VERSION 5.8 ;
BUSBITCHARS "[]" ;
DIVIDERCHAR "/" ;
UNITS
    DATABASE MICRONS 1000 ;
END UNITS

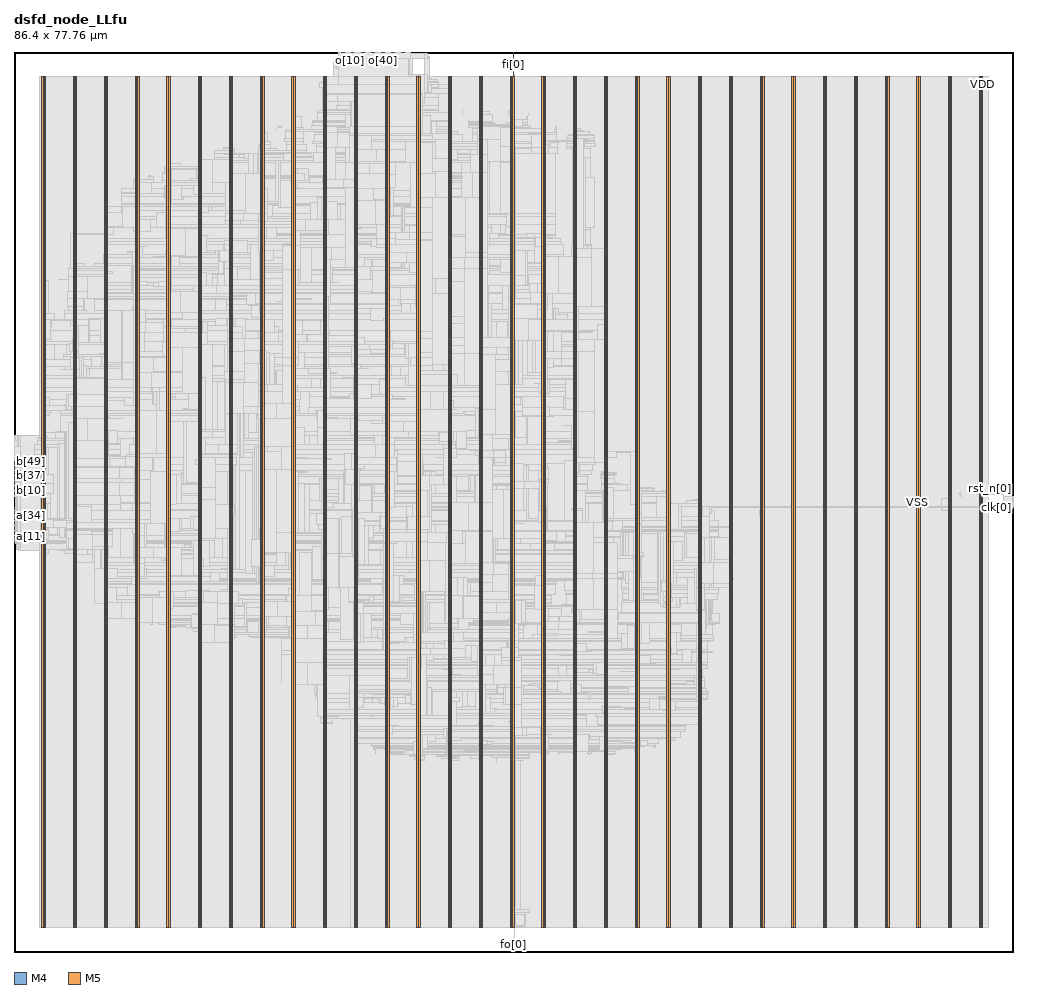
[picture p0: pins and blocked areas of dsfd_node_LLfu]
MACRO dsfd_node_LLfu
  FOREIGN dsfd_node_LLfu 0 0 ;
  CLASS BLOCK ;
  SIZE 86.4 BY 77.76 ;
  PIN a[0]
    DIRECTION INPUT ;
    USE SIGNAL ;
    PORT
      LAYER M4 ;
        RECT  0 35.376 0.084 35.4 ;
    END
  END a[0]
  PIN a[10]
    DIRECTION INPUT ;
    USE SIGNAL ;
    PORT
      LAYER M4 ;
        RECT  0 35.856 0.084 35.88 ;
    END
  END a[10]
  PIN a[11]
    DIRECTION INPUT ;
    USE SIGNAL ;
    PORT
      LAYER M4 ;
        RECT  0 35.904 0.084 35.928 ;
    END
  END a[11]
  PIN a[12]
    DIRECTION INPUT ;
    USE SIGNAL ;
    PORT
      LAYER M4 ;
        RECT  0 35.952 0.084 35.976 ;
    END
  END a[12]
  PIN a[13]
    DIRECTION INPUT ;
    USE SIGNAL ;
    PORT
      LAYER M4 ;
        RECT  0 36 0.084 36.024 ;
    END
  END a[13]
  PIN a[14]
    DIRECTION INPUT ;
    USE SIGNAL ;
    PORT
      LAYER M4 ;
        RECT  0 36.048 0.084 36.072 ;
    END
  END a[14]
  PIN a[15]
    DIRECTION INPUT ;
    USE SIGNAL ;
    PORT
      LAYER M4 ;
        RECT  0 36.096 0.084 36.12 ;
    END
  END a[15]
  PIN a[16]
    DIRECTION INPUT ;
    USE SIGNAL ;
    PORT
      LAYER M4 ;
        RECT  0 36.144 0.084 36.168 ;
    END
  END a[16]
  PIN a[17]
    DIRECTION INPUT ;
    USE SIGNAL ;
    PORT
      LAYER M4 ;
        RECT  0 36.192 0.084 36.216 ;
    END
  END a[17]
  PIN a[18]
    DIRECTION INPUT ;
    USE SIGNAL ;
    PORT
      LAYER M4 ;
        RECT  0 36.24 0.084 36.264 ;
    END
  END a[18]
  PIN a[19]
    DIRECTION INPUT ;
    USE SIGNAL ;
    PORT
      LAYER M4 ;
        RECT  0 36.288 0.084 36.312 ;
    END
  END a[19]
  PIN a[1]
    DIRECTION INPUT ;
    USE SIGNAL ;
    PORT
      LAYER M4 ;
        RECT  0 35.424 0.084 35.448 ;
    END
  END a[1]
  PIN a[20]
    DIRECTION INPUT ;
    USE SIGNAL ;
    PORT
      LAYER M4 ;
        RECT  0 36.336 0.084 36.36 ;
    END
  END a[20]
  PIN a[21]
    DIRECTION INPUT ;
    USE SIGNAL ;
    PORT
      LAYER M4 ;
        RECT  0 36.384 0.084 36.408 ;
    END
  END a[21]
  PIN a[22]
    DIRECTION INPUT ;
    USE SIGNAL ;
    PORT
      LAYER M4 ;
        RECT  0 36.432 0.084 36.456 ;
    END
  END a[22]
  PIN a[23]
    DIRECTION INPUT ;
    USE SIGNAL ;
    PORT
      LAYER M4 ;
        RECT  0 36.48 0.084 36.504 ;
    END
  END a[23]
  PIN a[24]
    DIRECTION INPUT ;
    USE SIGNAL ;
    PORT
      LAYER M4 ;
        RECT  0 36.528 0.084 36.552 ;
    END
  END a[24]
  PIN a[25]
    DIRECTION INPUT ;
    USE SIGNAL ;
    PORT
      LAYER M4 ;
        RECT  0 36.576 0.084 36.6 ;
    END
  END a[25]
  PIN a[26]
    DIRECTION INPUT ;
    USE SIGNAL ;
    PORT
      LAYER M4 ;
        RECT  0 36.624 0.084 36.648 ;
    END
  END a[26]
  PIN a[27]
    DIRECTION INPUT ;
    USE SIGNAL ;
    PORT
      LAYER M4 ;
        RECT  0 36.672 0.084 36.696 ;
    END
  END a[27]
  PIN a[28]
    DIRECTION INPUT ;
    USE SIGNAL ;
    PORT
      LAYER M4 ;
        RECT  0 36.72 0.084 36.744 ;
    END
  END a[28]
  PIN a[29]
    DIRECTION INPUT ;
    USE SIGNAL ;
    PORT
      LAYER M4 ;
        RECT  0 36.768 0.084 36.792 ;
    END
  END a[29]
  PIN a[2]
    DIRECTION INPUT ;
    USE SIGNAL ;
    PORT
      LAYER M4 ;
        RECT  0 35.472 0.084 35.496 ;
    END
  END a[2]
  PIN a[30]
    DIRECTION INPUT ;
    USE SIGNAL ;
    PORT
      LAYER M4 ;
        RECT  0 36.816 0.084 36.84 ;
    END
  END a[30]
  PIN a[31]
    DIRECTION INPUT ;
    USE SIGNAL ;
    PORT
      LAYER M4 ;
        RECT  0 36.864 0.084 36.888 ;
    END
  END a[31]
  PIN a[32]
    DIRECTION INPUT ;
    USE SIGNAL ;
    PORT
      LAYER M4 ;
        RECT  0 36.912 0.084 36.936 ;
    END
  END a[32]
  PIN a[33]
    DIRECTION INPUT ;
    USE SIGNAL ;
    PORT
      LAYER M4 ;
        RECT  0 36.96 0.084 36.984 ;
    END
  END a[33]
  PIN a[34]
    DIRECTION INPUT ;
    USE SIGNAL ;
    PORT
      LAYER M4 ;
        RECT  0 37.008 0.084 37.032 ;
    END
  END a[34]
  PIN a[35]
    DIRECTION INPUT ;
    USE SIGNAL ;
    PORT
      LAYER M4 ;
        RECT  0 37.056 0.084 37.08 ;
    END
  END a[35]
  PIN a[36]
    DIRECTION INPUT ;
    USE SIGNAL ;
    PORT
      LAYER M4 ;
        RECT  0 37.104 0.084 37.128 ;
    END
  END a[36]
  PIN a[37]
    DIRECTION INPUT ;
    USE SIGNAL ;
    PORT
      LAYER M4 ;
        RECT  0 37.152 0.084 37.176 ;
    END
  END a[37]
  PIN a[38]
    DIRECTION INPUT ;
    USE SIGNAL ;
    PORT
      LAYER M4 ;
        RECT  0 37.2 0.084 37.224 ;
    END
  END a[38]
  PIN a[39]
    DIRECTION INPUT ;
    USE SIGNAL ;
    PORT
      LAYER M4 ;
        RECT  0 37.248 0.084 37.272 ;
    END
  END a[39]
  PIN a[3]
    DIRECTION INPUT ;
    USE SIGNAL ;
    PORT
      LAYER M4 ;
        RECT  0 35.52 0.084 35.544 ;
    END
  END a[3]
  PIN a[40]
    DIRECTION INPUT ;
    USE SIGNAL ;
    PORT
      LAYER M4 ;
        RECT  0 37.296 0.084 37.32 ;
    END
  END a[40]
  PIN a[41]
    DIRECTION INPUT ;
    USE SIGNAL ;
    PORT
      LAYER M4 ;
        RECT  0 37.344 0.084 37.368 ;
    END
  END a[41]
  PIN a[42]
    DIRECTION INPUT ;
    USE SIGNAL ;
    PORT
      LAYER M4 ;
        RECT  0 37.392 0.084 37.416 ;
    END
  END a[42]
  PIN a[43]
    DIRECTION INPUT ;
    USE SIGNAL ;
    PORT
      LAYER M4 ;
        RECT  0 37.44 0.084 37.464 ;
    END
  END a[43]
  PIN a[44]
    DIRECTION INPUT ;
    USE SIGNAL ;
    PORT
      LAYER M4 ;
        RECT  0 37.488 0.084 37.512 ;
    END
  END a[44]
  PIN a[45]
    DIRECTION INPUT ;
    USE SIGNAL ;
    PORT
      LAYER M4 ;
        RECT  0 37.536 0.084 37.56 ;
    END
  END a[45]
  PIN a[46]
    DIRECTION INPUT ;
    USE SIGNAL ;
    PORT
      LAYER M4 ;
        RECT  0 37.584 0.084 37.608 ;
    END
  END a[46]
  PIN a[47]
    DIRECTION INPUT ;
    USE SIGNAL ;
    PORT
      LAYER M4 ;
        RECT  0 37.632 0.084 37.656 ;
    END
  END a[47]
  PIN a[48]
    DIRECTION INPUT ;
    USE SIGNAL ;
    PORT
      LAYER M4 ;
        RECT  0 37.68 0.084 37.704 ;
    END
  END a[48]
  PIN a[49]
    DIRECTION INPUT ;
    USE SIGNAL ;
    PORT
      LAYER M4 ;
        RECT  0 37.728 0.084 37.752 ;
    END
  END a[49]
  PIN a[4]
    DIRECTION INPUT ;
    USE SIGNAL ;
    PORT
      LAYER M4 ;
        RECT  0 35.568 0.084 35.592 ;
    END
  END a[4]
  PIN a[50]
    DIRECTION INPUT ;
    USE SIGNAL ;
    PORT
      LAYER M4 ;
        RECT  0 37.776 0.084 37.8 ;
    END
  END a[50]
  PIN a[51]
    DIRECTION INPUT ;
    USE SIGNAL ;
    PORT
      LAYER M4 ;
        RECT  0 37.824 0.084 37.848 ;
    END
  END a[51]
  PIN a[52]
    DIRECTION INPUT ;
    USE SIGNAL ;
    PORT
      LAYER M4 ;
        RECT  0 37.872 0.084 37.896 ;
    END
  END a[52]
  PIN a[53]
    DIRECTION INPUT ;
    USE SIGNAL ;
    PORT
      LAYER M4 ;
        RECT  0 37.92 0.084 37.944 ;
    END
  END a[53]
  PIN a[54]
    DIRECTION INPUT ;
    USE SIGNAL ;
    PORT
      LAYER M4 ;
        RECT  0 37.968 0.084 37.992 ;
    END
  END a[54]
  PIN a[55]
    DIRECTION INPUT ;
    USE SIGNAL ;
    PORT
      LAYER M4 ;
        RECT  0 38.016 0.084 38.04 ;
    END
  END a[55]
  PIN a[56]
    DIRECTION INPUT ;
    USE SIGNAL ;
    PORT
      LAYER M4 ;
        RECT  0 38.064 0.084 38.088 ;
    END
  END a[56]
  PIN a[57]
    DIRECTION INPUT ;
    USE SIGNAL ;
    PORT
      LAYER M4 ;
        RECT  0 38.112 0.084 38.136 ;
    END
  END a[57]
  PIN a[58]
    DIRECTION INPUT ;
    USE SIGNAL ;
    PORT
      LAYER M4 ;
        RECT  0 38.16 0.084 38.184 ;
    END
  END a[58]
  PIN a[59]
    DIRECTION INPUT ;
    USE SIGNAL ;
    PORT
      LAYER M4 ;
        RECT  0 38.208 0.084 38.232 ;
    END
  END a[59]
  PIN a[5]
    DIRECTION INPUT ;
    USE SIGNAL ;
    PORT
      LAYER M4 ;
        RECT  0 35.616 0.084 35.64 ;
    END
  END a[5]
  PIN a[60]
    DIRECTION INPUT ;
    USE SIGNAL ;
    PORT
      LAYER M4 ;
        RECT  0 38.256 0.084 38.28 ;
    END
  END a[60]
  PIN a[61]
    DIRECTION INPUT ;
    USE SIGNAL ;
    PORT
      LAYER M4 ;
        RECT  0 38.304 0.084 38.328 ;
    END
  END a[61]
  PIN a[62]
    DIRECTION INPUT ;
    USE SIGNAL ;
    PORT
      LAYER M4 ;
        RECT  0 38.352 0.084 38.376 ;
    END
  END a[62]
  PIN a[6]
    DIRECTION INPUT ;
    USE SIGNAL ;
    PORT
      LAYER M4 ;
        RECT  0 35.664 0.084 35.688 ;
    END
  END a[6]
  PIN a[7]
    DIRECTION INPUT ;
    USE SIGNAL ;
    PORT
      LAYER M4 ;
        RECT  0 35.712 0.084 35.736 ;
    END
  END a[7]
  PIN a[8]
    DIRECTION INPUT ;
    USE SIGNAL ;
    PORT
      LAYER M4 ;
        RECT  0 35.76 0.084 35.784 ;
    END
  END a[8]
  PIN a[9]
    DIRECTION INPUT ;
    USE SIGNAL ;
    PORT
      LAYER M4 ;
        RECT  0 35.808 0.084 35.832 ;
    END
  END a[9]
  PIN b[0]
    DIRECTION INPUT ;
    USE SIGNAL ;
    PORT
      LAYER M4 ;
        RECT  0 39.36 0.084 39.384 ;
    END
  END b[0]
  PIN b[10]
    DIRECTION INPUT ;
    USE SIGNAL ;
    PORT
      LAYER M4 ;
        RECT  0 39.84 0.084 39.864 ;
    END
  END b[10]
  PIN b[11]
    DIRECTION INPUT ;
    USE SIGNAL ;
    PORT
      LAYER M4 ;
        RECT  0 39.888 0.084 39.912 ;
    END
  END b[11]
  PIN b[12]
    DIRECTION INPUT ;
    USE SIGNAL ;
    PORT
      LAYER M4 ;
        RECT  0 39.936 0.084 39.96 ;
    END
  END b[12]
  PIN b[13]
    DIRECTION INPUT ;
    USE SIGNAL ;
    PORT
      LAYER M4 ;
        RECT  0 39.984 0.084 40.008 ;
    END
  END b[13]
  PIN b[14]
    DIRECTION INPUT ;
    USE SIGNAL ;
    PORT
      LAYER M4 ;
        RECT  0 40.032 0.084 40.056 ;
    END
  END b[14]
  PIN b[15]
    DIRECTION INPUT ;
    USE SIGNAL ;
    PORT
      LAYER M4 ;
        RECT  0 40.08 0.084 40.104 ;
    END
  END b[15]
  PIN b[16]
    DIRECTION INPUT ;
    USE SIGNAL ;
    PORT
      LAYER M4 ;
        RECT  0 40.128 0.084 40.152 ;
    END
  END b[16]
  PIN b[17]
    DIRECTION INPUT ;
    USE SIGNAL ;
    PORT
      LAYER M4 ;
        RECT  0 40.176 0.084 40.2 ;
    END
  END b[17]
  PIN b[18]
    DIRECTION INPUT ;
    USE SIGNAL ;
    PORT
      LAYER M4 ;
        RECT  0 40.224 0.084 40.248 ;
    END
  END b[18]
  PIN b[19]
    DIRECTION INPUT ;
    USE SIGNAL ;
    PORT
      LAYER M4 ;
        RECT  0 40.272 0.084 40.296 ;
    END
  END b[19]
  PIN b[1]
    DIRECTION INPUT ;
    USE SIGNAL ;
    PORT
      LAYER M4 ;
        RECT  0 39.408 0.084 39.432 ;
    END
  END b[1]
  PIN b[20]
    DIRECTION INPUT ;
    USE SIGNAL ;
    PORT
      LAYER M4 ;
        RECT  0 40.32 0.084 40.344 ;
    END
  END b[20]
  PIN b[21]
    DIRECTION INPUT ;
    USE SIGNAL ;
    PORT
      LAYER M4 ;
        RECT  0 40.368 0.084 40.392 ;
    END
  END b[21]
  PIN b[22]
    DIRECTION INPUT ;
    USE SIGNAL ;
    PORT
      LAYER M4 ;
        RECT  0 40.416 0.084 40.44 ;
    END
  END b[22]
  PIN b[23]
    DIRECTION INPUT ;
    USE SIGNAL ;
    PORT
      LAYER M4 ;
        RECT  0 40.464 0.084 40.488 ;
    END
  END b[23]
  PIN b[24]
    DIRECTION INPUT ;
    USE SIGNAL ;
    PORT
      LAYER M4 ;
        RECT  0 40.512 0.084 40.536 ;
    END
  END b[24]
  PIN b[25]
    DIRECTION INPUT ;
    USE SIGNAL ;
    PORT
      LAYER M4 ;
        RECT  0 40.56 0.084 40.584 ;
    END
  END b[25]
  PIN b[26]
    DIRECTION INPUT ;
    USE SIGNAL ;
    PORT
      LAYER M4 ;
        RECT  0 40.608 0.084 40.632 ;
    END
  END b[26]
  PIN b[27]
    DIRECTION INPUT ;
    USE SIGNAL ;
    PORT
      LAYER M4 ;
        RECT  0 40.656 0.084 40.68 ;
    END
  END b[27]
  PIN b[28]
    DIRECTION INPUT ;
    USE SIGNAL ;
    PORT
      LAYER M4 ;
        RECT  0 40.704 0.084 40.728 ;
    END
  END b[28]
  PIN b[29]
    DIRECTION INPUT ;
    USE SIGNAL ;
    PORT
      LAYER M4 ;
        RECT  0 40.752 0.084 40.776 ;
    END
  END b[29]
  PIN b[2]
    DIRECTION INPUT ;
    USE SIGNAL ;
    PORT
      LAYER M4 ;
        RECT  0 39.456 0.084 39.48 ;
    END
  END b[2]
  PIN b[30]
    DIRECTION INPUT ;
    USE SIGNAL ;
    PORT
      LAYER M4 ;
        RECT  0 40.8 0.084 40.824 ;
    END
  END b[30]
  PIN b[31]
    DIRECTION INPUT ;
    USE SIGNAL ;
    PORT
      LAYER M4 ;
        RECT  0 40.848 0.084 40.872 ;
    END
  END b[31]
  PIN b[32]
    DIRECTION INPUT ;
    USE SIGNAL ;
    PORT
      LAYER M4 ;
        RECT  0 40.896 0.084 40.92 ;
    END
  END b[32]
  PIN b[33]
    DIRECTION INPUT ;
    USE SIGNAL ;
    PORT
      LAYER M4 ;
        RECT  0 40.944 0.084 40.968 ;
    END
  END b[33]
  PIN b[34]
    DIRECTION INPUT ;
    USE SIGNAL ;
    PORT
      LAYER M4 ;
        RECT  0 40.992 0.084 41.016 ;
    END
  END b[34]
  PIN b[35]
    DIRECTION INPUT ;
    USE SIGNAL ;
    PORT
      LAYER M4 ;
        RECT  0 41.04 0.084 41.064 ;
    END
  END b[35]
  PIN b[36]
    DIRECTION INPUT ;
    USE SIGNAL ;
    PORT
      LAYER M4 ;
        RECT  0 41.088 0.084 41.112 ;
    END
  END b[36]
  PIN b[37]
    DIRECTION INPUT ;
    USE SIGNAL ;
    PORT
      LAYER M4 ;
        RECT  0 41.136 0.084 41.16 ;
    END
  END b[37]
  PIN b[38]
    DIRECTION INPUT ;
    USE SIGNAL ;
    PORT
      LAYER M4 ;
        RECT  0 41.184 0.084 41.208 ;
    END
  END b[38]
  PIN b[39]
    DIRECTION INPUT ;
    USE SIGNAL ;
    PORT
      LAYER M4 ;
        RECT  0 41.232 0.084 41.256 ;
    END
  END b[39]
  PIN b[3]
    DIRECTION INPUT ;
    USE SIGNAL ;
    PORT
      LAYER M4 ;
        RECT  0 39.504 0.084 39.528 ;
    END
  END b[3]
  PIN b[40]
    DIRECTION INPUT ;
    USE SIGNAL ;
    PORT
      LAYER M4 ;
        RECT  0 41.28 0.084 41.304 ;
    END
  END b[40]
  PIN b[41]
    DIRECTION INPUT ;
    USE SIGNAL ;
    PORT
      LAYER M4 ;
        RECT  0 41.328 0.084 41.352 ;
    END
  END b[41]
  PIN b[42]
    DIRECTION INPUT ;
    USE SIGNAL ;
    PORT
      LAYER M4 ;
        RECT  0 41.376 0.084 41.4 ;
    END
  END b[42]
  PIN b[43]
    DIRECTION INPUT ;
    USE SIGNAL ;
    PORT
      LAYER M4 ;
        RECT  0 41.424 0.084 41.448 ;
    END
  END b[43]
  PIN b[44]
    DIRECTION INPUT ;
    USE SIGNAL ;
    PORT
      LAYER M4 ;
        RECT  0 41.472 0.084 41.496 ;
    END
  END b[44]
  PIN b[45]
    DIRECTION INPUT ;
    USE SIGNAL ;
    PORT
      LAYER M4 ;
        RECT  0 41.52 0.084 41.544 ;
    END
  END b[45]
  PIN b[46]
    DIRECTION INPUT ;
    USE SIGNAL ;
    PORT
      LAYER M4 ;
        RECT  0 41.568 0.084 41.592 ;
    END
  END b[46]
  PIN b[47]
    DIRECTION INPUT ;
    USE SIGNAL ;
    PORT
      LAYER M4 ;
        RECT  0 41.616 0.084 41.64 ;
    END
  END b[47]
  PIN b[48]
    DIRECTION INPUT ;
    USE SIGNAL ;
    PORT
      LAYER M4 ;
        RECT  0 41.664 0.084 41.688 ;
    END
  END b[48]
  PIN b[49]
    DIRECTION INPUT ;
    USE SIGNAL ;
    PORT
      LAYER M4 ;
        RECT  0 41.712 0.084 41.736 ;
    END
  END b[49]
  PIN b[4]
    DIRECTION INPUT ;
    USE SIGNAL ;
    PORT
      LAYER M4 ;
        RECT  0 39.552 0.084 39.576 ;
    END
  END b[4]
  PIN b[50]
    DIRECTION INPUT ;
    USE SIGNAL ;
    PORT
      LAYER M4 ;
        RECT  0 41.76 0.084 41.784 ;
    END
  END b[50]
  PIN b[51]
    DIRECTION INPUT ;
    USE SIGNAL ;
    PORT
      LAYER M4 ;
        RECT  0 41.808 0.084 41.832 ;
    END
  END b[51]
  PIN b[52]
    DIRECTION INPUT ;
    USE SIGNAL ;
    PORT
      LAYER M4 ;
        RECT  0 41.856 0.084 41.88 ;
    END
  END b[52]
  PIN b[53]
    DIRECTION INPUT ;
    USE SIGNAL ;
    PORT
      LAYER M4 ;
        RECT  0 41.904 0.084 41.928 ;
    END
  END b[53]
  PIN b[54]
    DIRECTION INPUT ;
    USE SIGNAL ;
    PORT
      LAYER M4 ;
        RECT  0 41.952 0.084 41.976 ;
    END
  END b[54]
  PIN b[55]
    DIRECTION INPUT ;
    USE SIGNAL ;
    PORT
      LAYER M4 ;
        RECT  0 42 0.084 42.024 ;
    END
  END b[55]
  PIN b[56]
    DIRECTION INPUT ;
    USE SIGNAL ;
    PORT
      LAYER M4 ;
        RECT  0 42.048 0.084 42.072 ;
    END
  END b[56]
  PIN b[57]
    DIRECTION INPUT ;
    USE SIGNAL ;
    PORT
      LAYER M4 ;
        RECT  0 42.096 0.084 42.12 ;
    END
  END b[57]
  PIN b[58]
    DIRECTION INPUT ;
    USE SIGNAL ;
    PORT
      LAYER M4 ;
        RECT  0 42.144 0.084 42.168 ;
    END
  END b[58]
  PIN b[59]
    DIRECTION INPUT ;
    USE SIGNAL ;
    PORT
      LAYER M4 ;
        RECT  0 42.192 0.084 42.216 ;
    END
  END b[59]
  PIN b[5]
    DIRECTION INPUT ;
    USE SIGNAL ;
    PORT
      LAYER M4 ;
        RECT  0 39.6 0.084 39.624 ;
    END
  END b[5]
  PIN b[60]
    DIRECTION INPUT ;
    USE SIGNAL ;
    PORT
      LAYER M4 ;
        RECT  0 42.24 0.084 42.264 ;
    END
  END b[60]
  PIN b[61]
    DIRECTION INPUT ;
    USE SIGNAL ;
    PORT
      LAYER M4 ;
        RECT  0 42.288 0.084 42.312 ;
    END
  END b[61]
  PIN b[62]
    DIRECTION INPUT ;
    USE SIGNAL ;
    PORT
      LAYER M4 ;
        RECT  0 42.336 0.084 42.36 ;
    END
  END b[62]
  PIN b[6]
    DIRECTION INPUT ;
    USE SIGNAL ;
    PORT
      LAYER M4 ;
        RECT  0 39.648 0.084 39.672 ;
    END
  END b[6]
  PIN b[7]
    DIRECTION INPUT ;
    USE SIGNAL ;
    PORT
      LAYER M4 ;
        RECT  0 39.696 0.084 39.72 ;
    END
  END b[7]
  PIN b[8]
    DIRECTION INPUT ;
    USE SIGNAL ;
    PORT
      LAYER M4 ;
        RECT  0 39.744 0.084 39.768 ;
    END
  END b[8]
  PIN b[9]
    DIRECTION INPUT ;
    USE SIGNAL ;
    PORT
      LAYER M4 ;
        RECT  0 39.792 0.084 39.816 ;
    END
  END b[9]
  PIN clk[0]
    DIRECTION INPUT ;
    USE SIGNAL ;
    PORT
      LAYER M4 ;
        RECT  86.316 38.352 86.4 38.376 ;
    END
    PORT
      LAYER M4 ;
        RECT  86.321 38.352 86.364 38.376 ;
    END
  END clk[0]
  PIN fi[0]
    DIRECTION INPUT ;
    USE SIGNAL ;
    PORT
      LAYER M5 ;
        RECT  43.152 77.676 43.176 77.76 ;
    END
    PORT
      LAYER M5 ;
        RECT  43.152 75.623 43.176 77.712 ;
    END
  END fi[0]
  PIN fo[0]
    DIRECTION OUTPUT ;
    USE SIGNAL ;
    PORT
      LAYER M5 ;
        RECT  43.152 0 43.176 0.084 ;
    END
    PORT
      LAYER M5 ;
        RECT  43.152 0.016 43.176 0.563 ;
    END
  END fo[0]
  PIN o[0]
    DIRECTION OUTPUT ;
    USE SIGNAL ;
    PORT
      LAYER M5 ;
        RECT  28.032 77.676 28.056 77.76 ;
    END
  END o[0]
  PIN o[10]
    DIRECTION OUTPUT ;
    USE SIGNAL ;
    PORT
      LAYER M5 ;
        RECT  28.992 77.676 29.016 77.76 ;
    END
  END o[10]
  PIN o[11]
    DIRECTION OUTPUT ;
    USE SIGNAL ;
    PORT
      LAYER M5 ;
        RECT  29.088 77.676 29.112 77.76 ;
    END
  END o[11]
  PIN o[12]
    DIRECTION OUTPUT ;
    USE SIGNAL ;
    PORT
      LAYER M5 ;
        RECT  29.184 77.676 29.208 77.76 ;
    END
  END o[12]
  PIN o[13]
    DIRECTION OUTPUT ;
    USE SIGNAL ;
    PORT
      LAYER M5 ;
        RECT  29.28 77.676 29.304 77.76 ;
    END
  END o[13]
  PIN o[14]
    DIRECTION OUTPUT ;
    USE SIGNAL ;
    PORT
      LAYER M5 ;
        RECT  29.376 77.676 29.4 77.76 ;
    END
  END o[14]
  PIN o[15]
    DIRECTION OUTPUT ;
    USE SIGNAL ;
    PORT
      LAYER M5 ;
        RECT  29.472 77.676 29.496 77.76 ;
    END
  END o[15]
  PIN o[16]
    DIRECTION OUTPUT ;
    USE SIGNAL ;
    PORT
      LAYER M5 ;
        RECT  29.568 77.676 29.592 77.76 ;
    END
  END o[16]
  PIN o[17]
    DIRECTION OUTPUT ;
    USE SIGNAL ;
    PORT
      LAYER M5 ;
        RECT  29.664 77.676 29.688 77.76 ;
    END
  END o[17]
  PIN o[18]
    DIRECTION OUTPUT ;
    USE SIGNAL ;
    PORT
      LAYER M5 ;
        RECT  29.76 77.676 29.784 77.76 ;
    END
  END o[18]
  PIN o[19]
    DIRECTION OUTPUT ;
    USE SIGNAL ;
    PORT
      LAYER M5 ;
        RECT  29.856 77.676 29.88 77.76 ;
    END
  END o[19]
  PIN o[1]
    DIRECTION OUTPUT ;
    USE SIGNAL ;
    PORT
      LAYER M5 ;
        RECT  28.128 77.676 28.152 77.76 ;
    END
  END o[1]
  PIN o[20]
    DIRECTION OUTPUT ;
    USE SIGNAL ;
    PORT
      LAYER M5 ;
        RECT  29.952 77.676 29.976 77.76 ;
    END
  END o[20]
  PIN o[21]
    DIRECTION OUTPUT ;
    USE SIGNAL ;
    PORT
      LAYER M5 ;
        RECT  30.048 77.676 30.072 77.76 ;
    END
  END o[21]
  PIN o[22]
    DIRECTION OUTPUT ;
    USE SIGNAL ;
    PORT
      LAYER M5 ;
        RECT  30.144 77.676 30.168 77.76 ;
    END
  END o[22]
  PIN o[23]
    DIRECTION OUTPUT ;
    USE SIGNAL ;
    PORT
      LAYER M5 ;
        RECT  30.24 77.676 30.264 77.76 ;
    END
  END o[23]
  PIN o[24]
    DIRECTION OUTPUT ;
    USE SIGNAL ;
    PORT
      LAYER M5 ;
        RECT  30.336 77.676 30.36 77.76 ;
    END
  END o[24]
  PIN o[25]
    DIRECTION OUTPUT ;
    USE SIGNAL ;
    PORT
      LAYER M5 ;
        RECT  30.432 77.676 30.456 77.76 ;
    END
  END o[25]
  PIN o[26]
    DIRECTION OUTPUT ;
    USE SIGNAL ;
    PORT
      LAYER M5 ;
        RECT  30.528 77.676 30.552 77.76 ;
    END
  END o[26]
  PIN o[27]
    DIRECTION OUTPUT ;
    USE SIGNAL ;
    PORT
      LAYER M5 ;
        RECT  30.624 77.676 30.648 77.76 ;
    END
  END o[27]
  PIN o[28]
    DIRECTION OUTPUT ;
    USE SIGNAL ;
    PORT
      LAYER M5 ;
        RECT  30.72 77.676 30.744 77.76 ;
    END
  END o[28]
  PIN o[29]
    DIRECTION OUTPUT ;
    USE SIGNAL ;
    PORT
      LAYER M5 ;
        RECT  30.816 77.676 30.84 77.76 ;
    END
  END o[29]
  PIN o[2]
    DIRECTION OUTPUT ;
    USE SIGNAL ;
    PORT
      LAYER M5 ;
        RECT  28.224 77.676 28.248 77.76 ;
    END
  END o[2]
  PIN o[30]
    DIRECTION OUTPUT ;
    USE SIGNAL ;
    PORT
      LAYER M5 ;
        RECT  30.912 77.676 30.936 77.76 ;
    END
  END o[30]
  PIN o[31]
    DIRECTION OUTPUT ;
    USE SIGNAL ;
    PORT
      LAYER M5 ;
        RECT  31.008 77.676 31.032 77.76 ;
    END
  END o[31]
  PIN o[32]
    DIRECTION OUTPUT ;
    USE SIGNAL ;
    PORT
      LAYER M5 ;
        RECT  31.104 77.676 31.128 77.76 ;
    END
  END o[32]
  PIN o[33]
    DIRECTION OUTPUT ;
    USE SIGNAL ;
    PORT
      LAYER M5 ;
        RECT  31.2 77.676 31.224 77.76 ;
    END
  END o[33]
  PIN o[34]
    DIRECTION OUTPUT ;
    USE SIGNAL ;
    PORT
      LAYER M5 ;
        RECT  31.296 77.676 31.32 77.76 ;
    END
  END o[34]
  PIN o[35]
    DIRECTION OUTPUT ;
    USE SIGNAL ;
    PORT
      LAYER M5 ;
        RECT  31.392 77.676 31.416 77.76 ;
    END
  END o[35]
  PIN o[36]
    DIRECTION OUTPUT ;
    USE SIGNAL ;
    PORT
      LAYER M5 ;
        RECT  31.488 77.676 31.512 77.76 ;
    END
  END o[36]
  PIN o[37]
    DIRECTION OUTPUT ;
    USE SIGNAL ;
    PORT
      LAYER M5 ;
        RECT  31.584 77.676 31.608 77.76 ;
    END
  END o[37]
  PIN o[38]
    DIRECTION OUTPUT ;
    USE SIGNAL ;
    PORT
      LAYER M5 ;
        RECT  31.68 77.676 31.704 77.76 ;
    END
  END o[38]
  PIN o[39]
    DIRECTION OUTPUT ;
    USE SIGNAL ;
    PORT
      LAYER M5 ;
        RECT  31.776 77.676 31.8 77.76 ;
    END
  END o[39]
  PIN o[3]
    DIRECTION OUTPUT ;
    USE SIGNAL ;
    PORT
      LAYER M5 ;
        RECT  28.32 77.676 28.344 77.76 ;
    END
  END o[3]
  PIN o[40]
    DIRECTION OUTPUT ;
    USE SIGNAL ;
    PORT
      LAYER M5 ;
        RECT  31.872 77.676 31.896 77.76 ;
    END
  END o[40]
  PIN o[41]
    DIRECTION OUTPUT ;
    USE SIGNAL ;
    PORT
      LAYER M5 ;
        RECT  31.968 77.676 31.992 77.76 ;
    END
  END o[41]
  PIN o[42]
    DIRECTION OUTPUT ;
    USE SIGNAL ;
    PORT
      LAYER M5 ;
        RECT  32.064 77.676 32.088 77.76 ;
    END
  END o[42]
  PIN o[43]
    DIRECTION OUTPUT ;
    USE SIGNAL ;
    PORT
      LAYER M5 ;
        RECT  32.16 77.676 32.184 77.76 ;
    END
  END o[43]
  PIN o[44]
    DIRECTION OUTPUT ;
    USE SIGNAL ;
    PORT
      LAYER M5 ;
        RECT  32.256 77.676 32.28 77.76 ;
    END
  END o[44]
  PIN o[45]
    DIRECTION OUTPUT ;
    USE SIGNAL ;
    PORT
      LAYER M5 ;
        RECT  32.352 77.676 32.376 77.76 ;
    END
  END o[45]
  PIN o[46]
    DIRECTION OUTPUT ;
    USE SIGNAL ;
    PORT
      LAYER M5 ;
        RECT  32.448 77.676 32.472 77.76 ;
    END
  END o[46]
  PIN o[47]
    DIRECTION OUTPUT ;
    USE SIGNAL ;
    PORT
      LAYER M5 ;
        RECT  32.544 77.676 32.568 77.76 ;
    END
  END o[47]
  PIN o[48]
    DIRECTION OUTPUT ;
    USE SIGNAL ;
    PORT
      LAYER M5 ;
        RECT  32.64 77.676 32.664 77.76 ;
    END
  END o[48]
  PIN o[49]
    DIRECTION OUTPUT ;
    USE SIGNAL ;
    PORT
      LAYER M5 ;
        RECT  32.736 77.676 32.76 77.76 ;
    END
  END o[49]
  PIN o[4]
    DIRECTION OUTPUT ;
    USE SIGNAL ;
    PORT
      LAYER M5 ;
        RECT  28.416 77.676 28.44 77.76 ;
    END
  END o[4]
  PIN o[50]
    DIRECTION OUTPUT ;
    USE SIGNAL ;
    PORT
      LAYER M5 ;
        RECT  32.832 77.676 32.856 77.76 ;
    END
  END o[50]
  PIN o[51]
    DIRECTION OUTPUT ;
    USE SIGNAL ;
    PORT
      LAYER M5 ;
        RECT  32.928 77.676 32.952 77.76 ;
    END
  END o[51]
  PIN o[52]
    DIRECTION OUTPUT ;
    USE SIGNAL ;
    PORT
      LAYER M5 ;
        RECT  33.024 77.676 33.048 77.76 ;
    END
  END o[52]
  PIN o[53]
    DIRECTION OUTPUT ;
    USE SIGNAL ;
    PORT
      LAYER M5 ;
        RECT  33.12 77.676 33.144 77.76 ;
    END
  END o[53]
  PIN o[54]
    DIRECTION OUTPUT ;
    USE SIGNAL ;
    PORT
      LAYER M5 ;
        RECT  33.216 77.676 33.24 77.76 ;
    END
  END o[54]
  PIN o[55]
    DIRECTION OUTPUT ;
    USE SIGNAL ;
    PORT
      LAYER M5 ;
        RECT  33.312 77.676 33.336 77.76 ;
    END
  END o[55]
  PIN o[56]
    DIRECTION OUTPUT ;
    USE SIGNAL ;
    PORT
      LAYER M5 ;
        RECT  33.408 77.676 33.432 77.76 ;
    END
  END o[56]
  PIN o[57]
    DIRECTION OUTPUT ;
    USE SIGNAL ;
    PORT
      LAYER M5 ;
        RECT  33.504 77.676 33.528 77.76 ;
    END
  END o[57]
  PIN o[58]
    DIRECTION OUTPUT ;
    USE SIGNAL ;
    PORT
      LAYER M5 ;
        RECT  33.6 77.676 33.624 77.76 ;
    END
  END o[58]
  PIN o[59]
    DIRECTION OUTPUT ;
    USE SIGNAL ;
    PORT
      LAYER M5 ;
        RECT  33.696 77.676 33.72 77.76 ;
    END
  END o[59]
  PIN o[5]
    DIRECTION OUTPUT ;
    USE SIGNAL ;
    PORT
      LAYER M5 ;
        RECT  28.512 77.676 28.536 77.76 ;
    END
  END o[5]
  PIN o[60]
    DIRECTION OUTPUT ;
    USE SIGNAL ;
    PORT
      LAYER M5 ;
        RECT  33.792 77.676 33.816 77.76 ;
    END
  END o[60]
  PIN o[61]
    DIRECTION OUTPUT ;
    USE SIGNAL ;
    PORT
      LAYER M5 ;
        RECT  33.888 77.676 33.912 77.76 ;
    END
  END o[61]
  PIN o[62]
    DIRECTION OUTPUT ;
    USE SIGNAL ;
    PORT
      LAYER M5 ;
        RECT  33.984 77.676 34.008 77.76 ;
    END
  END o[62]
  PIN o[63]
    DIRECTION OUTPUT ;
    USE SIGNAL ;
    PORT
      LAYER M5 ;
        RECT  34.08 77.676 34.104 77.76 ;
    END
  END o[63]
  PIN o[64]
    DIRECTION OUTPUT ;
    USE SIGNAL ;
    PORT
      LAYER M5 ;
        RECT  34.176 77.676 34.2 77.76 ;
    END
  END o[64]
  PIN o[65]
    DIRECTION OUTPUT ;
    USE SIGNAL ;
    PORT
      LAYER M5 ;
        RECT  34.272 77.676 34.296 77.76 ;
    END
  END o[65]
  PIN o[6]
    DIRECTION OUTPUT ;
    USE SIGNAL ;
    PORT
      LAYER M5 ;
        RECT  28.608 77.676 28.632 77.76 ;
    END
  END o[6]
  PIN o[7]
    DIRECTION OUTPUT ;
    USE SIGNAL ;
    PORT
      LAYER M5 ;
        RECT  28.704 77.676 28.728 77.76 ;
    END
  END o[7]
  PIN o[8]
    DIRECTION OUTPUT ;
    USE SIGNAL ;
    PORT
      LAYER M5 ;
        RECT  28.8 77.676 28.824 77.76 ;
    END
  END o[8]
  PIN o[9]
    DIRECTION OUTPUT ;
    USE SIGNAL ;
    PORT
      LAYER M5 ;
        RECT  28.896 77.676 28.92 77.76 ;
    END
  END o[9]
  PIN rst_n[0]
    DIRECTION INPUT ;
    USE SIGNAL ;
    PORT
      LAYER M4 ;
        RECT  86.316 39.36 86.4 39.384 ;
    END
    PORT
      LAYER M4 ;
        RECT  86.321 39.36 86.364 39.384 ;
    END
  END rst_n[0]
  PIN VDD
    DIRECTION INOUT ;
    USE POWER ;
    PORT
      LAYER M5 ;
        RECT  83.592 2.151 83.712 75.609 ;
        RECT  80.892 2.151 81.012 75.609 ;
        RECT  78.192 2.151 78.312 75.609 ;
        RECT  75.492 2.151 75.612 75.609 ;
        RECT  72.792 2.151 72.912 75.609 ;
        RECT  70.092 2.151 70.212 75.609 ;
        RECT  67.392 2.151 67.512 75.609 ;
        RECT  64.692 2.151 64.812 75.609 ;
        RECT  61.992 2.151 62.112 75.609 ;
        RECT  59.292 2.151 59.412 75.609 ;
        RECT  56.592 2.151 56.712 75.609 ;
        RECT  53.892 2.151 54.012 75.609 ;
        RECT  51.192 2.151 51.312 75.609 ;
        RECT  48.492 2.151 48.612 75.609 ;
        RECT  45.792 2.151 45.912 75.609 ;
        RECT  43.092 2.151 43.212 75.609 ;
        RECT  40.392 2.151 40.512 75.609 ;
        RECT  37.692 2.151 37.812 75.609 ;
        RECT  34.992 2.151 35.112 75.609 ;
        RECT  32.292 2.151 32.412 75.609 ;
        RECT  29.592 2.151 29.712 75.609 ;
        RECT  26.892 2.151 27.012 75.609 ;
        RECT  24.192 2.151 24.312 75.609 ;
        RECT  21.492 2.151 21.612 75.609 ;
        RECT  18.792 2.151 18.912 75.609 ;
        RECT  16.092 2.151 16.212 75.609 ;
        RECT  13.392 2.151 13.512 75.609 ;
        RECT  10.692 2.151 10.812 75.609 ;
        RECT  7.992 2.151 8.112 75.609 ;
        RECT  5.292 2.151 5.412 75.609 ;
        RECT  2.592 2.151 2.712 75.609 ;
    END
  END VDD
  PIN VSS
    DIRECTION INOUT ;
    USE GROUND ;
    PORT
      LAYER M5 ;
        RECT  83.4 2.137 83.52 75.623 ;
        RECT  80.7 2.137 80.82 75.623 ;
        RECT  78 2.137 78.12 75.623 ;
        RECT  75.3 2.137 75.42 75.623 ;
        RECT  72.6 2.137 72.72 75.623 ;
        RECT  69.9 2.137 70.02 75.623 ;
        RECT  67.2 2.137 67.32 75.623 ;
        RECT  64.5 2.137 64.62 75.623 ;
        RECT  61.8 2.137 61.92 75.623 ;
        RECT  59.1 2.137 59.22 75.623 ;
        RECT  56.4 2.137 56.52 75.623 ;
        RECT  53.7 2.137 53.82 75.623 ;
        RECT  51 2.137 51.12 75.623 ;
        RECT  48.3 2.137 48.42 75.623 ;
        RECT  45.6 2.137 45.72 75.623 ;
        RECT  42.9 2.137 43.02 75.623 ;
        RECT  40.2 2.137 40.32 75.623 ;
        RECT  37.5 2.137 37.62 75.623 ;
        RECT  34.8 2.137 34.92 75.623 ;
        RECT  32.1 2.137 32.22 75.623 ;
        RECT  29.4 2.137 29.52 75.623 ;
        RECT  26.7 2.137 26.82 75.623 ;
        RECT  24 2.137 24.12 75.623 ;
        RECT  21.3 2.137 21.42 75.623 ;
        RECT  18.6 2.137 18.72 75.623 ;
        RECT  15.9 2.137 16.02 75.623 ;
        RECT  13.2 2.137 13.32 75.623 ;
        RECT  10.5 2.137 10.62 75.623 ;
        RECT  7.8 2.137 7.92 75.623 ;
        RECT  5.1 2.137 5.22 75.623 ;
        RECT  2.4 2.137 2.52 75.623 ;
    END
  END VSS
  # OT_OBS_CLOSED layer=M5 d_um=1.536 added=251
  OBS
    LAYER RVTN ;
     RECT  2.16 2.16 84.24 2.295 ;
     RECT  2.16 2.565 84.24 2.835 ;
     RECT  2.16 3.105 84.24 3.375 ;
     RECT  2.16 3.645 84.24 3.915 ;
     RECT  2.16 4.185 84.24 4.455 ;
     RECT  2.16 4.725 84.24 4.995 ;
     RECT  2.16 5.265 84.24 5.535 ;
     RECT  2.16 5.805 84.24 6.075 ;
     RECT  2.16 6.345 84.24 6.615 ;
     RECT  2.16 6.885 84.24 7.155 ;
     RECT  2.16 7.425 84.24 7.695 ;
     RECT  2.16 7.965 84.24 8.235 ;
     RECT  2.16 8.505 84.24 8.775 ;
     RECT  2.16 9.045 84.24 9.315 ;
     RECT  2.16 9.585 84.24 9.855 ;
     RECT  2.16 10.125 84.24 10.395 ;
     RECT  2.16 10.665 84.24 10.935 ;
     RECT  2.16 11.205 84.24 11.475 ;
     RECT  2.16 11.745 84.24 12.015 ;
     RECT  2.16 12.285 84.24 12.555 ;
     RECT  2.16 12.825 84.24 13.095 ;
     RECT  2.16 13.365 84.24 13.635 ;
     RECT  2.16 13.905 84.24 14.175 ;
     RECT  2.16 14.445 84.24 14.715 ;
     RECT  2.16 14.985 84.24 15.255 ;
     RECT  2.16 15.525 84.24 15.795 ;
     RECT  2.16 16.065 84.24 16.335 ;
     RECT  2.16 16.605 84.24 16.875 ;
     RECT  2.16 17.145 84.24 17.415 ;
     RECT  2.16 17.685 84.24 17.955 ;
     RECT  2.16 18.225 84.24 18.495 ;
     RECT  2.16 18.765 84.24 19.035 ;
     RECT  2.16 19.305 84.24 19.575 ;
     RECT  2.16 19.845 84.24 20.115 ;
     RECT  2.16 20.385 84.24 20.655 ;
     RECT  2.16 20.925 84.24 21.195 ;
     RECT  2.16 21.465 84.24 21.735 ;
     RECT  2.16 22.005 84.24 22.275 ;
     RECT  2.16 22.545 84.24 22.815 ;
     RECT  2.16 23.085 84.24 23.355 ;
     RECT  2.16 23.625 84.24 23.895 ;
     RECT  2.16 24.165 84.24 24.435 ;
     RECT  2.16 24.705 84.24 24.975 ;
     RECT  2.16 25.245 84.24 25.515 ;
     RECT  2.16 25.785 84.24 26.055 ;
     RECT  2.16 26.325 84.24 26.595 ;
     RECT  2.16 26.865 84.24 27.135 ;
     RECT  2.16 27.405 84.24 27.675 ;
     RECT  2.16 27.945 84.24 28.215 ;
     RECT  2.16 28.485 84.24 28.755 ;
     RECT  2.16 29.025 84.24 29.295 ;
     RECT  2.16 29.565 84.24 29.835 ;
     RECT  2.16 30.105 84.24 30.375 ;
     RECT  2.16 30.645 84.24 30.915 ;
     RECT  2.16 31.185 84.24 31.455 ;
     RECT  2.16 31.725 84.24 31.995 ;
     RECT  2.16 32.265 84.24 32.535 ;
     RECT  2.16 32.805 84.24 33.075 ;
     RECT  2.16 33.345 84.24 33.615 ;
     RECT  2.16 33.885 84.24 34.155 ;
     RECT  2.16 34.425 84.24 34.695 ;
     RECT  2.16 34.965 84.24 35.235 ;
     RECT  2.16 35.505 84.24 35.775 ;
     RECT  2.16 36.045 84.24 36.315 ;
     RECT  2.16 36.585 84.24 36.855 ;
     RECT  2.16 37.125 84.24 37.395 ;
     RECT  2.16 37.665 84.24 37.935 ;
     RECT  2.16 38.205 84.24 38.475 ;
     RECT  2.16 38.745 84.24 39.015 ;
     RECT  2.16 39.285 84.24 39.555 ;
     RECT  2.16 39.825 84.24 40.095 ;
     RECT  2.16 40.365 84.24 40.635 ;
     RECT  2.16 40.905 84.24 41.175 ;
     RECT  2.16 41.445 84.24 41.715 ;
     RECT  2.16 41.985 84.24 42.255 ;
     RECT  2.16 42.525 84.24 42.795 ;
     RECT  2.16 43.065 84.24 43.335 ;
     RECT  2.16 43.605 84.24 43.875 ;
     RECT  2.16 44.145 84.24 44.415 ;
     RECT  2.16 44.685 84.24 44.955 ;
     RECT  2.16 45.225 84.24 45.495 ;
     RECT  2.16 45.765 84.24 46.035 ;
     RECT  2.16 46.305 84.24 46.575 ;
     RECT  2.16 46.845 84.24 47.115 ;
     RECT  2.16 47.385 84.24 47.655 ;
     RECT  2.16 47.925 84.24 48.195 ;
     RECT  2.16 48.465 84.24 48.735 ;
     RECT  2.16 49.005 84.24 49.275 ;
     RECT  2.16 49.545 84.24 49.815 ;
     RECT  2.16 50.085 84.24 50.355 ;
     RECT  2.16 50.625 84.24 50.895 ;
     RECT  2.16 51.165 84.24 51.435 ;
     RECT  2.16 51.705 84.24 51.975 ;
     RECT  2.16 52.245 84.24 52.515 ;
     RECT  2.16 52.785 84.24 53.055 ;
     RECT  2.16 53.325 84.24 53.595 ;
     RECT  2.16 53.865 84.24 54.135 ;
     RECT  2.16 54.405 84.24 54.675 ;
     RECT  2.16 54.945 84.24 55.215 ;
     RECT  2.16 55.485 84.24 55.755 ;
     RECT  2.16 56.025 84.24 56.295 ;
     RECT  2.16 56.565 84.24 56.835 ;
     RECT  2.16 57.105 84.24 57.375 ;
     RECT  2.16 57.645 84.24 57.915 ;
     RECT  2.16 58.185 84.24 58.455 ;
     RECT  2.16 58.725 84.24 58.995 ;
     RECT  2.16 59.265 84.24 59.535 ;
     RECT  2.16 59.805 84.24 60.075 ;
     RECT  2.16 60.345 84.24 60.615 ;
     RECT  2.16 60.885 84.24 61.155 ;
     RECT  2.16 61.425 84.24 61.695 ;
     RECT  2.16 61.965 84.24 62.235 ;
     RECT  2.16 62.505 84.24 62.775 ;
     RECT  2.16 63.045 84.24 63.315 ;
     RECT  2.16 63.585 84.24 63.855 ;
     RECT  2.16 64.125 84.24 64.395 ;
     RECT  2.16 64.665 84.24 64.935 ;
     RECT  2.16 65.205 84.24 65.475 ;
     RECT  2.16 65.745 84.24 66.015 ;
     RECT  2.16 66.285 84.24 66.555 ;
     RECT  2.16 66.825 84.24 67.095 ;
     RECT  2.16 67.365 84.24 67.635 ;
     RECT  2.16 67.905 84.24 68.175 ;
     RECT  2.16 68.445 84.24 68.715 ;
     RECT  2.16 68.985 84.24 69.255 ;
     RECT  2.16 69.525 84.24 69.795 ;
     RECT  2.16 70.065 84.24 70.335 ;
     RECT  2.16 70.605 84.24 70.875 ;
     RECT  2.16 71.145 84.24 71.415 ;
     RECT  2.16 71.685 84.24 71.955 ;
     RECT  2.16 72.225 84.24 72.495 ;
     RECT  2.16 72.765 84.24 73.035 ;
     RECT  2.16 73.305 84.24 73.575 ;
     RECT  2.16 73.845 84.24 74.115 ;
     RECT  2.16 74.385 84.24 74.655 ;
     RECT  2.16 74.925 84.24 75.195 ;
     RECT  2.16 75.465 84.24 75.6 ;
    LAYER RVTP ;
     RECT  2.16 2.295 84.24 2.565 ;
     RECT  2.16 2.835 84.24 3.105 ;
     RECT  2.16 3.375 84.24 3.645 ;
     RECT  2.16 3.915 84.24 4.185 ;
     RECT  2.16 4.455 84.24 4.725 ;
     RECT  2.16 4.995 84.24 5.265 ;
     RECT  2.16 5.535 84.24 5.805 ;
     RECT  2.16 6.075 84.24 6.345 ;
     RECT  2.16 6.615 84.24 6.885 ;
     RECT  2.16 7.155 84.24 7.425 ;
     RECT  2.16 7.695 84.24 7.965 ;
     RECT  2.16 8.235 84.24 8.505 ;
     RECT  2.16 8.775 84.24 9.045 ;
     RECT  2.16 9.315 84.24 9.585 ;
     RECT  2.16 9.855 84.24 10.125 ;
     RECT  2.16 10.395 84.24 10.665 ;
     RECT  2.16 10.935 84.24 11.205 ;
     RECT  2.16 11.475 84.24 11.745 ;
     RECT  2.16 12.015 84.24 12.285 ;
     RECT  2.16 12.555 84.24 12.825 ;
     RECT  2.16 13.095 84.24 13.365 ;
     RECT  2.16 13.635 84.24 13.905 ;
     RECT  2.16 14.175 84.24 14.445 ;
     RECT  2.16 14.715 84.24 14.985 ;
     RECT  2.16 15.255 84.24 15.525 ;
     RECT  2.16 15.795 84.24 16.065 ;
     RECT  2.16 16.335 84.24 16.605 ;
     RECT  2.16 16.875 84.24 17.145 ;
     RECT  2.16 17.415 84.24 17.685 ;
     RECT  2.16 17.955 84.24 18.225 ;
     RECT  2.16 18.495 84.24 18.765 ;
     RECT  2.16 19.035 84.24 19.305 ;
     RECT  2.16 19.575 84.24 19.845 ;
     RECT  2.16 20.115 84.24 20.385 ;
     RECT  2.16 20.655 84.24 20.925 ;
     RECT  2.16 21.195 84.24 21.465 ;
     RECT  2.16 21.735 84.24 22.005 ;
     RECT  2.16 22.275 84.24 22.545 ;
     RECT  2.16 22.815 84.24 23.085 ;
     RECT  2.16 23.355 84.24 23.625 ;
     RECT  2.16 23.895 84.24 24.165 ;
     RECT  2.16 24.435 84.24 24.705 ;
     RECT  2.16 24.975 84.24 25.245 ;
     RECT  2.16 25.515 84.24 25.785 ;
     RECT  2.16 26.055 84.24 26.325 ;
     RECT  2.16 26.595 84.24 26.865 ;
     RECT  2.16 27.135 84.24 27.405 ;
     RECT  2.16 27.675 84.24 27.945 ;
     RECT  2.16 28.215 84.24 28.485 ;
     RECT  2.16 28.755 84.24 29.025 ;
     RECT  2.16 29.295 84.24 29.565 ;
     RECT  2.16 29.835 84.24 30.105 ;
     RECT  2.16 30.375 84.24 30.645 ;
     RECT  2.16 30.915 84.24 31.185 ;
     RECT  2.16 31.455 84.24 31.725 ;
     RECT  2.16 31.995 84.24 32.265 ;
     RECT  2.16 32.535 84.24 32.805 ;
     RECT  2.16 33.075 84.24 33.345 ;
     RECT  2.16 33.615 84.24 33.885 ;
     RECT  2.16 34.155 84.24 34.425 ;
     RECT  2.16 34.695 84.24 34.965 ;
     RECT  2.16 35.235 84.24 35.505 ;
     RECT  2.16 35.775 84.24 36.045 ;
     RECT  2.16 36.315 84.24 36.585 ;
     RECT  2.16 36.855 84.24 37.125 ;
     RECT  2.16 37.395 84.24 37.665 ;
     RECT  2.16 37.935 84.24 38.205 ;
     RECT  2.16 38.475 84.24 38.745 ;
     RECT  2.16 39.015 84.24 39.285 ;
     RECT  2.16 39.555 84.24 39.825 ;
     RECT  2.16 40.095 84.24 40.365 ;
     RECT  2.16 40.635 84.24 40.905 ;
     RECT  2.16 41.175 84.24 41.445 ;
     RECT  2.16 41.715 84.24 41.985 ;
     RECT  2.16 42.255 84.24 42.525 ;
     RECT  2.16 42.795 84.24 43.065 ;
     RECT  2.16 43.335 84.24 43.605 ;
     RECT  2.16 43.875 84.24 44.145 ;
     RECT  2.16 44.415 84.24 44.685 ;
     RECT  2.16 44.955 84.24 45.225 ;
     RECT  2.16 45.495 84.24 45.765 ;
     RECT  2.16 46.035 84.24 46.305 ;
     RECT  2.16 46.575 84.24 46.845 ;
     RECT  2.16 47.115 84.24 47.385 ;
     RECT  2.16 47.655 84.24 47.925 ;
     RECT  2.16 48.195 84.24 48.465 ;
     RECT  2.16 48.735 84.24 49.005 ;
     RECT  2.16 49.275 84.24 49.545 ;
     RECT  2.16 49.815 84.24 50.085 ;
     RECT  2.16 50.355 84.24 50.625 ;
     RECT  2.16 50.895 84.24 51.165 ;
     RECT  2.16 51.435 84.24 51.705 ;
     RECT  2.16 51.975 84.24 52.245 ;
     RECT  2.16 52.515 84.24 52.785 ;
     RECT  2.16 53.055 84.24 53.325 ;
     RECT  2.16 53.595 84.24 53.865 ;
     RECT  2.16 54.135 84.24 54.405 ;
     RECT  2.16 54.675 84.24 54.945 ;
     RECT  2.16 55.215 84.24 55.485 ;
     RECT  2.16 55.755 84.24 56.025 ;
     RECT  2.16 56.295 84.24 56.565 ;
     RECT  2.16 56.835 84.24 57.105 ;
     RECT  2.16 57.375 84.24 57.645 ;
     RECT  2.16 57.915 84.24 58.185 ;
     RECT  2.16 58.455 84.24 58.725 ;
     RECT  2.16 58.995 84.24 59.265 ;
     RECT  2.16 59.535 84.24 59.805 ;
     RECT  2.16 60.075 84.24 60.345 ;
     RECT  2.16 60.615 84.24 60.885 ;
     RECT  2.16 61.155 84.24 61.425 ;
     RECT  2.16 61.695 84.24 61.965 ;
     RECT  2.16 62.235 84.24 62.505 ;
     RECT  2.16 62.775 84.24 63.045 ;
     RECT  2.16 63.315 84.24 63.585 ;
     RECT  2.16 63.855 84.24 64.125 ;
     RECT  2.16 64.395 84.24 64.665 ;
     RECT  2.16 64.935 84.24 65.205 ;
     RECT  2.16 65.475 84.24 65.745 ;
     RECT  2.16 66.015 84.24 66.285 ;
     RECT  2.16 66.555 84.24 66.825 ;
     RECT  2.16 67.095 84.24 67.365 ;
     RECT  2.16 67.635 84.24 67.905 ;
     RECT  2.16 68.175 84.24 68.445 ;
     RECT  2.16 68.715 84.24 68.985 ;
     RECT  2.16 69.255 84.24 69.525 ;
     RECT  2.16 69.795 84.24 70.065 ;
     RECT  2.16 70.335 84.24 70.605 ;
     RECT  2.16 70.875 84.24 71.145 ;
     RECT  2.16 71.415 84.24 71.685 ;
     RECT  2.16 71.955 84.24 72.225 ;
     RECT  2.16 72.495 84.24 72.765 ;
     RECT  2.16 73.035 84.24 73.305 ;
     RECT  2.16 73.575 84.24 73.845 ;
     RECT  2.16 74.115 84.24 74.385 ;
     RECT  2.16 74.655 84.24 74.925 ;
     RECT  2.16 75.195 84.24 75.465 ;
    LAYER M1 ;
     RECT  2.16 2.151 84.24 75.609 ;
    LAYER M2 ;
     RECT  0.031 41.571 0.067 41.589 ;
     RECT  0.031 44.352 0.067 44.37 ;
     RECT  0.067 41.571 0.103 41.94 ;
     RECT  0.067 44.352 0.103 44.64 ;
     RECT  0.103 35.856 0.139 35.874 ;
     RECT  0.103 37.332 0.139 37.926 ;
     RECT  0.103 40.338 0.139 41.94 ;
     RECT  0.139 35.28 0.175 36.459 ;
     RECT  0.139 37.332 0.175 38.034 ;
     RECT  0.139 43.11 0.175 43.128 ;
     RECT  0.175 35.172 0.211 38.034 ;
     RECT  0.139 38.826 0.211 41.94 ;
     RECT  0.175 43.11 0.211 43.164 ;
     RECT  0.211 34.902 0.247 41.94 ;
     RECT  0.247 34.74 0.283 42.012 ;
     RECT  0.211 42.876 0.319 43.164 ;
     RECT  0.103 44.082 0.319 44.64 ;
     RECT  0.283 34.74 0.355 42.129 ;
     RECT  0.319 42.876 0.355 44.64 ;
     RECT  0.355 34.668 0.563 44.64 ;
     RECT  0.563 42.111 0.599 44.64 ;
     RECT  0.563 34.668 2.16 41.238 ;
     RECT  0.599 42.264 2.16 44.64 ;
     RECT  2.16 2.151 26.851 75.609 ;
     RECT  26.851 2.151 29.111 75.654 ;
     RECT  29.111 2.151 84.24 75.609 ;
     RECT  84.24 39.492 85.487 39.51 ;
    LAYER M3 ;
     RECT  43.236 0.523 43.254 2.143 ;
     RECT  42.915 2.143 43.254 2.191 ;
     RECT  42.915 2.191 44.118 2.291 ;
     RECT  44.1 2.291 44.118 2.371 ;
     RECT  2.415 2.143 2.505 2.413 ;
     RECT  5.115 2.143 5.205 2.413 ;
     RECT  7.815 2.143 7.905 2.413 ;
     RECT  10.515 2.143 10.605 2.413 ;
     RECT  13.215 2.143 13.305 2.413 ;
     RECT  15.915 2.143 16.005 2.413 ;
     RECT  18.615 2.143 18.705 2.413 ;
     RECT  21.315 2.143 21.405 2.413 ;
     RECT  24.015 2.143 24.105 2.413 ;
     RECT  26.715 2.143 26.805 2.413 ;
     RECT  29.415 2.143 29.505 2.413 ;
     RECT  32.115 2.143 32.205 2.413 ;
     RECT  34.815 2.143 34.905 2.413 ;
     RECT  37.515 2.143 37.605 2.413 ;
     RECT  40.215 2.143 40.305 2.413 ;
     RECT  45.615 2.143 45.705 2.413 ;
     RECT  48.315 2.143 48.405 2.413 ;
     RECT  51.015 2.143 51.105 2.413 ;
     RECT  53.715 2.143 53.805 2.413 ;
     RECT  56.415 2.143 56.505 2.413 ;
     RECT  59.115 2.143 59.205 2.413 ;
     RECT  61.815 2.143 61.905 2.413 ;
     RECT  64.515 2.143 64.605 2.413 ;
     RECT  67.215 2.143 67.305 2.413 ;
     RECT  69.915 2.143 70.005 2.413 ;
     RECT  72.615 2.143 72.705 2.413 ;
     RECT  75.315 2.143 75.405 2.413 ;
     RECT  78.015 2.143 78.105 2.413 ;
     RECT  80.715 2.143 80.805 2.413 ;
     RECT  83.415 2.143 83.505 2.413 ;
     RECT  42.915 2.291 43.362 3.271 ;
     RECT  44.1 2.371 44.19 3.271 ;
     RECT  42.915 3.271 44.19 3.451 ;
     RECT  42.915 3.451 44.514 3.713 ;
     RECT  42.915 3.713 43.794 16.537 ;
     RECT  34.815 2.413 35.097 16.573 ;
     RECT  37.515 2.413 37.797 16.573 ;
     RECT  34.815 16.573 35.442 16.609 ;
     RECT  40.215 2.413 40.497 16.609 ;
     RECT  37.515 16.573 38.466 16.681 ;
     RECT  40.14 16.609 40.497 16.681 ;
     RECT  42.915 16.537 44.01 16.681 ;
     RECT  41.652 16.411 41.67 16.771 ;
     RECT  42.915 16.681 44.514 16.771 ;
     RECT  41.652 16.771 44.514 16.843 ;
     RECT  34.56 16.609 35.442 16.879 ;
     RECT  36.972 16.681 38.466 16.915 ;
     RECT  34.2 16.879 35.442 16.951 ;
     RECT  36.54 16.915 38.466 16.951 ;
     RECT  39.42 16.681 40.497 16.951 ;
     RECT  41.22 16.843 44.514 16.951 ;
     RECT  45.615 2.413 45.897 16.951 ;
     RECT  34.2 16.951 35.514 17.035 ;
     RECT  33.588 17.035 35.514 17.041 ;
     RECT  36.468 16.951 44.514 17.041 ;
     RECT  32.115 2.413 32.397 17.077 ;
     RECT  33.588 17.041 44.514 17.077 ;
     RECT  45.612 16.951 45.897 17.077 ;
     RECT  51.015 2.413 51.297 17.077 ;
     RECT  49.608 17.077 49.698 17.149 ;
     RECT  48.315 2.413 48.597 17.185 ;
     RECT  49.536 17.149 49.698 17.185 ;
     RECT  51.015 17.077 51.894 17.185 ;
     RECT  32.115 17.077 44.514 17.221 ;
     RECT  45.504 17.077 46.206 17.221 ;
     RECT  47.052 17.077 47.07 17.221 ;
     RECT  48.276 17.185 48.597 17.221 ;
     RECT  53.715 2.413 53.997 17.221 ;
     RECT  32.115 17.221 46.206 17.311 ;
     RECT  47.052 17.221 48.597 17.311 ;
     RECT  49.536 17.185 49.914 17.311 ;
     RECT  51.015 17.185 52.002 17.311 ;
     RECT  32.115 17.311 48.597 17.323 ;
     RECT  49.428 17.311 52.002 17.323 ;
     RECT  32.115 17.323 52.002 17.455 ;
     RECT  31.248 17.185 31.266 17.491 ;
     RECT  32.115 17.455 52.218 17.491 ;
     RECT  31.032 17.491 31.266 17.581 ;
     RECT  32.04 17.491 52.47 17.581 ;
     RECT  53.604 17.221 53.997 17.581 ;
     RECT  31.032 17.581 53.997 17.689 ;
     RECT  31.032 17.689 54.126 17.761 ;
     RECT  55.368 17.689 55.386 17.761 ;
     RECT  30.852 17.761 54.45 17.845 ;
     RECT  55.296 17.761 55.386 17.845 ;
     RECT  29.415 2.413 29.697 17.995 ;
     RECT  30.852 17.845 55.386 17.995 ;
     RECT  29.415 17.995 55.386 18.031 ;
     RECT  56.415 2.413 56.697 18.301 ;
     RECT  29.415 18.031 55.674 18.427 ;
     RECT  56.415 18.301 57.114 18.427 ;
     RECT  29.415 18.427 57.114 18.499 ;
     RECT  29.415 18.499 57.15 18.571 ;
     RECT  29.415 18.571 57.618 19.075 ;
     RECT  29.415 19.075 57.906 19.201 ;
     RECT  29.415 19.201 58.014 19.499 ;
     RECT  50.4 19.499 58.014 19.543 ;
     RECT  50.4 19.543 58.122 19.651 ;
     RECT  59.115 2.413 59.397 19.651 ;
     RECT  26.715 2.413 26.997 19.741 ;
     RECT  26.568 19.741 26.997 19.777 ;
     RECT  26.568 19.777 27.486 19.813 ;
     RECT  26.496 19.813 27.486 20.155 ;
     RECT  28.44 20.119 28.458 20.155 ;
     RECT  29.415 19.499 49.482 20.155 ;
     RECT  50.4 19.651 59.397 20.317 ;
     RECT  26.496 20.155 49.482 20.461 ;
     RECT  26.46 20.461 49.482 20.623 ;
     RECT  50.256 20.317 59.397 20.623 ;
     RECT  26.46 20.623 59.397 20.957 ;
     RECT  26.46 20.957 54.882 21.569 ;
     RECT  55.8 20.957 59.397 21.811 ;
     RECT  26.46 21.569 30.258 21.937 ;
     RECT  30.996 21.569 54.882 21.937 ;
     RECT  55.8 21.811 59.922 21.937 ;
     RECT  30.996 21.937 59.922 22.279 ;
     RECT  30.996 22.279 59.994 22.307 ;
     RECT  26.064 21.937 30.258 22.315 ;
     RECT  25.992 22.315 30.258 22.351 ;
     RECT  30.996 22.307 47.286 22.351 ;
     RECT  48.096 22.307 59.994 22.469 ;
     RECT  25.992 22.351 47.286 22.541 ;
     RECT  25.992 22.541 46.998 22.711 ;
     RECT  48.096 22.469 59.85 22.739 ;
     RECT  48.096 22.739 59.742 22.811 ;
     RECT  25.956 22.711 46.998 23.395 ;
     RECT  24.015 2.413 24.297 23.431 ;
     RECT  25.956 23.395 47.106 23.431 ;
     RECT  48.096 22.811 59.634 23.431 ;
     RECT  25.956 23.431 59.634 23.693 ;
     RECT  25.956 23.693 59.49 23.701 ;
     RECT  25.776 23.701 59.49 23.927 ;
     RECT  25.776 23.927 47.034 24.475 ;
     RECT  47.772 23.927 59.49 24.475 ;
     RECT  25.668 24.475 47.034 24.745 ;
     RECT  47.772 24.475 59.958 24.745 ;
     RECT  25.668 24.745 59.958 24.859 ;
     RECT  25.344 24.859 59.958 25.043 ;
     RECT  24.015 23.431 24.534 25.285 ;
     RECT  25.344 25.043 57.726 25.285 ;
     RECT  23.076 23.323 23.094 25.717 ;
     RECT  24.015 25.285 57.726 25.717 ;
     RECT  58.572 25.043 59.958 25.861 ;
     RECT  58.572 25.861 60.39 25.979 ;
     RECT  23.076 25.717 57.726 26.015 ;
     RECT  25.056 26.015 57.726 26.131 ;
     RECT  58.572 25.979 59.958 26.131 ;
     RECT  17.316 26.731 17.334 26.789 ;
     RECT  25.056 26.131 59.958 26.797 ;
     RECT  25.056 26.797 60.138 26.825 ;
     RECT  18.615 2.413 18.897 26.941 ;
     RECT  38.808 26.825 60.138 26.941 ;
     RECT  38.808 26.941 60.426 27.059 ;
     RECT  18.288 26.941 18.897 27.118 ;
     RECT  21.315 2.413 21.597 27.139 ;
     RECT  18.396 27.118 18.897 27.211 ;
     RECT  21.096 27.139 21.597 27.211 ;
     RECT  23.076 26.015 24.297 27.211 ;
     RECT  20.448 27.211 24.297 27.301 ;
     RECT  44.82 27.059 60.426 27.401 ;
     RECT  18.396 27.211 19.242 27.445 ;
     RECT  20.232 27.301 24.297 27.445 ;
     RECT  25.056 26.825 37.998 27.571 ;
     RECT  18.396 27.445 24.297 27.607 ;
     RECT  25.056 27.571 38.034 27.607 ;
     RECT  18.396 27.607 38.034 27.643 ;
     RECT  38.808 27.059 44.046 27.643 ;
     RECT  15.915 2.413 16.197 27.715 ;
     RECT  16.992 27.751 17.01 27.869 ;
     RECT  18.396 27.643 44.046 27.905 ;
     RECT  15.516 27.715 16.197 27.985 ;
     RECT  13.215 2.413 13.497 28.021 ;
     RECT  15.372 27.985 16.197 28.021 ;
     RECT  17.1 27.985 17.226 28.021 ;
     RECT  18.396 27.905 38.394 28.021 ;
     RECT  15.3 28.021 16.197 28.027 ;
     RECT  13.215 28.021 14.022 28.147 ;
     RECT  14.832 28.027 16.197 28.147 ;
     RECT  13.215 28.147 16.197 28.219 ;
     RECT  39.24 27.905 44.046 28.219 ;
     RECT  13.215 28.219 16.254 28.255 ;
     RECT  39.24 28.219 44.19 28.255 ;
     RECT  45.216 27.401 60.354 28.255 ;
     RECT  11.808 28.255 11.826 28.291 ;
     RECT  13.104 28.255 16.254 28.291 ;
     RECT  39.24 28.255 60.354 28.291 ;
     RECT  39.24 28.291 60.57 28.381 ;
     RECT  39.24 28.381 60.93 28.445 ;
     RECT  12.96 28.291 16.254 28.453 ;
     RECT  39.708 28.445 60.93 28.481 ;
     RECT  39.708 28.481 47.538 28.553 ;
     RECT  10.515 2.413 10.797 28.561 ;
     RECT  11.808 28.291 11.97 28.561 ;
     RECT  12.96 28.453 16.326 28.651 ;
     RECT  17.1 28.021 38.394 28.651 ;
     RECT  39.708 28.553 47.502 28.679 ;
     RECT  12.96 28.651 38.394 28.723 ;
     RECT  12.924 28.723 38.394 28.789 ;
     RECT  12.924 28.789 38.862 28.829 ;
     RECT  10.515 28.561 11.97 28.831 ;
     RECT  8.928 28.831 9.45 28.949 ;
     RECT  8.928 28.949 9.162 28.985 ;
     RECT  10.224 28.831 12.078 28.985 ;
     RECT  10.515 28.985 12.078 29.083 ;
     RECT  12.924 28.829 38.394 29.083 ;
     RECT  48.315 28.481 60.93 29.255 ;
     RECT  48.315 29.255 60.39 29.363 ;
     RECT  48.315 29.363 51.75 29.371 ;
     RECT  48.132 29.371 51.75 29.489 ;
     RECT  48.132 29.489 51.714 29.633 ;
     RECT  39.708 28.679 47.322 29.641 ;
     RECT  10.515 29.083 38.394 29.875 ;
     RECT  39.24 29.641 47.322 29.875 ;
     RECT  48.132 29.633 51.678 29.875 ;
     RECT  10.515 29.875 51.678 29.939 ;
     RECT  47.304 29.939 51.678 30.029 ;
     RECT  8.928 28.985 8.946 30.139 ;
     RECT  10.515 29.939 46.422 30.145 ;
     RECT  52.524 29.363 60.39 30.173 ;
     RECT  8.928 30.139 9.378 30.181 ;
     RECT  8.928 30.181 9.486 30.187 ;
     RECT  10.404 30.145 46.422 30.187 ;
     RECT  52.56 30.173 60.39 30.379 ;
     RECT  8.928 30.187 46.422 30.451 ;
     RECT  52.56 30.379 60.426 30.451 ;
     RECT  8.856 30.451 46.422 30.839 ;
     RECT  10.515 30.839 46.422 30.847 ;
     RECT  47.736 30.029 51.678 30.847 ;
     RECT  47.664 30.847 51.786 30.983 ;
     RECT  52.56 30.451 60.75 30.991 ;
     RECT  47.664 30.983 51.678 31.261 ;
     RECT  52.56 30.991 60.858 31.351 ;
     RECT  7.815 2.413 8.097 31.495 ;
     RECT  8.856 30.839 9.774 31.495 ;
     RECT  52.452 31.351 60.858 31.495 ;
     RECT  52.452 31.495 60.966 31.531 ;
     RECT  61.815 2.413 62.097 31.531 ;
     RECT  7.815 31.495 9.774 31.771 ;
     RECT  10.515 30.847 46.746 31.771 ;
     RECT  7.815 31.771 46.746 31.801 ;
     RECT  7.815 31.801 46.854 32.027 ;
     RECT  17.748 32.027 46.854 32.071 ;
     RECT  47.592 31.261 51.678 32.071 ;
     RECT  17.748 32.071 51.678 32.197 ;
     RECT  52.452 31.531 62.097 32.197 ;
     RECT  17.748 32.197 62.19 32.261 ;
     RECT  61.815 32.261 62.19 32.285 ;
     RECT  7.815 32.027 17.01 32.467 ;
     RECT  7.452 32.467 17.01 32.809 ;
     RECT  17.748 32.261 60.966 32.809 ;
     RECT  7.452 32.809 60.966 33.067 ;
     RECT  6.984 33.067 60.966 33.421 ;
     RECT  61.815 32.285 62.097 33.421 ;
     RECT  6.984 33.421 62.097 33.643 ;
     RECT  6.804 33.643 62.097 33.655 ;
     RECT  5.115 2.413 5.397 33.691 ;
     RECT  6.66 33.655 62.097 33.691 ;
     RECT  5.115 33.691 62.097 34.349 ;
     RECT  5.115 34.349 60.93 34.429 ;
     RECT  2.415 2.413 2.697 34.465 ;
     RECT  4.392 34.429 60.93 34.699 ;
     RECT  0.36 34.663 0.378 34.735 ;
     RECT  2.415 34.465 2.97 34.771 ;
     RECT  3.96 34.699 60.93 34.771 ;
     RECT  0.252 34.735 0.378 34.897 ;
     RECT  0.216 34.897 0.378 35.005 ;
     RECT  0.216 35.005 0.558 35.167 ;
     RECT  61.815 34.349 62.097 35.227 ;
     RECT  0.18 35.167 0.558 35.275 ;
     RECT  2.415 34.771 60.93 35.275 ;
     RECT  61.74 35.227 62.097 35.275 ;
     RECT  2.415 35.275 62.097 35.419 ;
     RECT  2.304 35.419 62.097 35.429 ;
     RECT  47.628 35.429 62.097 35.453 ;
     RECT  2.304 35.429 46.89 35.549 ;
     RECT  0.144 35.275 0.558 35.851 ;
     RECT  47.628 35.453 60.93 35.879 ;
     RECT  2.304 35.549 38.07 36.013 ;
     RECT  2.268 36.013 38.07 36.173 ;
     RECT  38.808 35.549 46.89 36.319 ;
     RECT  47.628 35.879 60.894 36.319 ;
     RECT  2.304 36.173 38.07 36.391 ;
     RECT  38.808 36.319 60.894 36.391 ;
     RECT  2.304 36.391 60.894 36.419 ;
     RECT  52.488 36.419 60.894 36.509 ;
     RECT  52.56 36.509 60.894 36.661 ;
     RECT  61.815 35.453 62.097 36.661 ;
     RECT  52.56 36.661 62.097 36.779 ;
     RECT  0.108 35.851 0.558 37.099 ;
     RECT  2.304 36.419 51.678 37.165 ;
     RECT  2.304 37.165 51.786 37.291 ;
     RECT  52.56 36.779 60.894 37.291 ;
     RECT  2.304 37.291 60.894 37.319 ;
     RECT  0.108 37.099 0.666 37.435 ;
     RECT  64.515 2.413 64.797 37.741 ;
     RECT  0.108 37.435 1.134 37.805 ;
     RECT  0.108 37.805 0.594 37.949 ;
     RECT  2.304 37.319 60.498 38.129 ;
     RECT  64.404 37.741 64.797 38.129 ;
     RECT  80.715 2.413 80.997 38.137 ;
     RECT  2.304 38.129 60.246 38.165 ;
     RECT  2.304 38.165 59.598 38.201 ;
     RECT  86.292 38.347 86.31 38.477 ;
     RECT  32.04 38.201 59.397 38.717 ;
     RECT  57.924 38.717 59.397 38.741 ;
     RECT  32.04 38.717 56.826 38.813 ;
     RECT  2.304 38.201 31.158 38.971 ;
     RECT  58.104 38.741 59.397 38.975 ;
     RECT  58.644 38.975 59.397 39.083 ;
     RECT  80.172 38.137 80.997 39.209 ;
     RECT  2.304 38.971 31.302 39.355 ;
     RECT  32.04 38.813 56.754 39.355 ;
     RECT  2.304 39.355 56.754 39.361 ;
     RECT  81.864 39.289 81.882 39.479 ;
     RECT  85.464 39.355 85.482 39.515 ;
     RECT  0.144 37.949 0.594 39.559 ;
     RECT  2.232 39.361 56.754 39.587 ;
     RECT  2.232 39.587 49.95 39.623 ;
     RECT  81.72 39.559 81.738 39.659 ;
     RECT  50.724 39.587 56.754 39.749 ;
     RECT  32.004 39.623 49.95 39.785 ;
     RECT  50.724 39.749 56.697 39.785 ;
     RECT  53.715 39.785 56.697 39.821 ;
     RECT  0.144 39.559 1.206 39.857 ;
     RECT  56.052 39.821 56.697 39.857 ;
     RECT  32.004 39.785 49.878 39.893 ;
     RECT  53.715 39.821 55.314 40.055 ;
     RECT  53.715 40.055 55.17 40.127 ;
     RECT  53.715 40.127 54.882 40.163 ;
     RECT  0.144 39.857 0.666 40.315 ;
     RECT  2.232 39.623 31.158 40.411 ;
     RECT  32.004 39.893 49.554 40.411 ;
     RECT  50.724 39.785 52.974 40.433 ;
     RECT  50.724 40.433 52.434 40.469 ;
     RECT  2.232 40.411 49.554 40.507 ;
     RECT  0.108 40.315 0.666 40.514 ;
     RECT  50.724 40.469 51.858 40.909 ;
     RECT  1.728 40.507 49.554 41.107 ;
     RECT  50.652 40.909 51.858 41.207 ;
     RECT  1.728 41.107 49.59 41.251 ;
     RECT  50.688 41.207 51.858 41.251 ;
     RECT  50.688 41.251 52.074 41.369 ;
     RECT  50.724 41.369 52.074 41.405 ;
     RECT  52.056 41.405 52.074 41.441 ;
     RECT  50.724 41.405 51.297 41.549 ;
     RECT  0.108 40.514 0.594 41.566 ;
     RECT  1.728 41.251 49.914 41.611 ;
     RECT  0.036 41.566 0.594 42.134 ;
     RECT  1.728 41.611 49.95 42.151 ;
     RECT  53.715 40.163 53.997 42.667 ;
     RECT  51.015 41.549 51.297 42.691 ;
     RECT  53.28 42.667 53.997 42.719 ;
     RECT  1.728 42.151 50.274 43.025 ;
     RECT  51.015 42.691 52.002 43.259 ;
     RECT  1.764 43.025 50.274 43.411 ;
     RECT  51.015 43.259 51.297 43.411 ;
     RECT  0.036 42.134 0.558 43.637 ;
     RECT  1.764 43.411 51.297 43.835 ;
     RECT  0.036 43.637 0.27 44.177 ;
     RECT  2.016 43.835 51.297 44.213 ;
     RECT  2.088 44.213 51.297 44.339 ;
     RECT  0.036 44.177 0.09 44.375 ;
     RECT  2.088 44.339 2.79 44.447 ;
     RECT  2.415 44.447 2.79 44.609 ;
     RECT  0.072 44.375 0.09 44.645 ;
     RECT  3.6 44.339 51.297 44.951 ;
     RECT  3.996 44.951 51.297 46.337 ;
     RECT  2.415 44.609 2.697 46.345 ;
     RECT  3.996 46.337 41.634 46.499 ;
     RECT  2.415 46.345 3.078 46.651 ;
     RECT  2.415 46.651 3.222 46.777 ;
     RECT  3.996 46.499 24.678 46.777 ;
     RECT  25.452 46.499 41.634 47.075 ;
     RECT  25.56 47.075 41.634 47.083 ;
     RECT  42.372 46.337 51.297 47.083 ;
     RECT  2.415 46.777 24.678 47.731 ;
     RECT  25.56 47.083 51.297 48.001 ;
     RECT  2.415 47.731 24.714 48.427 ;
     RECT  25.524 48.001 51.297 48.427 ;
     RECT  2.415 48.427 51.297 48.767 ;
     RECT  2.415 48.767 25.686 49.549 ;
     RECT  26.496 48.767 51.297 49.549 ;
     RECT  2.415 49.549 51.297 49.811 ;
     RECT  2.415 49.811 32.634 50.585 ;
     RECT  7.488 50.585 32.634 50.629 ;
     RECT  33.408 49.811 51.297 50.629 ;
     RECT  7.488 50.629 51.297 50.729 ;
     RECT  2.415 50.585 6.714 51.197 ;
     RECT  4.284 51.197 6.714 51.475 ;
     RECT  7.596 50.729 51.297 51.475 ;
     RECT  4.284 51.475 51.297 51.629 ;
     RECT  2.415 51.197 3.51 52.519 ;
     RECT  4.536 51.629 51.297 52.519 ;
     RECT  2.415 52.519 51.297 52.709 ;
     RECT  2.415 52.709 22.842 53.671 ;
     RECT  23.58 52.709 51.297 53.671 ;
     RECT  2.415 53.671 51.297 54.605 ;
     RECT  2.415 54.605 3.51 55.139 ;
     RECT  4.356 54.605 51.297 55.139 ;
     RECT  2.415 55.139 3.402 55.175 ;
     RECT  4.356 55.139 33.498 55.175 ;
     RECT  4.356 55.175 6.246 55.409 ;
     RECT  4.356 55.409 6.066 55.445 ;
     RECT  6.984 55.175 33.498 55.445 ;
     RECT  4.68 55.445 6.066 55.853 ;
     RECT  18.396 55.445 33.498 55.985 ;
     RECT  20.844 55.985 33.498 56.029 ;
     RECT  34.236 55.139 51.297 56.029 ;
     RECT  6.984 55.445 17.442 56.371 ;
     RECT  18.396 55.985 20.07 56.371 ;
     RECT  6.984 56.371 20.07 56.443 ;
     RECT  6.948 56.443 20.07 56.461 ;
     RECT  4.752 55.853 6.066 56.641 ;
     RECT  6.804 56.461 20.07 56.641 ;
     RECT  4.752 56.641 20.07 56.911 ;
     RECT  20.844 56.029 51.297 56.911 ;
     RECT  4.752 56.911 51.297 57.019 ;
     RECT  4.68 57.019 51.297 57.197 ;
     RECT  6.804 57.197 51.297 57.569 ;
     RECT  4.68 57.197 6.066 57.581 ;
     RECT  2.415 55.175 2.97 58.019 ;
     RECT  4.032 57.991 4.05 58.075 ;
     RECT  3.888 58.075 4.05 58.109 ;
     RECT  3.888 58.109 3.906 58.115 ;
     RECT  4.896 57.581 6.066 58.261 ;
     RECT  6.804 57.569 17.55 58.261 ;
     RECT  4.896 58.261 17.55 58.531 ;
     RECT  18.504 57.569 51.297 58.531 ;
     RECT  4.896 58.531 51.297 58.919 ;
     RECT  4.896 58.919 50.202 59.069 ;
     RECT  5.115 59.069 50.202 59.189 ;
     RECT  5.115 59.189 6.138 59.225 ;
     RECT  6.912 59.189 49.77 59.261 ;
     RECT  5.115 59.225 6.066 59.459 ;
     RECT  5.115 59.459 5.922 59.495 ;
     RECT  6.984 59.261 49.77 59.495 ;
     RECT  7.74 59.495 49.77 60.035 ;
     RECT  7.74 60.035 47.466 60.305 ;
     RECT  48.204 60.035 49.77 60.763 ;
     RECT  48.204 60.763 49.878 60.809 ;
     RECT  48.204 60.809 48.597 61.079 ;
     RECT  49.356 60.809 49.878 61.102 ;
     RECT  7.815 60.305 47.466 61.151 ;
     RECT  7.815 61.151 47.322 61.349 ;
     RECT  7.815 61.349 47.178 61.619 ;
     RECT  7.815 61.619 46.818 61.655 ;
     RECT  22.644 61.655 46.818 61.889 ;
     RECT  22.644 61.889 46.782 61.949 ;
     RECT  22.644 61.949 41.31 62.069 ;
     RECT  48.276 61.079 48.597 62.395 ;
     RECT  49.356 61.102 49.77 62.395 ;
     RECT  48.276 62.395 49.77 62.465 ;
     RECT  7.815 61.655 21.834 62.581 ;
     RECT  22.644 62.069 41.238 62.581 ;
     RECT  49.356 62.465 49.77 62.581 ;
     RECT  7.815 62.581 41.238 62.815 ;
     RECT  42.048 61.949 46.782 62.815 ;
     RECT  7.815 62.815 46.782 63.509 ;
     RECT  22.32 63.509 46.782 63.779 ;
     RECT  22.32 63.779 41.094 63.821 ;
     RECT  7.815 63.509 21.597 64.049 ;
     RECT  9.108 64.049 21.597 64.397 ;
     RECT  22.32 63.821 41.058 64.463 ;
     RECT  9.288 64.397 21.597 64.561 ;
     RECT  22.32 64.463 38.862 64.561 ;
     RECT  9.288 64.561 38.862 64.589 ;
     RECT  9.324 64.589 38.862 64.661 ;
     RECT  9.324 64.661 38.682 65.273 ;
     RECT  9.324 65.273 38.646 65.939 ;
     RECT  9.324 65.939 9.342 65.975 ;
     RECT  10.296 65.939 38.646 66.515 ;
     RECT  12.78 66.515 38.646 66.623 ;
     RECT  12.78 66.623 14.454 66.659 ;
     RECT  10.296 66.515 12.042 66.785 ;
     RECT  10.44 66.785 10.797 66.821 ;
     RECT  15.264 66.623 38.646 66.821 ;
     RECT  49.356 62.581 50.13 66.893 ;
     RECT  15.804 66.821 38.646 66.901 ;
     RECT  11.592 66.785 12.042 67.019 ;
     RECT  15.804 66.901 38.79 67.019 ;
     RECT  11.592 67.019 11.754 67.055 ;
     RECT  15.804 67.019 38.682 67.055 ;
     RECT  12.816 66.659 13.497 67.325 ;
     RECT  15.804 67.055 16.434 67.397 ;
     RECT  12.96 67.325 13.497 67.559 ;
     RECT  15.804 67.397 16.197 67.579 ;
     RECT  13.032 67.559 13.497 67.711 ;
     RECT  15.264 67.579 16.197 67.711 ;
     RECT  13.032 67.711 16.197 67.829 ;
     RECT  13.032 67.829 14.958 67.865 ;
     RECT  13.215 67.865 14.346 68.099 ;
     RECT  13.215 68.099 14.13 68.135 ;
     RECT  17.424 67.055 38.682 68.251 ;
     RECT  39.6 64.463 41.058 68.251 ;
     RECT  17.424 68.251 41.058 68.395 ;
     RECT  17.352 68.395 41.058 68.639 ;
     RECT  48.276 62.465 48.597 68.647 ;
     RECT  49.356 66.893 49.77 68.647 ;
     RECT  20.412 68.639 41.058 68.945 ;
     RECT  17.352 68.639 19.494 68.957 ;
     RECT  20.592 68.945 41.058 68.957 ;
     RECT  42.048 63.779 46.782 69.025 ;
     RECT  21.168 68.957 41.058 69.053 ;
     RECT  17.352 68.957 19.026 69.215 ;
     RECT  21.168 69.053 25.254 69.215 ;
     RECT  48.276 68.647 49.77 69.421 ;
     RECT  18.072 69.215 19.026 69.449 ;
     RECT  21.168 69.215 22.662 69.449 ;
     RECT  18.072 69.449 18.897 69.485 ;
     RECT  42.048 69.025 46.962 69.485 ;
     RECT  26.136 69.053 41.058 69.601 ;
     RECT  47.772 69.421 49.77 69.601 ;
     RECT  21.168 69.449 22.158 69.791 ;
     RECT  23.58 69.215 25.254 69.791 ;
     RECT  47.772 69.601 50.202 69.863 ;
     RECT  26.136 69.601 41.13 69.871 ;
     RECT  42.048 69.485 44.694 69.871 ;
     RECT  45.615 69.485 46.962 69.961 ;
     RECT  25.776 69.871 44.694 69.989 ;
     RECT  45.615 69.961 47.034 69.997 ;
     RECT  47.772 69.863 50.166 69.997 ;
     RECT  21.315 69.791 22.158 70.025 ;
     RECT  25.776 69.989 38.79 70.025 ;
     RECT  23.58 69.791 25.002 70.069 ;
     RECT  45.615 69.997 50.166 70.109 ;
     RECT  23.364 70.069 25.002 70.295 ;
     RECT  47.772 70.109 50.166 70.295 ;
     RECT  47.844 70.295 50.166 70.529 ;
     RECT  47.916 70.529 50.166 70.601 ;
     RECT  48.315 70.601 50.166 70.637 ;
     RECT  39.6 69.989 44.694 70.645 ;
     RECT  45.615 70.109 46.89 70.645 ;
     RECT  25.992 70.025 38.79 70.673 ;
     RECT  21.315 70.025 21.87 70.799 ;
     RECT  39.6 70.645 46.89 70.799 ;
     RECT  21.315 70.799 21.654 70.835 ;
     RECT  48.315 70.637 49.734 70.871 ;
     RECT  23.436 70.295 25.002 70.891 ;
     RECT  25.992 70.673 38.358 70.891 ;
     RECT  23.436 70.891 38.358 70.907 ;
     RECT  48.315 70.871 49.23 70.979 ;
     RECT  23.436 70.907 37.797 71.069 ;
     RECT  22.572 70.951 22.59 71.105 ;
     RECT  24.015 71.069 37.797 71.105 ;
     RECT  46.692 70.799 46.89 71.105 ;
     RECT  39.6 70.799 45.897 71.177 ;
     RECT  48.315 70.979 48.978 71.177 ;
     RECT  24.015 71.105 25.002 71.213 ;
     RECT  46.8 71.105 46.89 71.213 ;
     RECT  39.6 71.177 44.586 71.221 ;
     RECT  22.86 71.221 23.094 71.339 ;
     RECT  22.86 71.339 22.878 71.375 ;
     RECT  25.74 71.105 37.797 71.375 ;
     RECT  39.24 71.221 44.586 71.375 ;
     RECT  46.8 71.213 46.818 71.411 ;
     RECT  39.24 71.375 44.334 71.483 ;
     RECT  39.24 71.483 41.634 71.609 ;
     RECT  42.516 71.483 44.334 71.645 ;
     RECT  39.24 71.609 41.454 71.681 ;
     RECT  25.776 71.375 37.797 71.707 ;
     RECT  39.24 71.681 41.31 71.753 ;
     RECT  25.776 71.707 37.818 71.789 ;
     RECT  25.776 71.789 37.797 71.879 ;
     RECT  39.24 71.753 39.258 71.879 ;
     RECT  42.915 71.645 44.334 71.915 ;
     RECT  42.915 71.915 43.506 71.951 ;
     RECT  24.015 71.213 24.822 72.185 ;
     RECT  44.316 71.915 44.334 72.185 ;
     RECT  40.215 71.753 41.31 72.329 ;
     RECT  42.915 71.951 43.197 72.391 ;
     RECT  44.424 72.301 44.442 72.455 ;
     RECT  26.244 71.879 37.797 72.563 ;
     RECT  40.215 72.329 41.058 72.599 ;
     RECT  26.244 72.563 36.666 72.689 ;
     RECT  42.732 72.391 43.197 72.725 ;
     RECT  26.676 72.689 36.666 72.833 ;
     RECT  38.772 72.391 38.79 72.833 ;
     RECT  27.864 72.833 36.666 73.103 ;
     RECT  26.676 72.833 26.997 73.849 ;
     RECT  28.044 73.103 36.666 73.849 ;
     RECT  26.676 73.849 36.666 74.191 ;
     RECT  37.515 72.563 37.797 74.191 ;
     RECT  42.915 72.725 43.197 74.317 ;
     RECT  42.915 74.317 43.218 74.579 ;
     RECT  26.676 74.191 37.797 74.615 ;
     RECT  26.676 74.615 36.702 74.659 ;
     RECT  26.388 74.659 36.702 75.119 ;
     RECT  26.388 75.119 36.558 75.155 ;
     RECT  26.568 75.155 36.558 75.191 ;
     RECT  2.415 58.019 2.697 75.347 ;
     RECT  5.115 59.495 5.397 75.347 ;
     RECT  7.815 64.049 8.097 75.347 ;
     RECT  10.515 66.821 10.797 75.347 ;
     RECT  13.215 68.135 13.497 75.347 ;
     RECT  15.915 67.829 16.197 75.347 ;
     RECT  18.615 69.485 18.897 75.347 ;
     RECT  21.315 70.835 21.597 75.347 ;
     RECT  24.015 72.185 24.297 75.347 ;
     RECT  37.515 74.615 37.797 75.347 ;
     RECT  40.215 72.599 40.497 75.347 ;
     RECT  42.915 74.579 43.197 75.347 ;
     RECT  45.615 71.177 45.897 75.347 ;
     RECT  48.315 71.177 48.597 75.347 ;
     RECT  51.015 58.919 51.297 75.347 ;
     RECT  53.715 42.719 53.997 75.347 ;
     RECT  56.415 39.857 56.697 75.347 ;
     RECT  59.115 39.083 59.397 75.347 ;
     RECT  61.815 36.779 62.097 75.347 ;
     RECT  64.515 38.129 64.797 75.347 ;
     RECT  67.215 2.413 67.497 75.347 ;
     RECT  69.915 2.413 70.197 75.347 ;
     RECT  72.615 2.413 72.897 75.347 ;
     RECT  75.315 2.413 75.597 75.347 ;
     RECT  78.015 2.413 78.297 75.347 ;
     RECT  80.715 39.209 80.997 75.347 ;
     RECT  83.415 2.413 83.697 75.347 ;
     RECT  26.715 75.191 36.558 75.389 ;
     RECT  26.715 75.389 30.114 75.425 ;
     RECT  30.852 75.389 36.09 75.461 ;
     RECT  31.104 75.461 36.09 75.497 ;
     RECT  2.415 75.347 2.505 75.617 ;
     RECT  5.115 75.347 5.205 75.617 ;
     RECT  7.815 75.347 7.905 75.617 ;
     RECT  10.515 75.347 10.605 75.617 ;
     RECT  13.215 75.347 13.305 75.617 ;
     RECT  15.915 75.347 16.005 75.617 ;
     RECT  18.615 75.347 18.705 75.617 ;
     RECT  21.315 75.347 21.405 75.617 ;
     RECT  24.015 75.347 24.105 75.617 ;
     RECT  26.715 75.425 26.874 75.617 ;
     RECT  31.104 75.497 35.874 75.617 ;
     RECT  37.515 75.347 37.605 75.617 ;
     RECT  40.215 75.347 40.305 75.617 ;
     RECT  42.915 75.347 43.146 75.617 ;
     RECT  45.615 75.347 45.705 75.617 ;
     RECT  48.315 75.347 48.405 75.617 ;
     RECT  51.015 75.347 51.105 75.617 ;
     RECT  53.715 75.347 53.805 75.617 ;
     RECT  56.415 75.347 56.505 75.617 ;
     RECT  59.115 75.347 59.205 75.617 ;
     RECT  61.815 75.347 61.905 75.617 ;
     RECT  64.515 75.347 64.605 75.617 ;
     RECT  67.215 75.347 67.305 75.617 ;
     RECT  69.915 75.347 70.005 75.617 ;
     RECT  72.615 75.347 72.705 75.617 ;
     RECT  75.315 75.347 75.405 75.617 ;
     RECT  78.015 75.347 78.105 75.617 ;
     RECT  80.715 75.347 80.805 75.617 ;
     RECT  83.415 75.347 83.505 75.617 ;
     RECT  26.856 75.617 26.874 75.659 ;
     RECT  31.104 75.617 34.47 75.821 ;
     RECT  43.128 75.617 43.146 75.821 ;
     RECT  27.612 75.425 30.114 76.397 ;
     RECT  31.104 75.821 32.85 76.445 ;
     RECT  27.612 76.397 27.846 76.925 ;
     RECT  31.104 76.445 31.122 76.925 ;
     RECT  31.968 76.445 32.85 76.925 ;
     RECT  27.828 76.925 27.846 76.973 ;
     RECT  31.968 76.925 31.986 76.973 ;
     RECT  28.62 76.397 29.322 77.275 ;
     RECT  34.2 75.821 34.47 77.309 ;
     RECT  34.272 77.309 34.47 77.357 ;
     RECT  35.46 75.617 35.874 77.405 ;
     RECT  28.62 77.275 29.898 77.453 ;
     RECT  34.272 77.357 34.434 77.453 ;
     RECT  34.272 77.453 34.29 77.549 ;
     RECT  28.62 77.453 29.322 77.597 ;
     RECT  35.46 77.405 35.73 77.597 ;
     RECT  28.692 77.597 29.322 77.645 ;
     RECT  30.456 77.515 30.474 77.645 ;
     RECT  32.832 76.925 32.85 77.645 ;
     RECT  35.46 77.597 35.478 77.645 ;
    LAYER M4 ;
     RECT  0.06 35.376 0.133 38.376 ;
     RECT  0.06 39.36 0.133 42.36 ;
     RECT  0.133 35.376 0.173 42.36 ;
     RECT  0.173 35.424 0.229 42.36 ;
     RECT  0.229 35.424 0.281 42.408 ;
     RECT  0.281 35.472 0.569 42.408 ;
     RECT  0.569 35.472 2.293 42.36 ;
     RECT  2.293 35.424 2.408 42.36 ;
     RECT  2.408 2.148 2.512 75.612 ;
     RECT  2.512 2.418 2.704 75.342 ;
     RECT  2.704 35.424 2.837 43.608 ;
     RECT  2.837 35.76 2.981 43.608 ;
     RECT  2.704 47.184 3.089 47.88 ;
     RECT  2.704 52.896 3.203 52.92 ;
     RECT  2.704 54.048 3.203 54.6 ;
     RECT  2.981 36.048 3.769 43.608 ;
     RECT  3.769 36.048 3.949 43.896 ;
     RECT  3.949 35.808 4.345 43.896 ;
     RECT  2.704 44.88 4.345 44.904 ;
     RECT  3.089 47.184 4.381 47.208 ;
     RECT  4.057 50.304 4.381 50.328 ;
     RECT  4.345 35.808 4.417 44.904 ;
     RECT  4.381 47.184 4.453 47.304 ;
     RECT  4.417 35.808 4.501 44.952 ;
     RECT  4.501 35.712 4.525 44.952 ;
     RECT  4.453 46.896 4.561 47.304 ;
     RECT  4.525 34.896 4.669 45 ;
     RECT  4.645 57.024 4.669 57.048 ;
     RECT  3.877 58.08 4.669 58.104 ;
     RECT  4.669 57.024 4.693 58.104 ;
     RECT  4.741 52.512 4.813 52.536 ;
     RECT  3.203 54.576 4.885 54.6 ;
     RECT  4.561 46.896 4.993 48.168 ;
     RECT  4.381 50.304 5.065 50.568 ;
     RECT  4.813 51.888 5.065 52.536 ;
     RECT  4.669 34.896 5.108 45.72 ;
     RECT  4.993 46.896 5.108 48.264 ;
     RECT  5.065 50.304 5.108 50.664 ;
     RECT  5.065 51.888 5.108 53.016 ;
     RECT  4.885 54.144 5.108 54.6 ;
     RECT  4.625 55.824 5.108 55.848 ;
     RECT  4.693 57.024 5.108 59.064 ;
     RECT  4.885 62.016 5.108 62.04 ;
     RECT  5.108 2.148 5.212 75.612 ;
     RECT  5.212 2.418 5.404 75.342 ;
     RECT  5.404 48.144 5.581 54.168 ;
     RECT  5.581 48.144 5.789 51.624 ;
     RECT  5.404 55.44 6.028 55.464 ;
     RECT  5.789 48.144 6.041 51.432 ;
     RECT  6.041 48.144 6.293 50.664 ;
     RECT  5.404 34.368 6.323 46.92 ;
     RECT  5.404 56.448 6.323 58.392 ;
     RECT  5.581 52.704 6.469 54.168 ;
     RECT  6.323 46.08 6.505 46.92 ;
     RECT  6.293 48.144 6.505 50.376 ;
     RECT  6.469 52.704 6.509 54.744 ;
     RECT  6.323 56.448 6.761 57.192 ;
     RECT  6.323 34.368 6.793 45 ;
     RECT  6.793 33.648 6.929 45 ;
     RECT  6.929 33.072 7.477 45 ;
     RECT  6.323 58.368 7.477 58.392 ;
     RECT  6.509 52.704 7.513 53.304 ;
     RECT  6.509 54.72 7.513 54.744 ;
     RECT  7.477 33.024 7.573 45 ;
     RECT  6.949 30.144 7.808 30.168 ;
     RECT  7.573 32.304 7.808 45 ;
     RECT  6.505 46.08 7.808 50.376 ;
     RECT  7.369 51.648 7.808 51.672 ;
     RECT  7.513 52.704 7.808 54.744 ;
     RECT  6.761 56.448 7.808 56.472 ;
     RECT  7.477 57.84 7.808 58.392 ;
     RECT  5.404 62.016 7.808 62.04 ;
     RECT  7.808 2.148 7.912 75.612 ;
     RECT  7.912 2.418 8.104 75.342 ;
     RECT  8.104 34.128 8.165 45.096 ;
     RECT  8.104 46.08 8.165 46.248 ;
     RECT  8.104 63.84 8.531 63.864 ;
     RECT  8.104 62.016 8.597 62.76 ;
     RECT  8.104 32.304 8.957 33.096 ;
     RECT  8.165 43.92 8.957 45.096 ;
     RECT  8.165 34.128 9.205 42.936 ;
     RECT  8.957 43.92 9.205 44.376 ;
     RECT  8.104 51.6 9.26 51.768 ;
     RECT  9.097 64.368 9.269 64.392 ;
     RECT  8.104 49.488 9.301 50.376 ;
     RECT  9.26 51.6 9.301 52.44 ;
     RECT  8.104 54.72 9.301 54.744 ;
     RECT  9.253 28.848 9.34 28.872 ;
     RECT  9.301 49.488 9.347 52.44 ;
     RECT  8.165 46.08 9.353 46.104 ;
     RECT  9.269 64.368 9.353 64.44 ;
     RECT  9.301 54.096 9.388 55.416 ;
     RECT  8.104 30.144 9.389 30.168 ;
     RECT  8.104 47.664 9.529 47.928 ;
     RECT  8.957 32.304 10.141 32.472 ;
     RECT  8.104 57.84 10.177 59.304 ;
     RECT  10.177 56.976 10.213 59.304 ;
     RECT  9.817 60.48 10.213 60.504 ;
     RECT  9.388 54.96 10.249 55.416 ;
     RECT  9.529 47.184 10.309 47.928 ;
     RECT  8.597 62.64 10.321 62.76 ;
     RECT  9.205 34.128 10.357 44.376 ;
     RECT  10.249 54.96 10.357 55.752 ;
     RECT  10.309 47.184 10.501 48.408 ;
     RECT  9.745 30.192 10.508 30.216 ;
     RECT  10.141 31.776 10.508 32.472 ;
     RECT  10.357 33.6 10.508 44.424 ;
     RECT  10.501 46.224 10.508 48.408 ;
     RECT  9.347 49.488 10.508 51.768 ;
     RECT  10.357 53.808 10.508 55.752 ;
     RECT  10.213 56.976 10.508 60.504 ;
     RECT  10.321 62.256 10.508 62.76 ;
     RECT  9.353 64.368 10.508 64.392 ;
     RECT  9.313 65.568 10.508 65.592 ;
     RECT  10.508 2.148 10.612 75.612 ;
     RECT  10.612 2.418 10.804 75.342 ;
     RECT  10.804 31.776 10.865 33.096 ;
     RECT  10.804 60 11.081 60.984 ;
     RECT  10.804 34.272 11.225 44.472 ;
     RECT  10.804 52.944 11.315 55.464 ;
     RECT  11.315 53.04 11.363 55.464 ;
     RECT  11.363 53.04 11.411 54.744 ;
     RECT  10.865 32.304 11.441 33.096 ;
     RECT  11.225 34.272 11.441 44.376 ;
     RECT  11.441 33.072 11.477 33.096 ;
     RECT  10.804 57.6 11.513 57.912 ;
     RECT  11.081 60.96 11.549 60.984 ;
     RECT  11.411 53.04 11.621 53.544 ;
     RECT  10.804 56.448 11.729 56.472 ;
     RECT  10.804 62.256 11.765 63.288 ;
     RECT  10.804 48.24 11.852 48.408 ;
     RECT  10.804 49.776 11.852 51.912 ;
     RECT  10.804 65.52 11.873 66.456 ;
     RECT  11.797 28.464 11.905 28.488 ;
     RECT  11.852 48.24 11.939 51.912 ;
     RECT  11.905 28.464 11.941 28.824 ;
     RECT  10.804 30.576 11.941 30.6 ;
     RECT  11.939 48.24 11.941 48.456 ;
     RECT  11.941 48 11.977 48.456 ;
     RECT  11.941 28.464 11.987 30.6 ;
     RECT  11.441 34.272 11.989 34.92 ;
     RECT  11.977 47.424 12.049 48.456 ;
     RECT  11.513 57.6 12.085 57.864 ;
     RECT  10.804 46.224 12.325 46.248 ;
     RECT  12.049 47.28 12.325 48.456 ;
     RECT  11.765 62.64 12.337 63.288 ;
     RECT  12.085 57.504 12.481 57.864 ;
     RECT  11.987 28.464 12.517 29.736 ;
     RECT  11.989 34.128 12.733 34.92 ;
     RECT  11.939 49.584 12.805 51.912 ;
     RECT  11.621 53.52 12.805 53.544 ;
     RECT  11.411 54.672 12.901 54.744 ;
     RECT  11.873 65.52 12.913 65.544 ;
     RECT  12.733 33.792 12.985 34.92 ;
     RECT  11.441 35.952 12.985 44.376 ;
     RECT  12.913 65.184 13.021 65.544 ;
     RECT  12.049 60.048 13.057 60.072 ;
     RECT  12.325 46.224 13.093 48.456 ;
     RECT  11.869 61.632 13.093 61.656 ;
     RECT  12.337 62.64 13.093 63.912 ;
     RECT  13.021 65.184 13.093 66.264 ;
     RECT  12.985 33.792 13.129 44.376 ;
     RECT  12.517 28.272 13.208 29.736 ;
     RECT  12.524 31.104 13.208 31.128 ;
     RECT  13.129 33.552 13.208 44.376 ;
     RECT  13.093 45.792 13.208 48.456 ;
     RECT  12.805 49.584 13.208 53.544 ;
     RECT  12.901 54.624 13.208 54.744 ;
     RECT  12.481 57.504 13.208 57.912 ;
     RECT  10.804 58.944 13.208 58.968 ;
     RECT  13.057 60.048 13.208 60.6 ;
     RECT  13.093 61.632 13.208 66.264 ;
     RECT  12.949 67.296 13.208 67.32 ;
     RECT  13.208 2.148 13.312 75.612 ;
     RECT  13.312 2.418 13.504 75.342 ;
     RECT  13.504 64.752 13.565 67.608 ;
     RECT  13.504 56.448 13.619 57.912 ;
     RECT  13.565 64.752 13.619 66.264 ;
     RECT  13.565 67.296 13.619 67.608 ;
     RECT  13.504 47.952 13.673 51.768 ;
     RECT  13.504 29.712 13.745 31.128 ;
     RECT  13.504 53.52 13.925 55.464 ;
     RECT  13.673 47.952 13.961 48.504 ;
     RECT  13.504 38.688 13.997 41.256 ;
     RECT  13.673 49.488 14.105 51.768 ;
     RECT  14.105 49.488 14.14 49.512 ;
     RECT  13.504 59.232 14.285 60.6 ;
     RECT  13.504 36.336 14.321 37.464 ;
     RECT  13.504 32.544 14.429 34.968 ;
     RECT  14.321 36.48 14.429 37.464 ;
     RECT  13.997 38.784 14.429 41.256 ;
     RECT  13.619 65.04 14.429 66.264 ;
     RECT  13.619 56.448 14.435 57.048 ;
     RECT  14.105 50.64 14.492 51.768 ;
     RECT  14.429 40.512 14.497 41.256 ;
     RECT  14.492 50.64 14.579 52.2 ;
     RECT  14.497 40.512 14.605 41.4 ;
     RECT  13.504 42.72 14.605 45.864 ;
     RECT  14.533 46.848 14.605 46.872 ;
     RECT  14.605 40.512 14.609 45.864 ;
     RECT  14.429 65.04 14.609 65.208 ;
     RECT  14.285 60.144 14.645 60.6 ;
     RECT  14.429 34.944 14.749 34.968 ;
     RECT  14.609 65.184 14.753 65.208 ;
     RECT  13.745 30.672 14.785 31.128 ;
     RECT  13.504 28.272 14.821 28.296 ;
     RECT  13.961 48.24 14.857 48.504 ;
     RECT  14.609 40.512 14.933 45.816 ;
     RECT  14.605 46.848 15.073 46.968 ;
     RECT  14.857 48.24 15.073 49.032 ;
     RECT  14.749 34.944 15.145 35.208 ;
     RECT  14.429 36.624 15.253 37.464 ;
     RECT  13.619 67.584 15.253 67.608 ;
     RECT  14.821 28.032 15.289 28.296 ;
     RECT  15.289 28.032 15.349 28.44 ;
     RECT  15.145 34.944 15.361 35.304 ;
     RECT  15.349 28.032 15.397 29.112 ;
     RECT  15.253 36.624 15.469 37.608 ;
     RECT  14.429 32.544 15.541 33.96 ;
     RECT  15.361 34.944 15.541 35.544 ;
     RECT  14.435 56.688 15.541 56.712 ;
     RECT  14.429 66.24 15.541 66.264 ;
     RECT  14.645 60.144 15.685 60.168 ;
     RECT  14.821 61.392 15.685 61.416 ;
     RECT  15.397 28.032 15.908 29.256 ;
     RECT  14.785 30.672 15.908 31.224 ;
     RECT  15.541 32.544 15.908 35.544 ;
     RECT  15.469 36.528 15.908 37.608 ;
     RECT  14.429 38.784 15.908 39.48 ;
     RECT  14.933 40.56 15.908 45.816 ;
     RECT  15.073 46.848 15.908 49.032 ;
     RECT  14.579 50.64 15.908 51.768 ;
     RECT  13.925 53.568 15.908 55.464 ;
     RECT  15.541 56.688 15.908 57.576 ;
     RECT  15.685 60.144 15.908 61.416 ;
     RECT  13.504 62.448 15.908 62.472 ;
     RECT  15.541 65.424 15.908 66.264 ;
     RECT  15.253 67.584 15.908 67.704 ;
     RECT  15.908 2.148 16.012 75.612 ;
     RECT  16.012 2.418 16.204 75.342 ;
     RECT  16.204 53.52 16.301 54.648 ;
     RECT  16.204 28.464 16.337 31.224 ;
     RECT  16.337 29.04 16.355 31.224 ;
     RECT  16.355 29.04 16.553 29.256 ;
     RECT  16.204 60.432 16.589 61.896 ;
     RECT  16.204 56.928 16.661 58.728 ;
     RECT  16.301 53.52 16.739 54.456 ;
     RECT  16.589 61.872 16.769 61.896 ;
     RECT  16.204 63.936 16.805 64.392 ;
     RECT  16.204 37.584 16.828 40.968 ;
     RECT  16.355 30.672 16.913 31.224 ;
     RECT  16.204 33.312 16.913 35.544 ;
     RECT  16.805 64.032 17.021 64.392 ;
     RECT  16.204 66.72 17.123 68.424 ;
     RECT  17.021 64.368 17.129 64.392 ;
     RECT  16.204 42.672 17.165 52.488 ;
     RECT  16.661 56.928 17.165 58.632 ;
     RECT  16.828 39.792 17.237 40.968 ;
     RECT  16.553 29.04 17.317 29.064 ;
     RECT  17.317 28.224 17.345 29.064 ;
     RECT  16.204 65.52 17.345 65.544 ;
     RECT  16.913 34.08 17.365 35.544 ;
     RECT  16.204 36.528 17.365 36.552 ;
     RECT  16.828 37.584 17.381 38.184 ;
     RECT  17.123 68.4 17.381 68.424 ;
     RECT  17.305 26.736 17.389 26.76 ;
     RECT  16.739 54.144 17.413 54.456 ;
     RECT  16.589 60.432 17.413 60.648 ;
     RECT  17.237 39.792 17.452 39.912 ;
     RECT  17.165 56.928 17.507 57.576 ;
     RECT  17.237 40.944 17.521 40.968 ;
     RECT  17.507 56.928 17.548 57.144 ;
     RECT  16.913 30.672 17.557 31.128 ;
     RECT  17.521 40.944 17.593 41.544 ;
     RECT  17.165 42.672 17.593 49.32 ;
     RECT  17.165 58.608 17.701 58.632 ;
     RECT  17.701 58.608 17.708 59.256 ;
     RECT  17.413 60.288 17.708 60.648 ;
     RECT  17.557 30.528 17.953 31.128 ;
     RECT  17.365 34.08 17.989 36.552 ;
     RECT  17.452 39.792 18.097 39.816 ;
     RECT  17.708 58.608 18.14 60.648 ;
     RECT  17.593 40.944 18.161 49.32 ;
     RECT  17.165 50.64 18.161 52.488 ;
     RECT  18.097 39.216 18.169 39.816 ;
     RECT  18.14 58.608 18.169 61.08 ;
     RECT  17.629 66.432 18.241 66.456 ;
     RECT  18.229 63.216 18.277 63.24 ;
     RECT  17.413 54.144 18.385 54.696 ;
     RECT  17.953 30.528 18.421 31.32 ;
     RECT  17.917 33.072 18.421 33.096 ;
     RECT  18.169 38.496 18.421 39.816 ;
     RECT  18.161 40.944 18.421 52.488 ;
     RECT  18.385 54.144 18.421 54.744 ;
     RECT  18.421 30.528 18.469 33.096 ;
     RECT  17.989 34.08 18.469 37.464 ;
     RECT  18.277 27.072 18.608 27.096 ;
     RECT  17.345 28.224 18.608 28.824 ;
     RECT  18.469 30.528 18.608 37.464 ;
     RECT  18.421 38.496 18.608 52.488 ;
     RECT  18.421 53.52 18.608 54.744 ;
     RECT  17.548 57.12 18.608 57.144 ;
     RECT  18.169 58.608 18.608 61.464 ;
     RECT  18.277 62.832 18.608 63.24 ;
     RECT  18.061 64.56 18.608 64.584 ;
     RECT  18.241 66.432 18.608 66.888 ;
     RECT  18.061 68.928 18.608 68.952 ;
     RECT  18.608 2.148 18.712 75.612 ;
     RECT  18.712 2.418 18.904 75.342 ;
     RECT  18.904 33.072 18.965 54.744 ;
     RECT  18.904 27.072 19.043 27.096 ;
     RECT  18.965 33.072 19.145 54.696 ;
     RECT  18.904 58.128 19.325 59.208 ;
     RECT  18.904 30.144 19.42 31.128 ;
     RECT  19.145 33.072 19.505 47.88 ;
     RECT  19.505 42.768 19.541 47.88 ;
     RECT  18.904 62.832 19.541 64.248 ;
     RECT  19.42 30.144 19.721 30.552 ;
     RECT  19.541 42.768 19.793 47.736 ;
     RECT  18.904 28.128 19.933 28.824 ;
     RECT  19.721 30.144 19.933 30.168 ;
     RECT  18.904 68.928 19.933 68.952 ;
     RECT  19.793 44.352 19.937 47.736 ;
     RECT  19.145 48.912 19.973 54.696 ;
     RECT  18.904 66.768 20.005 66.888 ;
     RECT  19.973 51.36 20.009 54.696 ;
     RECT  18.904 56.736 20.009 56.76 ;
     RECT  19.505 33.072 20.041 41.64 ;
     RECT  19.933 28.128 20.077 30.168 ;
     RECT  20.077 27.648 20.081 30.168 ;
     RECT  20.005 66.768 20.113 67.272 ;
     RECT  20.009 54.672 20.117 54.696 ;
     RECT  20.081 27.648 20.149 28.536 ;
     RECT  18.904 60.48 20.153 61.464 ;
     RECT  20.113 66.672 20.221 67.272 ;
     RECT  19.933 68.544 20.221 68.952 ;
     RECT  19.937 44.352 20.297 47.064 ;
     RECT  19.973 48.912 20.329 50.328 ;
     RECT  19.325 58.128 20.473 59.064 ;
     RECT  20.153 60.48 20.473 61.128 ;
     RECT  20.221 55.824 20.509 55.848 ;
     RECT  20.041 32.736 20.617 41.64 ;
     RECT  19.793 42.768 20.617 43.128 ;
     RECT  20.473 65.52 20.725 65.544 ;
     RECT  20.221 66.672 20.725 68.952 ;
     RECT  20.617 32.736 20.797 43.128 ;
     RECT  20.797 32.736 20.941 43.656 ;
     RECT  20.297 44.88 20.977 47.064 ;
     RECT  20.329 48.72 20.977 50.328 ;
     RECT  19.541 63.216 21.049 64.248 ;
     RECT  20.725 65.52 21.049 68.952 ;
     RECT  20.149 27.6 21.085 28.536 ;
     RECT  20.977 44.88 21.109 50.328 ;
     RECT  20.009 51.36 21.109 53.592 ;
     RECT  21.049 63.216 21.109 68.952 ;
     RECT  20.941 31.968 21.157 43.656 ;
     RECT  21.085 27.6 21.308 28.728 ;
     RECT  20.081 29.808 21.308 30.168 ;
     RECT  21.157 31.776 21.308 43.656 ;
     RECT  21.109 44.88 21.308 53.592 ;
     RECT  20.509 54.864 21.308 55.848 ;
     RECT  21.157 56.928 21.308 56.952 ;
     RECT  20.473 58.128 21.308 61.128 ;
     RECT  21.109 63.216 21.308 69.576 ;
     RECT  21.308 2.148 21.412 75.612 ;
     RECT  21.412 2.418 21.604 75.342 ;
     RECT  21.604 27.6 21.665 29.88 ;
     RECT  21.604 31.776 21.665 34.488 ;
     RECT  21.604 39.6 21.665 43.848 ;
     RECT  21.665 39.6 21.701 42.024 ;
     RECT  21.604 44.88 21.773 51.96 ;
     RECT  21.665 27.6 21.845 29.832 ;
     RECT  21.665 43.296 21.875 43.848 ;
     RECT  21.845 28.128 21.953 29.832 ;
     RECT  21.953 28.176 22.025 29.832 ;
     RECT  21.773 44.88 22.061 51.768 ;
     RECT  21.604 59.712 22.421 60.648 ;
     RECT  22.061 44.88 22.493 51.72 ;
     RECT  21.604 53.568 22.493 54.648 ;
     RECT  21.665 32.448 22.529 33.384 ;
     RECT  21.604 36 22.529 38.184 ;
     RECT  21.875 43.44 22.597 43.848 ;
     RECT  22.493 44.88 22.597 50.28 ;
     RECT  21.665 34.416 22.604 34.488 ;
     RECT  21.604 64.848 22.633 66.792 ;
     RECT  21.604 68.352 22.633 68.376 ;
     RECT  22.597 43.44 22.637 50.28 ;
     RECT  22.529 33.36 22.705 33.384 ;
     RECT  22.604 34.416 22.705 34.536 ;
     RECT  21.701 39.792 22.705 42.024 ;
     RECT  22.493 53.568 22.853 54.072 ;
     RECT  22.705 39.792 22.885 42.216 ;
     RECT  22.637 43.44 22.885 47.928 ;
     RECT  22.633 64.848 22.885 68.376 ;
     RECT  22.529 36.048 22.925 38.184 ;
     RECT  22.885 39.792 22.925 47.928 ;
     RECT  22.885 64.368 23.033 68.376 ;
     RECT  22.925 36.096 23.077 38.184 ;
     RECT  22.925 39.792 23.077 41.64 ;
     RECT  22.493 51.36 23.173 51.72 ;
     RECT  22.421 60 23.173 60.648 ;
     RECT  23.173 60 23.317 61.128 ;
     RECT  23.033 68.352 23.317 68.376 ;
     RECT  22.741 30.24 23.353 30.264 ;
     RECT  23.353 30.048 23.497 30.264 ;
     RECT  22.705 33.36 23.497 34.536 ;
     RECT  23.317 60 23.497 61.224 ;
     RECT  23.497 33.36 23.677 34.68 ;
     RECT  21.604 58.176 23.677 58.68 ;
     RECT  23.137 27.072 23.708 27.096 ;
     RECT  22.025 28.176 23.708 29.064 ;
     RECT  23.497 30.048 23.749 30.792 ;
     RECT  22.853 53.568 23.821 53.592 ;
     RECT  23.677 33.024 23.893 34.68 ;
     RECT  23.077 36.096 23.893 41.64 ;
     RECT  23.708 27.072 24.008 29.064 ;
     RECT  23.749 30.048 24.008 31.416 ;
     RECT  23.893 33.024 24.008 41.64 ;
     RECT  22.925 42.72 24.008 47.928 ;
     RECT  22.637 48.96 24.008 50.28 ;
     RECT  23.173 51.36 24.008 51.768 ;
     RECT  23.821 53.568 24.008 54.12 ;
     RECT  22.705 56.208 24.008 56.232 ;
     RECT  23.677 58.176 24.008 58.728 ;
     RECT  23.497 59.76 24.008 61.224 ;
     RECT  21.604 63.12 24.008 63.384 ;
     RECT  23.033 64.368 24.008 66.696 ;
     RECT  23.317 68.352 24.008 68.952 ;
     RECT  23.425 70.896 24.008 70.92 ;
     RECT  24.008 2.148 24.112 75.612 ;
     RECT  24.112 2.418 24.304 75.342 ;
     RECT  24.304 28.176 24.329 41.496 ;
     RECT  24.304 66.096 24.467 67.656 ;
     RECT  24.304 48.432 24.473 48.984 ;
     RECT  24.304 27.072 24.515 27.096 ;
     RECT  24.304 47.136 24.545 47.16 ;
     RECT  24.304 57.552 24.581 61.032 ;
     RECT  24.329 36.24 24.617 41.496 ;
     RECT  24.329 29.472 24.653 34.728 ;
     RECT  24.581 57.84 24.769 61.032 ;
     RECT  24.304 53.28 24.941 54.6 ;
     RECT  24.617 36.24 25.085 40.44 ;
     RECT  24.304 43.824 25.121 45.288 ;
     RECT  24.304 50.4 25.121 51.768 ;
     RECT  24.941 53.28 25.285 53.304 ;
     RECT  24.304 25.056 25.292 26.04 ;
     RECT  24.617 41.472 25.301 41.496 ;
     RECT  24.304 42.624 25.301 42.744 ;
     RECT  24.329 28.176 25.369 28.2 ;
     RECT  25.285 52.752 25.372 53.304 ;
     RECT  25.121 50.4 25.405 50.424 ;
     RECT  24.467 66.672 25.409 67.656 ;
     RECT  24.304 70.896 25.445 70.92 ;
     RECT  25.369 28.08 25.481 28.2 ;
     RECT  25.085 36.24 25.517 40.392 ;
     RECT  25.409 66.672 25.549 66.888 ;
     RECT  25.121 43.824 25.553 44.664 ;
     RECT  24.304 68.736 25.621 68.952 ;
     RECT  24.304 62.112 25.657 63.768 ;
     RECT  25.585 64.752 25.657 64.776 ;
     RECT  24.653 29.472 25.697 34.488 ;
     RECT  25.292 24.864 25.733 26.04 ;
     RECT  24.304 56.4 25.733 56.424 ;
     RECT  24.769 57.84 25.733 60.84 ;
     RECT  25.697 32.208 25.801 34.488 ;
     RECT  25.621 68.736 25.837 69.048 ;
     RECT  25.697 29.472 25.945 30.888 ;
     RECT  25.333 23.088 25.981 23.112 ;
     RECT  25.981 22.32 26.125 23.16 ;
     RECT  26.089 46.752 26.125 46.776 ;
     RECT  26.125 22.32 26.156 23.832 ;
     RECT  26.156 22.176 26.161 23.832 ;
     RECT  25.553 43.872 26.197 44.664 ;
     RECT  26.125 45.984 26.197 46.776 ;
     RECT  25.657 62.112 26.197 64.776 ;
     RECT  25.517 39.024 26.377 40.392 ;
     RECT  25.372 53.28 26.485 53.304 ;
     RECT  24.941 54.576 26.485 54.6 ;
     RECT  25.517 36.24 26.557 37.848 ;
     RECT  26.377 39.024 26.557 40.872 ;
     RECT  25.801 32.208 26.581 35.016 ;
     RECT  26.557 36.24 26.581 40.872 ;
     RECT  25.549 66.528 26.665 66.888 ;
     RECT  25.301 42.624 26.701 42.648 ;
     RECT  26.197 20.352 26.708 20.376 ;
     RECT  26.161 22.176 26.708 24.552 ;
     RECT  25.733 25.872 26.708 25.896 ;
     RECT  25.801 27.168 26.708 27.672 ;
     RECT  25.945 29.04 26.708 30.888 ;
     RECT  26.581 32.208 26.708 40.872 ;
     RECT  26.701 42.576 26.708 42.648 ;
     RECT  26.197 43.872 26.708 46.776 ;
     RECT  24.473 48.432 26.708 48.456 ;
     RECT  25.405 50.016 26.708 50.424 ;
     RECT  25.121 51.408 26.708 51.768 ;
     RECT  26.485 53.28 26.708 54.6 ;
     RECT  26.197 55.968 26.708 55.992 ;
     RECT  25.733 57.84 26.708 57.864 ;
     RECT  25.733 58.992 26.708 60.84 ;
     RECT  26.197 62.112 26.708 65.208 ;
     RECT  26.665 66.528 26.708 67.08 ;
     RECT  25.837 68.208 26.708 69.048 ;
     RECT  26.125 70.8 26.708 70.824 ;
     RECT  26.708 2.148 26.812 75.612 ;
     RECT  26.812 2.418 27.004 75.342 ;
     RECT  27.004 27.648 27.173 28.584 ;
     RECT  27.004 53.28 27.173 54.168 ;
     RECT  27.004 29.616 27.209 32.472 ;
     RECT  27.173 53.28 27.281 53.496 ;
     RECT  27.004 50.016 27.347 50.424 ;
     RECT  27.004 57.84 27.347 60.84 ;
     RECT  27.004 55.968 27.353 56.712 ;
     RECT  27.353 56.688 27.389 56.712 ;
     RECT  27.004 42.576 27.461 42.6 ;
     RECT  27.347 57.84 27.484 59.832 ;
     RECT  27.484 57.84 27.533 59.592 ;
     RECT  27.004 38.448 27.605 38.808 ;
     RECT  27.347 60.816 27.749 60.84 ;
     RECT  27.004 66.096 27.785 69.528 ;
     RECT  27.601 76.896 27.817 76.92 ;
     RECT  27.347 50.016 27.821 50.04 ;
     RECT  27.817 76.896 27.889 76.968 ;
     RECT  27.785 69.504 27.964 69.528 ;
     RECT  27.004 62.016 27.965 64.872 ;
     RECT  27.004 70.8 27.984 71.304 ;
     RECT  27.004 74.592 27.997 74.952 ;
     RECT  27.889 76.368 27.997 76.968 ;
     RECT  27.004 46.128 28.001 46.152 ;
     RECT  27.533 57.84 28.037 57.864 ;
     RECT  27.004 33.888 28.069 37.416 ;
     RECT  27.605 38.736 28.069 38.808 ;
     RECT  27.004 39.984 28.069 40.872 ;
     RECT  27.004 20.352 28.073 20.376 ;
     RECT  27.004 73.488 28.141 73.512 ;
     RECT  27.997 74.592 28.141 76.968 ;
     RECT  28.069 33.504 28.156 37.416 ;
     RECT  27.965 62.016 28.181 64.584 ;
     RECT  27.173 27.84 28.213 28.584 ;
     RECT  27.209 29.76 28.213 32.472 ;
     RECT  28.141 73.488 28.259 76.968 ;
     RECT  28.156 33.6 28.321 37.416 ;
     RECT  28.259 76.896 28.355 76.968 ;
     RECT  28.393 49.632 28.429 49.656 ;
     RECT  28.259 73.488 28.469 75.816 ;
     RECT  28.069 38.736 28.501 40.872 ;
     RECT  28.355 76.944 28.501 76.968 ;
     RECT  28.501 38.736 28.573 41.64 ;
     RECT  28.501 43.056 28.573 43.08 ;
     RECT  27.984 71.28 28.609 71.304 ;
     RECT  27.004 72.336 28.609 72.36 ;
     RECT  27.785 66.096 28.753 68.232 ;
     RECT  28.429 20.928 28.969 20.952 ;
     RECT  27.004 22.32 28.969 23.88 ;
     RECT  27.004 47.856 28.969 47.88 ;
     RECT  27.004 44.64 29.041 44.664 ;
     RECT  28.213 46.08 29.041 46.104 ;
     RECT  28.609 71.28 29.041 72.36 ;
     RECT  28.469 73.488 29.041 75.612 ;
     RECT  28.321 33.6 29.185 37.656 ;
     RECT  28.573 38.736 29.185 43.08 ;
     RECT  27.004 51.84 29.185 52.296 ;
     RECT  29.041 71.28 29.185 75.612 ;
     RECT  28.213 27.024 29.293 32.472 ;
     RECT  28.969 47.856 29.293 48.264 ;
     RECT  28.429 49.536 29.293 49.656 ;
     RECT  28.181 62.544 29.293 64.584 ;
     RECT  28.753 65.952 29.293 68.232 ;
     RECT  28.501 76.944 29.333 77.64 ;
     RECT  28.969 20.928 29.408 23.88 ;
     RECT  29.293 27.024 29.408 32.616 ;
     RECT  29.185 33.6 29.408 43.08 ;
     RECT  29.041 44.64 29.408 46.104 ;
     RECT  29.293 47.856 29.408 49.656 ;
     RECT  29.185 50.88 29.408 52.296 ;
     RECT  27.281 53.28 29.408 53.304 ;
     RECT  28.969 57.6 29.408 57.624 ;
     RECT  27.533 58.944 29.408 59.592 ;
     RECT  29.293 62.544 29.408 68.232 ;
     RECT  29.185 70.656 29.408 75.612 ;
     RECT  29.408 2.148 29.512 75.612 ;
     RECT  29.333 76.944 29.653 77.592 ;
     RECT  29.512 2.418 29.704 75.342 ;
     RECT  29.704 31.776 29.765 37.464 ;
     RECT  29.704 45.936 29.765 46.104 ;
     RECT  29.704 38.976 29.873 42.744 ;
     RECT  29.704 26.736 29.945 30.36 ;
     RECT  29.704 50.4 29.945 50.76 ;
     RECT  29.873 41.664 29.981 42.744 ;
     RECT  29.704 62.544 29.981 62.568 ;
     RECT  29.704 21.12 30.161 21.96 ;
     RECT  29.653 76.368 30.179 77.592 ;
     RECT  29.945 26.736 30.197 29.256 ;
     RECT  29.765 33.456 30.269 37.464 ;
     RECT  29.704 58.128 30.269 60.024 ;
     RECT  29.981 41.808 30.275 42.744 ;
     RECT  29.704 52.272 30.305 53.112 ;
     RECT  30.179 76.896 30.418 77.592 ;
     RECT  29.704 63.792 30.557 69.384 ;
     RECT  29.765 31.776 30.593 31.8 ;
     RECT  30.269 33.456 30.665 36.84 ;
     RECT  29.945 50.4 30.665 50.424 ;
     RECT  29.704 72.72 30.689 74.712 ;
     RECT  29.704 70.56 30.697 71.256 ;
     RECT  30.305 52.272 30.709 52.488 ;
     RECT  29.945 30.24 30.733 30.36 ;
     RECT  30.709 52.032 30.755 52.488 ;
     RECT  29.704 55.2 30.769 55.56 ;
     RECT  30.557 63.792 30.773 68.376 ;
     RECT  30.689 72.72 30.773 75.288 ;
     RECT  30.697 70.56 30.803 71.352 ;
     RECT  30.755 52.032 30.805 52.44 ;
     RECT  29.704 61.2 30.805 61.224 ;
     RECT  30.269 58.128 30.851 59.832 ;
     RECT  29.765 45.936 30.877 45.96 ;
     RECT  30.805 60.96 30.877 61.224 ;
     RECT  29.704 47.856 30.881 49.032 ;
     RECT  30.805 56.88 30.889 57.048 ;
     RECT  30.557 69.36 30.899 69.384 ;
     RECT  29.873 38.976 30.901 40.344 ;
     RECT  30.803 70.56 30.908 71.256 ;
     RECT  30.197 27.216 30.917 29.256 ;
     RECT  30.901 38.016 30.953 40.344 ;
     RECT  30.953 38.016 30.988 39.384 ;
     RECT  30.769 20.352 30.989 20.376 ;
     RECT  30.851 58.848 30.995 59.832 ;
     RECT  30.773 72.816 30.995 74.712 ;
     RECT  30.805 18.432 31.025 18.456 ;
     RECT  30.733 30.24 31.025 30.792 ;
     RECT  30.665 35.76 31.025 36.84 ;
     RECT  30.773 63.792 31.061 65.976 ;
     RECT  31.061 64.416 31.133 65.976 ;
     RECT  31.093 75.744 31.157 75.816 ;
     RECT  30.418 76.896 31.157 77.64 ;
     RECT  29.704 44.496 31.189 44.664 ;
     RECT  30.877 60.96 31.285 61.608 ;
     RECT  30.917 27.216 31.417 27.864 ;
     RECT  31.285 60.864 31.453 61.608 ;
     RECT  31.189 62.832 31.453 63.048 ;
     RECT  30.161 21.936 31.489 21.96 ;
     RECT  30.881 48.144 31.597 49.032 ;
     RECT  31.025 36.288 31.621 36.84 ;
     RECT  31.489 21.696 31.633 21.96 ;
     RECT  30.665 33.456 31.669 34.68 ;
     RECT  30.877 45.696 31.813 45.96 ;
     RECT  30.908 69.456 31.813 71.256 ;
     RECT  30.995 72.816 31.813 73.56 ;
     RECT  31.157 75.744 31.841 77.64 ;
     RECT  31.813 26.016 31.849 26.136 ;
     RECT  31.417 27.12 31.849 27.864 ;
     RECT  30.841 31.824 31.849 32.28 ;
     RECT  30.275 42.144 31.861 42.744 ;
     RECT  31.189 43.776 31.861 44.664 ;
     RECT  31.849 26.016 31.885 27.864 ;
     RECT  30.917 29.232 31.885 29.256 ;
     RECT  31.669 33.456 31.885 34.728 ;
     RECT  30.773 67.296 31.885 68.376 ;
     RECT  31.885 33.264 31.909 34.728 ;
     RECT  31.813 69.456 31.993 73.56 ;
     RECT  30.995 74.592 31.993 74.712 ;
     RECT  31.633 21.456 32.029 21.96 ;
     RECT  32.029 21.312 32.065 21.96 ;
     RECT  31.885 67.152 32.101 68.376 ;
     RECT  31.993 69.456 32.101 74.712 ;
     RECT  32.065 21.12 32.108 21.96 ;
     RECT  29.704 22.992 32.108 23.88 ;
     RECT  31.885 26.016 32.108 29.256 ;
     RECT  31.849 31.056 32.108 32.28 ;
     RECT  31.909 33.264 32.108 35.256 ;
     RECT  31.621 36.288 32.108 37.656 ;
     RECT  30.988 38.976 32.108 39.384 ;
     RECT  31.201 40.416 32.108 40.44 ;
     RECT  31.861 42.144 32.108 44.664 ;
     RECT  31.813 45.696 32.108 46.2 ;
     RECT  31.597 48.144 32.108 49.464 ;
     RECT  31.921 50.64 32.108 50.664 ;
     RECT  30.805 51.744 32.108 52.44 ;
     RECT  30.769 54.576 32.108 55.56 ;
     RECT  30.889 57.024 32.108 57.048 ;
     RECT  30.995 59.184 32.108 59.832 ;
     RECT  31.453 60.864 32.108 63.048 ;
     RECT  31.133 64.416 32.108 65.544 ;
     RECT  32.101 67.152 32.108 74.712 ;
     RECT  31.841 75.696 32.108 77.64 ;
     RECT  32.108 2.148 32.212 77.64 ;
     RECT  32.212 2.418 32.404 77.64 ;
     RECT  32.404 18.816 32.429 19.56 ;
     RECT  32.404 63.6 32.465 77.64 ;
     RECT  32.465 63.6 32.483 76.344 ;
     RECT  32.404 21.12 32.501 21.96 ;
     RECT  32.404 52.176 32.501 53.64 ;
     RECT  32.483 63.6 32.501 75.864 ;
     RECT  32.429 18.912 32.681 19.56 ;
     RECT  32.404 47.76 32.681 48.168 ;
     RECT  32.501 52.176 32.681 52.824 ;
     RECT  32.501 63.6 32.753 75.816 ;
     RECT  32.501 21.168 32.786 21.96 ;
     RECT  32.404 30.288 32.789 36.504 ;
     RECT  32.404 44.448 32.941 44.664 ;
     RECT  32.786 21.216 33.113 21.96 ;
     RECT  32.404 40.416 33.113 43.368 ;
     RECT  33.113 40.416 33.149 42.36 ;
     RECT  32.681 19.536 33.221 19.56 ;
     RECT  32.404 55.824 33.221 57.576 ;
     RECT  32.404 26.64 33.257 26.76 ;
     RECT  32.789 30.288 33.329 32.52 ;
     RECT  32.404 29.232 33.397 29.256 ;
     RECT  33.221 55.824 33.401 57.432 ;
     RECT  33.401 56.4 33.443 57.432 ;
     RECT  32.404 59.184 33.505 62.616 ;
     RECT  32.753 63.6 33.505 64.392 ;
     RECT  33.329 30.288 33.509 30.648 ;
     RECT  32.404 17.136 33.577 17.208 ;
     RECT  33.505 59.184 33.577 64.392 ;
     RECT  32.941 44.64 33.637 44.664 ;
     RECT  32.404 45.792 33.637 45.816 ;
     RECT  33.329 31.776 33.653 32.52 ;
     RECT  33.637 44.64 33.683 45.816 ;
     RECT  32.681 52.176 33.721 52.584 ;
     RECT  33.577 59.04 33.725 64.392 ;
     RECT  33.257 26.736 33.757 26.76 ;
     RECT  32.465 77.424 33.781 77.64 ;
     RECT  33.577 17.04 33.793 17.208 ;
     RECT  32.404 49.776 33.793 49.8 ;
     RECT  33.113 21.504 33.829 21.96 ;
     RECT  33.721 51.648 33.829 52.584 ;
     RECT  32.681 47.76 33.833 47.784 ;
     RECT  32.789 34.08 33.932 36.504 ;
     RECT  32.404 37.584 33.932 38.472 ;
     RECT  33.757 26.736 33.937 27.144 ;
     RECT  33.781 77.376 33.973 77.64 ;
     RECT  32.404 23.616 34.009 24.504 ;
     RECT  33.793 48.96 34.045 49.8 ;
     RECT  33.829 51.312 34.045 52.584 ;
     RECT  33.683 44.64 34.069 45.576 ;
     RECT  33.973 77.328 34.145 77.64 ;
     RECT  34.009 23.616 34.153 25.416 ;
     RECT  33.725 59.04 34.153 62.76 ;
     RECT  33.901 32.784 34.189 32.808 ;
     RECT  33.829 21.504 34.225 22.2 ;
     RECT  34.145 77.28 34.228 77.64 ;
     RECT  34.225 21.408 34.297 22.2 ;
     RECT  33.725 64.32 34.297 64.392 ;
     RECT  32.753 65.76 34.297 75.816 ;
     RECT  34.297 21.408 34.333 22.248 ;
     RECT  34.153 23.376 34.333 25.416 ;
     RECT  33.932 34.08 34.405 38.472 ;
     RECT  33.653 31.776 34.441 31.8 ;
     RECT  33.793 17.04 34.513 17.4 ;
     RECT  33.937 26.736 34.513 27.192 ;
     RECT  33.397 28.32 34.513 29.256 ;
     RECT  33.443 57.408 34.549 57.432 ;
     RECT  33.509 30.336 34.621 30.648 ;
     RECT  34.441 31.68 34.621 31.8 ;
     RECT  34.549 56.976 34.657 57.432 ;
     RECT  34.513 26.736 34.765 29.256 ;
     RECT  34.621 30.336 34.765 31.8 ;
     RECT  34.513 17.04 34.808 18.216 ;
     RECT  34.333 21.408 34.808 25.416 ;
     RECT  34.765 26.736 34.808 31.8 ;
     RECT  34.189 32.784 34.808 33.048 ;
     RECT  34.405 34.08 34.808 38.76 ;
     RECT  33.149 41.136 34.808 42.36 ;
     RECT  34.069 44.448 34.808 45.576 ;
     RECT  34.045 48.96 34.808 52.584 ;
     RECT  34.693 55.728 34.808 55.752 ;
     RECT  34.657 56.976 34.808 57.672 ;
     RECT  34.153 58.704 34.808 62.76 ;
     RECT  34.297 64.32 34.808 75.816 ;
     RECT  34.808 2.148 34.912 75.816 ;
     RECT  34.912 2.418 35.104 75.816 ;
     RECT  35.104 27.6 35.308 42.984 ;
     RECT  35.104 16.896 35.309 18.792 ;
     RECT  35.104 57.408 35.309 58.152 ;
     RECT  35.104 61.488 35.363 62.712 ;
     RECT  35.104 63.792 35.381 67.704 ;
     RECT  35.308 27.6 35.417 42.216 ;
     RECT  35.104 55.728 35.453 56.184 ;
     RECT  35.104 73.344 35.489 75.816 ;
     RECT  34.228 77.232 35.489 77.64 ;
     RECT  35.417 27.6 35.525 41.544 ;
     RECT  35.381 63.792 35.597 66.888 ;
     RECT  35.104 20.4 35.633 26.616 ;
     RECT  35.309 17.616 35.705 18.792 ;
     RECT  35.633 20.4 35.705 23.592 ;
     RECT  35.489 74.304 35.705 75.816 ;
     RECT  35.525 27.6 35.741 30.168 ;
     RECT  35.489 77.232 35.741 77.592 ;
     RECT  35.705 74.304 35.813 75.24 ;
     RECT  35.741 77.232 35.849 77.4 ;
     RECT  35.849 77.376 35.885 77.4 ;
     RECT  35.525 31.152 35.891 41.544 ;
     RECT  35.597 63.792 35.891 65.784 ;
     RECT  35.741 27.984 35.921 30.168 ;
     RECT  35.363 62.16 35.957 62.712 ;
     RECT  35.104 68.928 35.957 72.264 ;
     RECT  35.891 63.792 35.993 63.96 ;
     RECT  35.705 20.4 36.029 22.824 ;
     RECT  35.891 33.6 36.029 41.544 ;
     RECT  35.813 74.304 36.029 74.952 ;
     RECT  36.029 33.6 36.065 36.936 ;
     RECT  35.957 68.928 36.097 71.736 ;
     RECT  36.029 38.448 36.101 41.544 ;
     RECT  35.104 47.28 36.133 48.504 ;
     RECT  35.104 52.992 36.137 54.072 ;
     RECT  35.597 66.768 36.137 66.888 ;
     RECT  36.029 20.4 36.173 22.632 ;
     RECT  35.891 65.184 36.173 65.544 ;
     RECT  35.633 25.152 36.245 26.616 ;
     RECT  36.133 46.8 36.349 48.504 ;
     RECT  35.104 49.872 36.349 50.184 ;
     RECT  35.705 18.192 36.389 18.792 ;
     RECT  36.065 34.896 36.389 36.936 ;
     RECT  36.101 39.6 36.389 41.544 ;
     RECT  35.309 57.648 36.421 58.152 ;
     RECT  35.453 55.728 36.461 55.8 ;
     RECT  36.097 68.496 36.461 71.736 ;
     RECT  36.349 46.8 36.508 50.184 ;
     RECT  36.421 56.88 36.508 58.152 ;
     RECT  35.104 44.64 36.709 45 ;
     RECT  36.508 46.8 36.709 48.504 ;
     RECT  36.673 61.92 36.709 61.944 ;
     RECT  36.709 44.64 36.757 48.504 ;
     RECT  36.508 49.488 36.853 50.184 ;
     RECT  36.853 49.488 37.069 50.232 ;
     RECT  35.104 51.648 37.069 51.768 ;
     RECT  36.389 18.432 37.141 18.792 ;
     RECT  35.891 31.152 37.141 31.992 ;
     RECT  36.065 33.6 37.141 33.816 ;
     RECT  35.993 63.792 37.141 63.816 ;
     RECT  36.173 65.184 37.141 65.256 ;
     RECT  36.245 25.392 37.213 26.616 ;
     RECT  35.921 28.416 37.237 30.168 ;
     RECT  37.141 31.152 37.237 33.816 ;
     RECT  37.237 28.416 37.292 33.816 ;
     RECT  36.529 42.72 37.349 42.744 ;
     RECT  37.213 17.184 37.393 17.208 ;
     RECT  37.141 18.432 37.393 19.272 ;
     RECT  37.393 17.184 37.429 19.272 ;
     RECT  37.429 16.896 37.508 19.272 ;
     RECT  36.173 20.4 37.508 22.488 ;
     RECT  36.997 24.384 37.508 24.408 ;
     RECT  37.213 25.392 37.508 26.904 ;
     RECT  37.292 28.416 37.508 34.2 ;
     RECT  36.389 35.328 37.508 36.936 ;
     RECT  36.101 38.448 37.508 38.472 ;
     RECT  36.389 39.6 37.508 41.016 ;
     RECT  37.349 42.096 37.508 42.744 ;
     RECT  36.757 43.824 37.508 48.504 ;
     RECT  37.069 49.488 37.508 51.768 ;
     RECT  36.137 52.992 37.508 53.112 ;
     RECT  36.889 54.624 37.508 54.648 ;
     RECT  36.461 55.776 37.508 55.8 ;
     RECT  36.508 57.312 37.508 58.152 ;
     RECT  36.709 60.912 37.508 61.944 ;
     RECT  37.141 63.792 37.508 65.256 ;
     RECT  36.524 67.44 37.508 67.464 ;
     RECT  36.461 68.496 37.508 69.336 ;
     RECT  36.461 71.328 37.508 71.736 ;
     RECT  36.029 74.928 37.508 74.952 ;
     RECT  37.508 2.148 37.612 75.612 ;
     RECT  37.612 2.418 37.804 75.342 ;
     RECT  37.804 71.712 37.829 71.736 ;
     RECT  37.804 23.952 37.865 24.408 ;
     RECT  37.804 46.848 37.973 47.64 ;
     RECT  37.804 54.336 38.099 61.944 ;
     RECT  37.804 42.72 38.189 45 ;
     RECT  37.804 63.792 38.189 65.208 ;
     RECT  37.804 19.584 38.225 22.488 ;
     RECT  37.973 46.848 38.225 46.872 ;
     RECT  37.804 16.8 38.261 16.92 ;
     RECT  37.804 35.52 38.261 41.064 ;
     RECT  38.261 16.896 38.297 16.92 ;
     RECT  37.804 28.416 38.297 32.376 ;
     RECT  37.804 68.496 38.297 69.336 ;
     RECT  38.099 55.776 38.621 61.944 ;
     RECT  37.804 67.248 38.621 67.368 ;
     RECT  37.804 18.24 38.657 18.552 ;
     RECT  37.865 23.952 38.657 23.976 ;
     RECT  38.657 18.432 38.729 18.552 ;
     RECT  38.225 21.168 38.729 22.488 ;
     RECT  38.261 35.52 38.773 38.76 ;
     RECT  37.804 33.552 38.801 34.2 ;
     RECT  38.729 18.528 38.837 18.552 ;
     RECT  38.297 28.8 38.873 32.376 ;
     RECT  38.833 46.656 38.941 46.68 ;
     RECT  37.804 48.96 38.963 53.064 ;
     RECT  38.621 57.408 38.963 61.944 ;
     RECT  38.963 52.752 38.977 53.064 ;
     RECT  38.189 64.128 39.011 65.208 ;
     RECT  37.804 25.44 39.049 26.232 ;
     RECT  38.189 43.536 39.124 45 ;
     RECT  39.124 43.536 39.125 45.048 ;
     RECT  38.873 29.232 39.161 32.376 ;
     RECT  38.729 21.216 39.193 22.488 ;
     RECT  38.773 35.328 39.229 38.76 ;
     RECT  38.261 39.84 39.265 41.064 ;
     RECT  39.229 35.328 39.409 38.808 ;
     RECT  39.265 39.84 39.409 41.208 ;
     RECT  38.099 54.336 39.409 54.36 ;
     RECT  38.297 69.024 39.445 69.336 ;
     RECT  39.013 62.976 39.517 63 ;
     RECT  39.011 64.128 39.517 64.392 ;
     RECT  39.049 25.44 39.553 26.472 ;
     RECT  39.409 34.608 39.805 38.808 ;
     RECT  39.409 39.792 39.805 41.208 ;
     RECT  39.193 21.216 39.841 22.536 ;
     RECT  39.125 44.448 39.841 45.048 ;
     RECT  38.941 46.464 39.841 46.68 ;
     RECT  38.977 52.752 39.841 53.304 ;
     RECT  39.409 54.336 39.841 54.696 ;
     RECT  38.801 33.552 39.877 33.624 ;
     RECT  39.805 34.608 39.877 41.208 ;
     RECT  39.337 43.296 39.877 43.32 ;
     RECT  39.841 44.448 39.877 46.68 ;
     RECT  39.841 52.752 39.877 54.696 ;
     RECT  38.621 55.776 39.877 56.088 ;
     RECT  38.225 19.584 39.949 19.608 ;
     RECT  39.949 19.536 40.021 19.608 ;
     RECT  39.877 52.752 40.021 56.088 ;
     RECT  39.445 68.88 40.021 69.336 ;
     RECT  40.008 23.952 40.069 23.976 ;
     RECT  39.553 25.104 40.069 26.472 ;
     RECT  40.021 68.88 40.069 69.528 ;
     RECT  39.301 71.232 40.069 71.256 ;
     RECT  38.797 17.376 40.093 17.4 ;
     RECT  39.877 42.864 40.093 43.32 ;
     RECT  40.021 19.536 40.129 19.656 ;
     RECT  39.877 44.448 40.129 46.92 ;
     RECT  38.963 57.408 40.129 59.064 ;
     RECT  38.963 60.384 40.129 61.944 ;
     RECT  40.093 17.376 40.208 18.024 ;
     RECT  40.129 19.536 40.208 19.896 ;
     RECT  39.841 20.976 40.208 22.536 ;
     RECT  40.069 23.952 40.208 26.472 ;
     RECT  39.161 29.232 40.208 31.944 ;
     RECT  39.877 33.552 40.208 41.208 ;
     RECT  40.093 42.192 40.208 43.32 ;
     RECT  40.129 44.352 40.208 46.92 ;
     RECT  38.963 48.96 40.208 51.768 ;
     RECT  40.021 52.752 40.208 56.28 ;
     RECT  40.129 57.408 40.208 61.944 ;
     RECT  39.517 62.976 40.208 64.392 ;
     RECT  38.621 67.344 40.208 67.368 ;
     RECT  40.069 68.88 40.208 71.256 ;
     RECT  40.208 2.148 40.312 75.612 ;
     RECT  40.312 2.418 40.504 75.342 ;
     RECT  40.504 46.512 40.643 47.88 ;
     RECT  40.504 48.96 40.643 57.576 ;
     RECT  40.643 50.448 40.684 57.576 ;
     RECT  40.504 20.592 40.709 25.704 ;
     RECT  40.643 48.96 40.709 48.984 ;
     RECT  40.504 58.656 40.835 63.816 ;
     RECT  40.504 36.912 40.853 45.288 ;
     RECT  40.504 17.952 40.889 18.264 ;
     RECT  40.504 30.192 40.889 35.544 ;
     RECT  40.684 50.592 40.961 57.576 ;
     RECT  40.835 58.656 41.105 59.832 ;
     RECT  40.835 61.152 41.105 62.04 ;
     RECT  40.835 63.744 41.105 63.816 ;
     RECT  40.709 20.592 41.141 22.008 ;
     RECT  40.889 17.952 41.213 18.216 ;
     RECT  40.961 50.592 41.285 56.04 ;
     RECT  40.853 36.912 41.321 40.344 ;
     RECT  40.853 42.048 41.321 45.288 ;
     RECT  40.889 30.192 41.363 31.176 ;
     RECT  41.321 44.448 41.363 45.288 ;
     RECT  41.213 18.192 41.429 18.216 ;
     RECT  40.504 19.584 41.429 19.608 ;
     RECT  40.889 32.592 41.459 35.544 ;
     RECT  41.321 42.048 41.459 43.32 ;
     RECT  40.709 23.136 41.5 25.704 ;
     RECT  41.459 42.048 41.5 42.792 ;
     RECT  41.363 44.688 41.501 45.288 ;
     RECT  40.643 46.512 41.501 46.776 ;
     RECT  41.141 20.592 41.537 21 ;
     RECT  41.501 44.688 41.603 44.712 ;
     RECT  41.459 33.552 41.609 35.544 ;
     RECT  41.321 39.744 41.645 40.344 ;
     RECT  41.285 50.592 41.645 54.456 ;
     RECT  41.363 30.192 41.653 30.216 ;
     RECT  41.537 20.976 41.681 21 ;
     RECT  41.5 23.136 41.713 23.592 ;
     RECT  41.653 29.376 41.74 30.216 ;
     RECT  41.609 34.752 41.749 35.544 ;
     RECT  41.713 22.368 41.753 23.592 ;
     RECT  41.105 61.632 41.861 62.04 ;
     RECT  40.504 69.312 41.957 70.344 ;
     RECT  41.957 69.312 41.989 71.304 ;
     RECT  41.105 59.328 42.073 59.832 ;
     RECT  41.5 24.72 42.133 25.704 ;
     RECT  41.989 68.352 42.145 71.304 ;
     RECT  41.285 55.536 42.217 56.04 ;
     RECT  40.961 57.024 42.217 57.576 ;
     RECT  41.753 22.368 42.253 22.872 ;
     RECT  42.325 44.352 42.397 44.376 ;
     RECT  41.5 42.048 42.469 42.264 ;
     RECT  42.397 43.824 42.469 44.376 ;
     RECT  41.861 61.968 42.497 62.04 ;
     RECT  42.133 24.72 42.541 26.28 ;
     RECT  41.321 36.912 42.541 38.76 ;
     RECT  41.645 39.744 42.541 40.296 ;
     RECT  42.541 24.72 42.613 26.76 ;
     RECT  41.645 50.64 42.649 54.456 ;
     RECT  42.649 50.16 42.721 54.456 ;
     RECT  42.217 55.536 42.721 57.576 ;
     RECT  41.749 28.272 42.757 28.296 ;
     RECT  41.74 30.192 42.757 30.216 ;
     RECT  41.677 48.336 42.757 48.36 ;
     RECT  41.501 46.512 42.793 46.536 ;
     RECT  42.793 46.512 42.829 46.632 ;
     RECT  42.613 24.72 42.865 27.096 ;
     RECT  42.829 46.224 42.865 46.632 ;
     RECT  42.721 19.872 42.908 19.896 ;
     RECT  42.253 21.408 42.908 22.872 ;
     RECT  42.865 23.952 42.908 27.096 ;
     RECT  42.757 28.272 42.908 28.776 ;
     RECT  42.757 30.192 42.908 30.456 ;
     RECT  42.109 31.872 42.908 31.896 ;
     RECT  41.609 33.552 42.908 33.72 ;
     RECT  41.749 34.752 42.908 35.736 ;
     RECT  42.541 36.912 42.908 40.296 ;
     RECT  42.469 42.048 42.908 44.376 ;
     RECT  42.865 46.224 42.908 46.728 ;
     RECT  42.757 47.856 42.908 49.032 ;
     RECT  42.721 50.16 42.908 57.576 ;
     RECT  42.073 58.704 42.908 59.832 ;
     RECT  42.497 61.968 42.908 62.712 ;
     RECT  41.105 63.744 42.908 63.768 ;
     RECT  42.145 68.208 42.908 71.304 ;
     RECT  42.908 2.148 43.012 75.612 ;
     RECT  43.012 2.418 43.117 75.612 ;
     RECT  43.117 2.418 43.201 75.816 ;
     RECT  43.201 2.418 43.204 75.342 ;
     RECT  43.141 0.528 43.265 0.552 ;
     RECT  43.204 68.208 43.265 68.232 ;
     RECT  43.204 3.936 43.331 3.96 ;
     RECT  43.204 16.56 43.331 16.584 ;
     RECT  43.204 22.224 43.331 30.456 ;
     RECT  43.204 45.696 43.331 47.976 ;
     RECT  43.204 49.008 43.331 56.52 ;
     RECT  43.204 69.456 43.331 69.576 ;
     RECT  43.331 22.224 43.337 30.408 ;
     RECT  43.337 22.224 43.373 27.096 ;
     RECT  43.331 46.224 43.373 47.976 ;
     RECT  43.373 24.72 43.517 27.096 ;
     RECT  43.517 24.72 43.553 26.136 ;
     RECT  43.553 25.44 43.619 26.136 ;
     RECT  43.619 25.44 43.625 25.656 ;
     RECT  43.331 49.008 43.625 56.472 ;
     RECT  43.204 34.752 43.733 35.736 ;
     RECT  43.204 20.784 43.859 20.808 ;
     RECT  43.625 25.44 43.859 25.608 ;
     RECT  43.337 28.368 43.877 30.408 ;
     RECT  43.373 46.224 43.907 47.88 ;
     RECT  43.907 46.224 43.913 46.728 ;
     RECT  43.907 47.856 43.949 47.88 ;
     RECT  43.625 49.008 43.949 54.696 ;
     RECT  43.204 71.232 43.955 71.88 ;
     RECT  43.204 37.008 44.021 37.032 ;
     RECT  43.204 38.16 44.021 42.168 ;
     RECT  43.955 71.232 44.021 71.256 ;
     RECT  43.373 22.224 44.057 23.064 ;
     RECT  43.877 28.512 44.201 30.408 ;
     RECT  43.204 58.464 44.233 60.648 ;
     RECT  43.204 18.72 44.237 19.368 ;
     RECT  43.204 61.728 44.269 61.992 ;
     RECT  43.204 44.352 44.293 44.472 ;
     RECT  44.021 38.16 44.305 42.072 ;
     RECT  43.949 49.776 44.345 54.696 ;
     RECT  44.293 43.872 44.38 44.76 ;
     RECT  44.233 57.696 44.381 60.648 ;
     RECT  44.057 23.04 44.413 23.064 ;
     RECT  44.381 57.696 44.417 58.488 ;
     RECT  44.305 37.44 44.489 42.072 ;
     RECT  44.38 43.872 44.489 44.472 ;
     RECT  43.625 55.92 44.581 56.472 ;
     RECT  44.417 57.696 44.581 57.72 ;
     RECT  44.413 23.04 44.665 23.112 ;
     RECT  43.331 69.456 44.701 69.48 ;
     RECT  44.345 50.112 44.773 54.696 ;
     RECT  44.665 23.04 44.881 23.16 ;
     RECT  43.204 31.632 44.965 31.656 ;
     RECT  44.381 59.616 45.013 60.648 ;
     RECT  44.269 61.728 45.013 62.088 ;
     RECT  44.965 30.864 45.025 31.656 ;
     RECT  43.913 46.224 45.061 46.344 ;
     RECT  44.773 50.112 45.061 54.744 ;
     RECT  44.881 23.04 45.241 23.208 ;
     RECT  44.581 55.92 45.253 57.72 ;
     RECT  44.989 49.104 45.313 49.128 ;
     RECT  44.489 37.44 45.349 41.64 ;
     RECT  45.241 22.848 45.421 23.208 ;
     RECT  43.204 17.568 45.493 17.592 ;
     RECT  44.237 18.768 45.493 19.368 ;
     RECT  45.493 27.36 45.601 27.384 ;
     RECT  44.201 28.512 45.601 29.64 ;
     RECT  45.493 17.568 45.608 19.368 ;
     RECT  45.421 22.752 45.608 23.208 ;
     RECT  43.859 25.584 45.608 25.608 ;
     RECT  45.601 27.36 45.608 29.64 ;
     RECT  45.025 30.864 45.608 32.52 ;
     RECT  44.629 33.648 45.608 33.672 ;
     RECT  43.733 34.8 45.608 35.736 ;
     RECT  45.349 37.104 45.608 41.64 ;
     RECT  44.489 44.448 45.608 44.472 ;
     RECT  45.061 46.176 45.608 46.344 ;
     RECT  45.313 48.24 45.608 49.128 ;
     RECT  45.061 50.112 45.608 54.888 ;
     RECT  45.253 55.872 45.608 57.72 ;
     RECT  45.013 59.616 45.608 62.088 ;
     RECT  44.701 68.976 45.608 69.48 ;
     RECT  44.341 70.656 45.608 70.68 ;
     RECT  45.608 2.148 45.712 75.612 ;
     RECT  45.712 2.418 45.904 75.342 ;
     RECT  45.904 22.752 45.929 23.064 ;
     RECT  45.929 23.04 45.965 23.064 ;
     RECT  45.904 36.528 46.08 42.216 ;
     RECT  46.08 37.104 46.109 42.216 ;
     RECT  45.904 48.24 46.109 53.64 ;
     RECT  45.904 68.976 46.163 70.104 ;
     RECT  45.904 28.512 46.181 29.64 ;
     RECT  45.904 17.472 46.217 18.792 ;
     RECT  45.904 46.272 46.253 47.112 ;
     RECT  46.109 48.24 46.289 49.464 ;
     RECT  46.163 69.696 46.325 70.104 ;
     RECT  46.217 18.768 46.433 18.792 ;
     RECT  45.904 54.624 46.541 57.048 ;
     RECT  45.904 61.728 46.541 61.752 ;
     RECT  46.253 46.272 46.577 46.296 ;
     RECT  46.109 50.544 46.577 53.64 ;
     RECT  46.541 54.624 46.577 55.56 ;
     RECT  45.904 34.656 46.721 35.304 ;
     RECT  46.577 54.72 46.757 55.56 ;
     RECT  46.541 56.928 46.933 57.048 ;
     RECT  45.904 27.36 46.937 27.48 ;
     RECT  45.904 59.76 46.988 60.12 ;
     RECT  46.933 56.928 46.997 57.864 ;
     RECT  46.181 28.512 47.029 29.016 ;
     RECT  45.904 44.064 47.045 44.376 ;
     RECT  46.997 56.928 47.075 58.152 ;
     RECT  46.988 59.232 47.075 60.12 ;
     RECT  46.757 55.104 47.081 55.56 ;
     RECT  47.029 27.888 47.117 29.016 ;
     RECT  46.325 70.08 47.117 70.104 ;
     RECT  46.577 50.688 47.297 53.592 ;
     RECT  46.109 37.296 47.545 42.216 ;
     RECT  47.437 46.896 47.653 47.88 ;
     RECT  46.289 49.056 47.653 49.464 ;
     RECT  47.081 55.104 47.833 55.272 ;
     RECT  47.075 57.36 47.941 58.152 ;
     RECT  46.721 34.656 47.977 34.68 ;
     RECT  47.045 44.064 48.157 44.088 ;
     RECT  47.437 45.456 48.157 45.48 ;
     RECT  46.217 17.472 48.308 17.496 ;
     RECT  48.193 23.088 48.308 23.112 ;
     RECT  47.149 25.584 48.308 25.608 ;
     RECT  48.301 27.168 48.308 27.192 ;
     RECT  47.117 28.512 48.308 29.016 ;
     RECT  47.977 34.656 48.308 34.776 ;
     RECT  47.653 36 48.308 36.024 ;
     RECT  47.545 37.296 48.308 42.504 ;
     RECT  48.157 43.536 48.308 45.48 ;
     RECT  47.653 46.896 48.308 49.464 ;
     RECT  47.297 50.688 48.308 52.296 ;
     RECT  47.297 53.568 48.308 53.592 ;
     RECT  47.833 54.624 48.308 55.272 ;
     RECT  47.941 57.36 48.308 58.68 ;
     RECT  47.075 59.856 48.308 60.024 ;
     RECT  48.157 69.552 48.308 69.576 ;
     RECT  48.308 2.148 48.412 75.612 ;
     RECT  48.412 2.418 48.604 75.342 ;
     RECT  48.604 27.888 48.629 30.744 ;
     RECT  48.604 48.432 48.737 49.08 ;
     RECT  48.604 41.472 48.755 44.088 ;
     RECT  48.604 45.456 48.773 46.92 ;
     RECT  48.604 54.624 48.773 55.848 ;
     RECT  48.773 45.456 48.796 46.728 ;
     RECT  48.604 51.168 48.803 52.296 ;
     RECT  48.796 46.704 48.817 46.728 ;
     RECT  48.629 28.512 48.881 30.744 ;
     RECT  48.755 41.472 48.881 43.56 ;
     RECT  48.881 28.752 48.989 30.744 ;
     RECT  48.737 48.432 48.989 49.032 ;
     RECT  48.604 22.464 49.025 23.112 ;
     RECT  48.604 56.88 49.043 61.08 ;
     RECT  48.604 34.464 49.061 34.776 ;
     RECT  48.881 42.336 49.097 43.56 ;
     RECT  48.773 54.624 49.097 54.648 ;
     RECT  49.061 34.656 49.133 34.68 ;
     RECT  48.803 51.888 49.133 52.296 ;
     RECT  48.604 62.4 49.235 62.424 ;
     RECT  48.604 68.928 49.235 70.248 ;
     RECT  49.235 69.456 49.276 70.248 ;
     RECT  48.796 45.456 49.313 45.624 ;
     RECT  48.604 36 49.385 39.864 ;
     RECT  48.604 20.544 49.421 20.568 ;
     RECT  48.604 25.968 49.457 26.664 ;
     RECT  49.133 51.888 49.457 51.912 ;
     RECT  48.989 48.816 49.493 49.032 ;
     RECT  49.043 60.432 49.565 61.08 ;
     RECT  49.276 70.224 49.565 70.248 ;
     RECT  49.025 22.464 49.597 22.536 ;
     RECT  48.604 17.328 49.601 18.792 ;
     RECT  48.604 24.144 49.633 24.168 ;
     RECT  49.043 56.88 49.637 59.16 ;
     RECT  49.385 36 49.673 38.76 ;
     RECT  49.313 45.6 49.673 45.624 ;
     RECT  49.637 56.88 49.673 58.152 ;
     RECT  49.601 17.328 49.709 17.4 ;
     RECT  49.601 18.384 49.709 18.792 ;
     RECT  49.709 18.384 49.781 18.744 ;
     RECT  49.597 21.792 49.781 22.536 ;
     RECT  48.773 55.824 49.861 55.848 ;
     RECT  49.673 56.88 49.861 57.192 ;
     RECT  49.565 60.768 49.889 61.08 ;
     RECT  49.861 55.824 49.907 57.192 ;
     RECT  49.637 59.136 49.907 59.16 ;
     RECT  49.889 60.768 49.907 60.792 ;
     RECT  48.604 32.496 49.916 32.52 ;
     RECT  49.633 24.144 49.957 24.408 ;
     RECT  49.916 32.496 49.957 32.712 ;
     RECT  49.907 55.824 49.961 56.088 ;
     RECT  49.907 57.168 49.961 57.192 ;
     RECT  49.457 25.968 49.997 25.992 ;
     RECT  48.604 53.568 49.997 53.592 ;
     RECT  49.957 24.096 50.029 24.408 ;
     RECT  49.957 32.256 50.101 32.712 ;
     RECT  49.097 42.336 50.101 42.744 ;
     RECT  50.149 50.16 50.173 50.184 ;
     RECT  50.06 51.552 50.173 51.576 ;
     RECT  50.029 24.096 50.353 25.032 ;
     RECT  49.709 17.376 50.605 17.4 ;
     RECT  49.781 18.384 50.605 18.648 ;
     RECT  49.781 22.512 50.749 22.536 ;
     RECT  50.749 21.216 50.821 21.24 ;
     RECT  49.673 36.24 50.821 38.76 ;
     RECT  49.385 39.744 50.821 39.864 ;
     RECT  50.857 35.232 50.929 35.256 ;
     RECT  50.821 36.24 50.929 39.864 ;
     RECT  50.605 17.376 51.008 18.648 ;
     RECT  50.821 20.688 51.008 21.24 ;
     RECT  50.749 22.512 51.008 22.776 ;
     RECT  50.353 23.952 51.008 25.032 ;
     RECT  49.633 27.648 51.008 27.672 ;
     RECT  48.989 28.752 51.008 30.648 ;
     RECT  50.101 32.256 51.008 32.808 ;
     RECT  50.173 34.08 51.008 34.104 ;
     RECT  50.929 35.232 51.008 39.864 ;
     RECT  50.641 40.944 51.008 40.968 ;
     RECT  50.101 42.336 51.008 43.128 ;
     RECT  49.493 48.816 51.008 48.84 ;
     RECT  50.173 50.16 51.008 51.576 ;
     RECT  50.101 52.848 51.008 52.872 ;
     RECT  50.389 54.144 51.008 54.168 ;
     RECT  49.961 56.064 51.008 56.088 ;
     RECT  51.008 2.148 51.112 75.612 ;
     RECT  51.112 2.418 51.304 75.342 ;
     RECT  51.304 22.752 51.329 22.92 ;
     RECT  51.304 24.384 51.365 24.408 ;
     RECT  51.304 28.752 51.509 29.784 ;
     RECT  51.304 37.44 51.833 40.104 ;
     RECT  51.304 42.72 52.013 43.224 ;
     RECT  51.509 28.752 52.229 29.112 ;
     RECT  51.329 22.896 52.441 22.92 ;
     RECT  51.304 34.08 52.441 35.832 ;
     RECT  51.304 27.072 52.477 27.48 ;
     RECT  51.304 21.12 52.481 21.192 ;
     RECT  51.304 18.192 52.549 18.264 ;
     RECT  51.304 32.304 52.549 32.328 ;
     RECT  52.441 33.36 52.549 36.264 ;
     RECT  52.441 22.896 52.553 22.968 ;
     RECT  52.549 32.304 52.621 36.264 ;
     RECT  52.481 21.12 52.765 21.144 ;
     RECT  52.621 32.208 52.801 36.264 ;
     RECT  52.801 32.16 52.837 36.264 ;
     RECT  52.477 26.208 52.981 27.48 ;
     RECT  52.553 22.896 53.053 22.92 ;
     RECT  52.837 31.872 53.125 36.264 ;
     RECT  52.013 43.2 53.228 43.224 ;
     RECT  52.549 18.144 53.233 18.264 ;
     RECT  53.125 30.384 53.521 36.264 ;
     RECT  53.521 30.336 53.557 36.264 ;
     RECT  52.981 26.208 53.629 28.248 ;
     RECT  53.629 26.208 53.665 28.296 ;
     RECT  53.233 18.144 53.708 18.456 ;
     RECT  52.765 21.072 53.708 21.144 ;
     RECT  53.053 22.368 53.708 22.92 ;
     RECT  52.333 24.24 53.708 24.264 ;
     RECT  53.665 26.208 53.708 28.488 ;
     RECT  53.557 30.336 53.708 36.312 ;
     RECT  51.833 37.44 53.708 39.864 ;
     RECT  53.228 42.672 53.708 43.224 ;
     RECT  53.708 2.148 53.812 75.612 ;
     RECT  53.812 2.418 54.004 75.342 ;
     RECT  54.004 17.712 54.137 18.264 ;
     RECT  54.004 26.64 54.173 28.488 ;
     RECT  54.004 30.336 54.209 39.864 ;
     RECT  54.209 30.336 54.245 38.76 ;
     RECT  54.245 31.968 54.253 38.76 ;
     RECT  54.245 30.336 54.353 30.936 ;
     RECT  54.137 17.856 54.713 18.264 ;
     RECT  54.004 21.12 54.893 21.144 ;
     RECT  54.173 26.64 54.893 28.44 ;
     RECT  54.004 24.96 55.001 25.608 ;
     RECT  54.209 39.84 55.325 39.864 ;
     RECT  55.001 24.96 55.397 24.984 ;
     RECT  54.253 37.584 55.537 38.76 ;
     RECT  54.353 30.912 55.609 30.936 ;
     RECT  54.253 31.968 55.609 36.12 ;
     RECT  55.609 30.912 55.645 36.36 ;
     RECT  55.645 30.096 55.861 36.36 ;
     RECT  55.861 29.856 56.077 36.36 ;
     RECT  55.177 26.016 56.365 26.04 ;
     RECT  54.893 27.072 56.365 28.44 ;
     RECT  55.069 18.48 56.408 18.504 ;
     RECT  56.041 20.88 56.408 20.904 ;
     RECT  55.645 21.984 56.408 22.056 ;
     RECT  56.365 25.824 56.408 28.44 ;
     RECT  56.077 29.76 56.408 36.36 ;
     RECT  55.537 37.584 56.408 39.336 ;
     RECT  56.408 2.148 56.512 75.612 ;
     RECT  56.512 2.418 56.704 75.342 ;
     RECT  56.704 31.68 57.017 35.496 ;
     RECT  56.704 20.88 57.125 21.672 ;
     RECT  56.704 25.824 57.269 27.624 ;
     RECT  56.704 29.76 57.269 30.648 ;
     RECT  57.017 31.68 57.269 32.808 ;
     RECT  57.269 25.824 57.305 25.848 ;
     RECT  56.704 24.384 57.413 24.408 ;
     RECT  56.704 36.48 57.413 38.712 ;
     RECT  57.269 29.808 57.521 30.648 ;
     RECT  57.269 26.832 57.593 27.624 ;
     RECT  57.521 29.856 57.593 30.648 ;
     RECT  57.593 27.312 57.697 27.624 ;
     RECT  57.413 36.48 57.701 38.472 ;
     RECT  57.017 33.792 57.773 35.496 ;
     RECT  57.773 34.08 57.949 35.496 ;
     RECT  57.949 34.08 58.061 36.216 ;
     RECT  56.704 23.136 58.093 23.16 ;
     RECT  57.593 30.096 58.201 30.648 ;
     RECT  57.269 31.68 58.201 32.328 ;
     RECT  58.093 23.136 58.777 23.352 ;
     RECT  58.201 30.096 58.777 32.328 ;
     RECT  57.697 27.312 58.981 28.344 ;
     RECT  58.777 30.096 58.981 33.096 ;
     RECT  58.981 29.616 58.993 33.096 ;
     RECT  57.125 21.168 59.108 21.672 ;
     RECT  58.777 23.136 59.108 23.928 ;
     RECT  58.981 25.104 59.108 25.128 ;
     RECT  58.981 26.208 59.108 28.344 ;
     RECT  58.993 29.52 59.108 33.096 ;
     RECT  58.061 34.08 59.108 36.12 ;
     RECT  57.701 37.632 59.108 38.472 ;
     RECT  59.108 2.148 59.212 75.612 ;
     RECT  59.212 2.418 59.404 75.342 ;
     RECT  59.404 31.488 59.501 38.472 ;
     RECT  59.404 27.408 59.717 30.456 ;
     RECT  59.717 27.888 59.753 30.456 ;
     RECT  59.753 27.984 59.789 30.456 ;
     RECT  59.789 28.272 60.041 30.456 ;
     RECT  60.041 28.464 60.077 30.456 ;
     RECT  59.501 31.488 60.083 35.88 ;
     RECT  59.501 36.912 60.124 38.472 ;
     RECT  60.077 28.656 60.149 30.456 ;
     RECT  60.149 28.656 60.221 30.072 ;
     RECT  60.124 37.872 60.257 38.472 ;
     RECT  60.221 28.656 60.293 29.16 ;
     RECT  60.083 31.488 60.293 35.784 ;
     RECT  60.293 28.656 60.365 28.68 ;
     RECT  60.293 31.488 60.437 32.28 ;
     RECT  60.293 33.648 60.481 35.784 ;
     RECT  60.437 31.872 61.808 32.28 ;
     RECT  60.481 33.936 61.808 35.784 ;
     RECT  60.257 38.448 61.808 38.472 ;
     RECT  61.808 2.148 61.912 75.612 ;
     RECT  61.912 2.418 62.104 75.342 ;
     RECT  62.104 32.256 62.201 32.28 ;
     RECT  62.104 38.448 64.508 38.472 ;
     RECT  64.508 2.148 64.612 75.612 ;
     RECT  64.612 2.418 64.804 75.342 ;
     RECT  64.804 38.448 67.208 38.472 ;
     RECT  67.208 2.148 67.312 75.612 ;
     RECT  67.312 2.418 67.504 75.342 ;
     RECT  67.504 38.448 69.908 38.472 ;
     RECT  69.908 2.148 70.012 75.612 ;
     RECT  70.012 2.418 70.204 75.342 ;
     RECT  70.204 38.448 72.608 38.472 ;
     RECT  72.608 2.148 72.712 75.612 ;
     RECT  72.712 2.418 72.904 75.342 ;
     RECT  72.904 38.448 75.308 38.472 ;
     RECT  75.308 2.148 75.412 75.612 ;
     RECT  75.412 2.418 75.604 75.342 ;
     RECT  75.604 38.448 78.008 38.472 ;
     RECT  78.008 2.148 78.112 75.612 ;
     RECT  78.112 2.418 78.304 75.342 ;
     RECT  78.304 38.448 80.708 38.472 ;
     RECT  80.708 2.148 80.812 75.612 ;
     RECT  80.812 2.418 81.004 75.342 ;
     RECT  81.004 38.448 83.408 38.472 ;
     RECT  83.408 2.148 83.512 75.612 ;
     RECT  83.512 2.418 83.704 75.342 ;
     RECT  83.704 38.448 85.453 38.472 ;
     RECT  85.453 38.448 86.281 39.384 ;
     RECT  86.281 38.352 86.321 39.384 ;
    LAYER M5 ;
     RECT  2.4 2.137 2.52 2.151 ;
     RECT  5.1 2.137 5.22 2.151 ;
     RECT  7.8 2.137 7.92 2.151 ;
     RECT  10.5 2.137 10.62 2.151 ;
     RECT  13.2 2.137 13.32 2.151 ;
     RECT  15.9 2.137 16.02 2.151 ;
     RECT  18.6 2.137 18.72 2.151 ;
     RECT  21.3 2.137 21.42 2.151 ;
     RECT  24 2.137 24.12 2.151 ;
     RECT  26.7 2.137 26.82 2.151 ;
     RECT  29.4 2.137 29.52 2.151 ;
     RECT  32.1 2.137 32.22 2.151 ;
     RECT  34.8 2.137 34.92 2.151 ;
     RECT  37.5 2.137 37.62 2.151 ;
     RECT  40.2 2.137 40.32 2.151 ;
     RECT  42.9 2.137 43.02 2.151 ;
     RECT  45.6 2.137 45.72 2.151 ;
     RECT  48.3 2.137 48.42 2.151 ;
     RECT  51 2.137 51.12 2.151 ;
     RECT  53.7 2.137 53.82 2.151 ;
     RECT  56.4 2.137 56.52 2.151 ;
     RECT  59.1 2.137 59.22 2.151 ;
     RECT  61.8 2.137 61.92 2.151 ;
     RECT  64.5 2.137 64.62 2.151 ;
     RECT  67.2 2.137 67.32 2.151 ;
     RECT  69.9 2.137 70.02 2.151 ;
     RECT  72.6 2.137 72.72 2.151 ;
     RECT  75.3 2.137 75.42 2.151 ;
     RECT  78 2.137 78.12 2.151 ;
     RECT  80.7 2.137 80.82 2.151 ;
     RECT  83.4 2.137 83.52 2.151 ;
     RECT  42.9 2.151 43.212 3.925 ;
     RECT  42.9 3.925 43.32 17.603 ;
     RECT  42.9 17.603 43.212 18.709 ;
     RECT  42.9 18.709 43.944 19.379 ;
     RECT  26.7 2.151 27.012 20.341 ;
     RECT  42.9 19.379 43.848 21.397 ;
     RECT  37.5 2.151 37.812 21.637 ;
     RECT  59.1 2.151 59.412 21.637 ;
     RECT  37.5 21.637 38.52 22.019 ;
     RECT  42.48 21.397 43.848 22.835 ;
     RECT  26.208 20.341 27.012 23.077 ;
     RECT  40.2 2.151 40.512 23.125 ;
     RECT  40.2 23.125 41.448 23.941 ;
     RECT  34.8 2.151 35.112 24.469 ;
     RECT  40.08 23.941 41.448 24.755 ;
     RECT  24 2.151 24.312 25.045 ;
     RECT  25.344 23.077 27.012 25.045 ;
     RECT  40.08 24.755 40.512 25.139 ;
     RECT  58.992 21.637 59.412 25.139 ;
     RECT  42.9 22.835 43.848 25.189 ;
     RECT  42.144 25.189 43.848 25.475 ;
     RECT  34.8 24.469 35.208 25.669 ;
     RECT  56.4 2.151 56.712 26.005 ;
     RECT  59.1 25.139 59.412 26.197 ;
     RECT  34.8 25.669 36.024 26.243 ;
     RECT  56.4 26.005 56.808 26.243 ;
     RECT  42.144 25.475 43.608 26.291 ;
     RECT  42.768 26.291 43.608 26.915 ;
     RECT  18.6 2.151 18.912 27.061 ;
     RECT  24 25.045 27.012 27.061 ;
     RECT  51 2.151 51.312 27.061 ;
     RECT  23.76 27.061 27.012 27.107 ;
     RECT  58.992 26.197 59.412 27.347 ;
     RECT  32.1 2.151 32.412 27.877 ;
     RECT  15.9 2.151 16.212 28.021 ;
     RECT  23.76 27.107 24.312 28.165 ;
     RECT  25.344 27.107 27.012 28.211 ;
     RECT  17.328 26.725 17.352 28.213 ;
     RECT  18.6 27.061 19.032 28.213 ;
     RECT  17.328 28.213 19.032 28.259 ;
     RECT  13.2 2.151 13.512 28.261 ;
     RECT  42.9 26.915 43.608 28.403 ;
     RECT  12.528 28.261 13.512 28.453 ;
     RECT  47.04 27.877 47.064 28.547 ;
     RECT  17.616 28.259 19.032 28.835 ;
     RECT  23.52 28.165 24.312 29.029 ;
     RECT  42.9 28.403 43.368 29.075 ;
     RECT  15.36 28.021 16.212 29.123 ;
     RECT  29.4 2.151 29.712 29.221 ;
     RECT  26.064 28.211 27.012 29.461 ;
     RECT  25.68 29.461 27.012 29.507 ;
     RECT  59.1 27.347 59.412 29.509 ;
     RECT  45.6 2.151 45.912 29.605 ;
     RECT  51 27.061 52.152 29.605 ;
     RECT  59.1 29.509 59.64 29.605 ;
     RECT  56.4 26.243 56.712 29.893 ;
     RECT  7.8 2.151 8.112 30.133 ;
     RECT  17.616 28.835 18.912 30.133 ;
     RECT  9.264 28.837 9.288 30.179 ;
     RECT  15.9 29.123 16.212 30.181 ;
     RECT  29.4 29.221 30.216 30.181 ;
     RECT  56.304 29.893 56.712 30.181 ;
     RECT  41.664 29.365 41.688 30.227 ;
     RECT  22.752 29.029 24.312 30.275 ;
     RECT  28.896 30.181 30.216 30.323 ;
     RECT  56.16 30.181 56.712 30.325 ;
     RECT  42.9 29.075 43.32 30.421 ;
     RECT  42.768 30.421 43.32 30.467 ;
     RECT  11.952 28.453 13.512 30.611 ;
     RECT  56.16 30.325 56.904 30.611 ;
     RECT  38.784 28.789 38.808 30.709 ;
     RECT  40.2 25.139 40.512 30.709 ;
     RECT  23.52 30.275 24.312 30.803 ;
     RECT  25.68 29.507 25.704 30.803 ;
     RECT  38.784 30.709 40.512 30.803 ;
     RECT  37.5 22.019 37.812 30.805 ;
     RECT  12.576 30.611 13.512 31.139 ;
     RECT  17.616 30.133 19.368 31.139 ;
     RECT  34.8 26.243 35.208 31.141 ;
     RECT  39.408 30.803 40.512 31.141 ;
     RECT  56.16 30.611 56.808 31.189 ;
     RECT  15.9 30.181 16.344 31.235 ;
     RECT  28.896 30.323 29.712 31.477 ;
     RECT  28.08 31.477 29.712 31.523 ;
     RECT  58.992 29.605 59.64 31.523 ;
     RECT  44.976 29.605 45.912 31.667 ;
     RECT  21.3 2.151 21.612 31.765 ;
     RECT  31.968 27.877 32.412 31.813 ;
     RECT  59.1 31.523 59.64 31.861 ;
     RECT  39.408 31.141 41.352 31.955 ;
     RECT  55.968 31.189 56.808 31.955 ;
     RECT  55.968 31.955 56.712 32.099 ;
     RECT  18.432 31.139 18.912 32.195 ;
     RECT  50.064 29.605 52.152 32.245 ;
     RECT  53.7 2.151 54.012 32.389 ;
     RECT  10.5 2.151 10.812 32.437 ;
     RECT  40.2 31.955 41.352 32.581 ;
     RECT  49.968 32.245 52.152 32.723 ;
     RECT  53.7 32.389 54.12 32.917 ;
     RECT  6.96 30.133 8.112 33.107 ;
     RECT  15.9 31.235 16.212 33.349 ;
     RECT  21.168 31.765 21.612 33.349 ;
     RECT  42.768 30.467 43.212 33.587 ;
     RECT  10.5 32.437 11.304 33.589 ;
     RECT  40.2 32.581 41.448 33.683 ;
     RECT  59.1 31.861 60.456 33.683 ;
     RECT  34.8 31.141 35.88 33.827 ;
     RECT  26.7 29.507 27.012 33.877 ;
     RECT  15.9 33.349 16.392 33.971 ;
     RECT  53.568 32.917 54.12 34.021 ;
     RECT  10.368 33.589 11.304 34.117 ;
     RECT  29.4 31.523 29.712 34.165 ;
     RECT  53.472 34.021 54.12 34.213 ;
     RECT  53.472 34.213 54.408 34.259 ;
     RECT  28.08 31.523 28.104 34.403 ;
     RECT  53.7 34.259 54.408 34.499 ;
     RECT  7.584 33.107 8.112 34.741 ;
     RECT  45.6 31.667 45.912 34.789 ;
     RECT  10.368 34.117 12.024 34.931 ;
     RECT  6.768 34.741 8.112 35.077 ;
     RECT  31.92 31.813 32.412 35.267 ;
     RECT  44.64 34.789 45.912 35.315 ;
     RECT  31.968 35.267 32.412 35.317 ;
     RECT  39.024 33.589 39.048 35.317 ;
     RECT  37.248 30.805 37.812 35.363 ;
     RECT  50.064 32.723 52.152 35.411 ;
     RECT  31.968 35.317 33.048 35.461 ;
     RECT  34.8 33.827 35.736 35.461 ;
     RECT  20.496 33.349 21.612 35.651 ;
     RECT  5.1 2.151 5.412 35.701 ;
     RECT  42.9 33.587 43.212 35.701 ;
     RECT  50.064 35.411 51.816 35.843 ;
     RECT  59.1 33.683 59.64 35.845 ;
     RECT  10.368 34.931 11.304 35.987 ;
     RECT  6.768 35.077 8.472 36.085 ;
     RECT  10.368 35.987 10.812 36.133 ;
     RECT  22.656 34.501 22.68 36.229 ;
     RECT  24 30.803 24.312 36.229 ;
     RECT  31.968 35.461 35.736 36.275 ;
     RECT  37.344 35.363 37.812 36.275 ;
     RECT  6.72 36.085 8.472 36.373 ;
     RECT  38.784 35.317 39.048 36.373 ;
     RECT  40.2 33.683 41.352 36.373 ;
     RECT  38.784 36.373 41.352 36.419 ;
     RECT  4.512 35.701 5.412 36.421 ;
     RECT  6.72 36.373 8.52 36.421 ;
     RECT  26.592 33.877 27.012 36.469 ;
     RECT  33.936 36.275 35.736 36.469 ;
     RECT  33.936 36.469 35.928 36.515 ;
     RECT  2.4 2.151 2.712 36.517 ;
     RECT  4.512 36.421 8.52 36.517 ;
     RECT  45.6 35.315 45.912 36.517 ;
     RECT  18.48 32.195 18.912 36.563 ;
     RECT  21.168 35.651 21.612 36.563 ;
     RECT  10.272 36.133 10.812 36.565 ;
     RECT  4.512 36.517 8.568 36.613 ;
     RECT  9.552 36.565 10.812 36.613 ;
     RECT  31.968 36.275 32.412 36.613 ;
     RECT  2.4 36.517 2.856 36.661 ;
     RECT  26.304 36.469 27.012 36.901 ;
     RECT  0.288 36.277 0.312 36.947 ;
     RECT  53.7 34.499 54.012 36.949 ;
     RECT  4.512 36.613 10.812 37.091 ;
     RECT  50.064 35.843 51.312 37.091 ;
     RECT  4.512 37.091 5.412 37.285 ;
     RECT  2.4 36.661 3.432 37.331 ;
     RECT  6.72 37.091 10.812 37.381 ;
     RECT  11.808 37.045 11.832 37.381 ;
     RECT  4.416 37.285 5.412 37.475 ;
     RECT  0.384 37.381 0.408 37.619 ;
     RECT  33.984 36.515 35.928 37.619 ;
     RECT  31.632 36.613 32.412 37.667 ;
     RECT  59.1 35.845 60.072 37.667 ;
     RECT  26.16 36.901 27.012 37.859 ;
     RECT  18.6 36.563 18.912 37.861 ;
     RECT  53.7 36.949 54.216 37.907 ;
     RECT  6.72 37.381 11.832 38.147 ;
     RECT  45.6 36.517 46.008 38.149 ;
     RECT  48.3 2.151 48.612 38.149 ;
     RECT  29.232 34.165 29.712 38.243 ;
     RECT  48.192 38.149 49.08 38.291 ;
     RECT  32.1 37.667 32.412 38.437 ;
     RECT  0.144 38.149 0.168 38.483 ;
     RECT  5.1 37.475 5.412 38.485 ;
     RECT  45.408 38.149 46.008 38.531 ;
     RECT  18.6 37.861 19.032 38.579 ;
     RECT  5.1 38.485 5.544 38.677 ;
     RECT  6.72 38.147 9.24 38.677 ;
     RECT  18.6 38.579 18.912 38.677 ;
     RECT  53.7 37.907 54.012 38.677 ;
     RECT  10.272 38.147 11.832 38.723 ;
     RECT  2.4 37.331 2.856 38.725 ;
     RECT  10.32 38.723 11.832 38.819 ;
     RECT  39.312 36.419 41.352 38.819 ;
     RECT  30.912 38.005 30.936 39.011 ;
     RECT  15.9 33.971 16.212 39.061 ;
     RECT  17.376 35.701 17.4 39.061 ;
     RECT  21.3 36.563 21.612 39.109 ;
     RECT  5.1 38.677 9.24 39.443 ;
     RECT  2.4 38.725 3.192 39.637 ;
     RECT  34.8 37.619 35.736 39.877 ;
     RECT  42.336 35.701 43.212 39.923 ;
     RECT  42.9 39.923 43.212 40.021 ;
     RECT  15.9 39.061 17.4 40.115 ;
     RECT  29.4 38.243 29.712 40.405 ;
     RECT  37.5 36.275 37.812 40.405 ;
     RECT  2.4 39.637 3.432 40.499 ;
     RECT  0.336 39.541 0.36 40.549 ;
     RECT  5.1 39.443 9.144 40.597 ;
     RECT  45.408 38.531 45.912 40.597 ;
     RECT  0.288 40.549 0.36 40.645 ;
     RECT  42.9 40.021 44.136 40.691 ;
     RECT  0.288 40.645 0.696 40.787 ;
     RECT  10.368 38.819 11.832 40.835 ;
     RECT  45.408 40.597 46.152 40.835 ;
     RECT  5.1 40.597 9.288 40.931 ;
     RECT  34.8 39.877 35.88 41.171 ;
     RECT  2.4 40.499 3.384 41.219 ;
     RECT  17.376 40.115 17.4 41.509 ;
     RECT  18.48 38.677 18.912 41.509 ;
     RECT  32.1 38.437 32.904 41.509 ;
     RECT  11.808 40.835 11.832 41.557 ;
     RECT  11.808 41.557 12.024 41.603 ;
     RECT  22.656 36.229 24.312 41.651 ;
     RECT  28.608 40.405 29.712 41.651 ;
     RECT  29.4 41.651 29.712 41.797 ;
     RECT  0.288 40.787 0.408 41.843 ;
     RECT  45.6 40.835 46.152 41.891 ;
     RECT  5.1 40.931 9.144 41.893 ;
     RECT  10.368 40.835 10.812 41.893 ;
     RECT  5.1 41.893 10.812 41.939 ;
     RECT  15.9 40.115 16.212 42.085 ;
     RECT  17.376 41.509 18.912 42.133 ;
     RECT  29.4 41.797 30.264 42.133 ;
     RECT  32.1 41.509 33.048 42.133 ;
     RECT  51 37.091 51.312 42.325 ;
     RECT  0.24 41.941 0.264 42.419 ;
     RECT  15.696 42.085 16.212 42.515 ;
     RECT  5.1 41.939 8.232 42.611 ;
     RECT  15.9 42.515 16.212 42.709 ;
     RECT  17.376 42.133 19.224 42.709 ;
     RECT  42.9 40.691 43.212 42.709 ;
     RECT  48.3 38.291 48.612 42.709 ;
     RECT  12 41.603 12.024 42.755 ;
     RECT  29.4 42.133 33.048 42.755 ;
     RECT  40.2 38.819 41.352 42.757 ;
     RECT  9.6 41.939 10.812 42.803 ;
     RECT  9.744 42.803 10.812 42.995 ;
     RECT  34.8 41.171 35.256 42.995 ;
     RECT  15.9 42.709 19.224 42.997 ;
     RECT  15.9 42.997 19.272 43.043 ;
     RECT  13.2 31.139 13.512 43.045 ;
     RECT  53.28 38.677 54.012 43.235 ;
     RECT  21.12 39.109 21.612 43.285 ;
     RECT  40.2 42.757 41.448 43.331 ;
     RECT  42.48 42.709 43.212 43.379 ;
     RECT  37.152 40.405 37.812 43.525 ;
     RECT  21.12 43.285 21.864 43.669 ;
     RECT  23.088 41.651 24.312 43.669 ;
     RECT  9.984 42.995 10.812 43.811 ;
     RECT  31.2 42.755 32.904 43.811 ;
     RECT  37.152 43.525 38.184 43.813 ;
     RECT  17.712 43.043 19.272 43.859 ;
     RECT  36.768 43.813 38.184 44.099 ;
     RECT  5.1 42.611 8.112 44.195 ;
     RECT  42.72 43.379 43.212 44.387 ;
     RECT  15.9 43.043 16.536 44.437 ;
     RECT  34.8 42.995 35.112 44.437 ;
     RECT  42.9 44.387 43.212 44.437 ;
     RECT  32.1 43.811 32.904 44.483 ;
     RECT  40.2 43.331 41.352 44.677 ;
     RECT  40.2 44.677 41.592 44.723 ;
     RECT  36.768 44.099 37.944 44.915 ;
     RECT  34.08 44.437 35.112 44.965 ;
     RECT  36.768 44.915 37.812 44.965 ;
     RECT  33.648 44.965 37.812 45.011 ;
     RECT  15.9 44.437 17.112 45.013 ;
     RECT  15.9 45.013 17.208 45.155 ;
     RECT  26.7 37.859 27.012 45.301 ;
     RECT  33.648 45.011 33.672 45.827 ;
     RECT  21.12 43.669 24.312 46.067 ;
     RECT  5.1 44.195 6.312 46.069 ;
     RECT  7.8 44.195 8.112 46.069 ;
     RECT  21.12 46.067 21.612 46.069 ;
     RECT  44.304 43.861 44.328 46.259 ;
     RECT  21.072 46.069 21.612 46.453 ;
     RECT  18.288 43.859 19.272 46.549 ;
     RECT  42.9 44.437 43.32 46.693 ;
     RECT  48.3 42.709 48.744 46.693 ;
     RECT  12.336 43.045 13.512 46.787 ;
     RECT  26.208 45.301 27.012 46.787 ;
     RECT  34.8 45.011 37.812 46.883 ;
     RECT  40.2 44.723 40.512 46.885 ;
     RECT  41.568 44.723 41.592 46.885 ;
     RECT  21.024 46.453 21.612 47.123 ;
     RECT  5.1 46.069 8.112 47.173 ;
     RECT  42.9 46.693 43.896 47.315 ;
     RECT  22.656 46.067 24.312 47.363 ;
     RECT  26.7 46.787 27.012 47.845 ;
     RECT  48.3 46.693 48.792 47.845 ;
     RECT  42.9 47.315 43.752 47.891 ;
     RECT  4.704 47.173 8.112 48.179 ;
     RECT  10.5 43.811 10.812 48.373 ;
     RECT  45.6 41.891 45.912 48.373 ;
     RECT  21.12 47.123 21.612 48.421 ;
     RECT  34.8 46.883 35.976 48.421 ;
     RECT  12.528 46.787 13.512 48.469 ;
     RECT  14.544 48.229 14.568 48.469 ;
     RECT  34.8 48.421 36.168 48.469 ;
     RECT  37.152 46.883 37.812 48.469 ;
     RECT  45.504 48.373 45.912 48.515 ;
     RECT  12.528 48.469 14.568 48.805 ;
     RECT  34.8 48.469 37.812 48.949 ;
     RECT  42.9 47.891 43.212 48.997 ;
     RECT  21.12 48.421 21.864 49.043 ;
     RECT  18.288 46.549 19.848 49.189 ;
     RECT  47.664 47.845 48.792 49.475 ;
     RECT  18.288 49.189 19.944 49.477 ;
     RECT  5.1 48.179 8.112 49.571 ;
     RECT  5.1 49.571 6.312 49.619 ;
     RECT  15.9 45.155 16.536 49.619 ;
     RECT  34.8 48.949 38.328 49.907 ;
     RECT  11.904 48.805 14.568 50.051 ;
     RECT  12.048 50.051 14.568 50.195 ;
     RECT  18.192 49.477 19.944 50.195 ;
     RECT  42.768 48.997 43.212 50.195 ;
     RECT  34.8 49.907 37.812 50.243 ;
     RECT  5.1 49.619 5.64 50.341 ;
     RECT  26.7 47.845 27.336 50.435 ;
     RECT  23.184 47.363 24.312 50.677 ;
     RECT  34.8 50.243 36.168 50.677 ;
     RECT  37.152 50.243 37.812 50.723 ;
     RECT  21.12 49.043 21.612 50.867 ;
     RECT  42.9 50.195 43.212 51.157 ;
     RECT  4.848 50.341 5.64 51.347 ;
     RECT  23.184 50.677 24.552 51.347 ;
     RECT  34.224 50.677 36.168 51.347 ;
     RECT  12.048 50.195 13.512 51.395 ;
     RECT  12.528 51.395 13.512 51.491 ;
     RECT  40.2 46.885 41.592 51.637 ;
     RECT  34.8 51.347 36.168 51.779 ;
     RECT  10.32 48.373 10.812 51.877 ;
     RECT  4.848 51.347 5.544 51.923 ;
     RECT  18.432 50.195 19.944 51.923 ;
     RECT  47.28 51.253 47.304 51.923 ;
     RECT  48.3 49.475 48.792 51.923 ;
     RECT  21.168 50.867 21.612 51.971 ;
     RECT  14.544 50.195 14.568 52.211 ;
     RECT  40.2 51.637 41.688 52.261 ;
     RECT  42.768 51.157 43.212 52.261 ;
     RECT  37.5 50.723 37.812 52.405 ;
     RECT  38.928 51.733 38.952 52.405 ;
     RECT  15.9 49.619 16.212 52.453 ;
     RECT  30.72 52.021 30.744 52.499 ;
     RECT  12.816 51.491 13.512 52.739 ;
     RECT  50.112 42.325 51.312 52.883 ;
     RECT  2.4 41.219 2.712 52.885 ;
     RECT  18.432 51.923 18.912 52.981 ;
     RECT  19.92 51.923 19.944 52.981 ;
     RECT  34.8 51.779 35.112 52.981 ;
     RECT  36.144 51.779 36.168 52.981 ;
     RECT  18.432 52.981 19.944 53.027 ;
     RECT  37.5 52.405 38.952 53.075 ;
     RECT  40.2 52.261 43.212 53.075 ;
     RECT  40.2 53.075 41.592 53.123 ;
     RECT  25.296 52.741 25.32 53.315 ;
     RECT  10.32 51.877 11.304 53.509 ;
     RECT  5.1 51.923 5.544 53.555 ;
     RECT  15.9 52.453 16.728 53.555 ;
     RECT  18.432 53.027 19.704 53.555 ;
     RECT  48.3 51.923 48.612 53.557 ;
     RECT  34.8 52.981 36.168 53.603 ;
     RECT  14.832 53.557 14.856 53.843 ;
     RECT  18.6 53.555 19.704 54.083 ;
     RECT  12.912 52.739 13.512 54.085 ;
     RECT  50.4 52.883 51.312 54.179 ;
     RECT  37.5 53.075 37.812 54.325 ;
     RECT  38.928 53.075 38.952 54.325 ;
     RECT  10.32 53.509 11.4 54.371 ;
     RECT  32.1 44.483 32.412 54.565 ;
     RECT  2.4 52.885 3.192 54.611 ;
     RECT  12.912 54.085 13.608 54.661 ;
     RECT  44.448 52.837 44.472 54.661 ;
     RECT  45.6 48.515 45.912 54.661 ;
     RECT  44.448 54.661 45.912 54.707 ;
     RECT  12.912 54.661 14.568 54.755 ;
     RECT  31.968 54.565 32.412 54.755 ;
     RECT  37.5 54.325 38.952 54.899 ;
     RECT  21.3 51.971 21.612 55.141 ;
     RECT  13.2 54.755 14.568 55.283 ;
     RECT  48.3 53.557 48.744 55.331 ;
     RECT  9.312 50.917 9.336 55.427 ;
     RECT  5.1 53.555 5.412 55.429 ;
     RECT  10.32 54.371 11.352 55.475 ;
     RECT  45.264 54.707 45.912 55.525 ;
     RECT  34.8 53.603 35.112 55.717 ;
     RECT  5.1 55.429 5.976 55.813 ;
     RECT  45.264 55.525 46.104 55.907 ;
     RECT  45.6 55.907 46.104 56.243 ;
     RECT  4.656 55.813 5.976 56.437 ;
     RECT  42.768 53.075 43.212 56.485 ;
     RECT  42.768 56.485 43.32 56.531 ;
     RECT  26.7 50.435 27.144 56.677 ;
     RECT  36.144 53.603 36.168 56.869 ;
     RECT  44.592 56.053 44.616 57.011 ;
     RECT  30.816 56.869 30.84 57.013 ;
     RECT  4.656 56.437 6.312 57.059 ;
     RECT  13.2 55.283 14.424 57.059 ;
     RECT  30.816 57.013 30.984 57.059 ;
     RECT  33.408 56.389 33.432 57.443 ;
     RECT  34.704 55.717 35.112 57.443 ;
     RECT  17.472 56.917 17.496 57.587 ;
     RECT  37.5 54.899 37.812 57.925 ;
     RECT  38.928 54.899 38.952 57.925 ;
     RECT  30.96 57.059 30.984 58.117 ;
     RECT  36.144 56.869 36.456 58.163 ;
     RECT  4.704 57.059 6.312 58.403 ;
     RECT  7.8 49.571 8.112 58.645 ;
     RECT  7.8 58.645 8.472 58.787 ;
     RECT  30.816 58.117 30.984 58.883 ;
     RECT  23.184 51.347 24.312 58.981 ;
     RECT  37.5 57.925 38.952 59.029 ;
     RECT  40.2 53.123 40.872 59.029 ;
     RECT  4.704 58.403 5.412 59.075 ;
     RECT  37.5 59.029 40.872 59.075 ;
     RECT  18.6 54.083 18.912 59.077 ;
     RECT  29.4 42.755 29.712 59.173 ;
     RECT  30.816 58.883 30.84 59.219 ;
     RECT  10.32 55.475 10.812 59.221 ;
     RECT  34.8 57.443 35.112 59.605 ;
     RECT  18.192 59.077 18.912 59.701 ;
     RECT  26.7 56.677 27.336 59.797 ;
     RECT  38.928 59.075 40.872 59.987 ;
     RECT  48.3 55.331 48.612 59.989 ;
     RECT  49.872 55.813 49.896 59.989 ;
     RECT  47.04 56.917 47.064 60.131 ;
     RECT  13.2 57.059 13.608 60.179 ;
     RECT  33.936 59.605 35.112 60.419 ;
     RECT  38.976 59.987 40.872 60.419 ;
     RECT  21.168 55.141 21.612 60.469 ;
     RECT  10.224 59.221 10.812 60.515 ;
     RECT  17.76 59.701 18.912 60.611 ;
     RECT  48.3 59.989 49.896 60.803 ;
     RECT  26.7 59.797 27.432 60.851 ;
     RECT  32.1 54.755 32.412 60.853 ;
     RECT  45.6 56.243 45.912 60.949 ;
     RECT  23.184 58.981 24.744 61.043 ;
     RECT  18.192 60.611 18.912 61.091 ;
     RECT  23.184 61.043 24.312 61.139 ;
     RECT  31.296 60.853 32.412 61.141 ;
     RECT  23.328 61.139 24.312 61.235 ;
     RECT  34.8 60.419 35.112 61.477 ;
     RECT  36.144 58.163 36.168 61.477 ;
     RECT  34.8 61.477 36.168 61.525 ;
     RECT  31.296 61.141 33 61.619 ;
     RECT  45.024 60.949 45.912 61.763 ;
     RECT  38.976 60.419 39 61.813 ;
     RECT  38.784 61.813 39 61.955 ;
     RECT  26.7 60.851 27.012 62.005 ;
     RECT  4.896 59.075 5.412 62.051 ;
     RECT  32.1 61.619 33 62.147 ;
     RECT  34.176 61.525 36.168 62.195 ;
     RECT  24 61.235 24.312 62.341 ;
     RECT  13.2 60.179 13.512 62.437 ;
     RECT  14.832 60.133 14.856 62.483 ;
     RECT  42.9 56.531 43.32 62.677 ;
     RECT  7.8 58.787 8.112 62.725 ;
     RECT  9.312 62.629 9.336 62.725 ;
     RECT  34.176 62.195 35.112 62.771 ;
     RECT  32.1 62.147 32.412 62.821 ;
     RECT  21.12 60.469 21.612 63.109 ;
     RECT  18.6 61.091 18.912 63.205 ;
     RECT  24 62.341 25.176 63.299 ;
     RECT  26.7 62.005 27.144 63.299 ;
     RECT  42.528 62.677 43.32 63.779 ;
     RECT  18.24 63.205 19.8 63.781 ;
     RECT  21.12 63.109 21.912 63.827 ;
     RECT  7.8 62.725 9.336 63.875 ;
     RECT  18.24 63.781 20.04 64.067 ;
     RECT  26.7 63.299 27.012 64.165 ;
     RECT  34.8 62.771 35.112 64.357 ;
     RECT  36.144 62.195 36.168 64.357 ;
     RECT  9.312 63.875 9.336 64.451 ;
     RECT  13.104 62.437 13.512 64.451 ;
     RECT  13.2 64.451 13.512 64.741 ;
     RECT  21.3 63.827 21.912 64.883 ;
     RECT  31.2 62.821 32.412 64.933 ;
     RECT  31.056 64.933 32.412 64.979 ;
     RECT  34.8 64.357 36.168 65.173 ;
     RECT  26.592 64.165 27.012 65.219 ;
     RECT  38.976 61.955 39 65.219 ;
     RECT  15.9 53.555 16.212 65.509 ;
     RECT  21.3 64.883 21.864 65.939 ;
     RECT  31.056 64.979 31.08 65.939 ;
     RECT  24 63.299 24.312 66.085 ;
     RECT  28.608 59.173 29.712 66.085 ;
     RECT  32.1 64.979 32.412 66.085 ;
     RECT  18.24 64.067 18.912 66.467 ;
     RECT  24 66.085 24.456 66.661 ;
     RECT  28.512 66.085 29.712 66.755 ;
     RECT  32.1 66.085 33 67.187 ;
     RECT  20.016 64.067 20.04 67.283 ;
     RECT  24 66.661 25.128 67.283 ;
     RECT  34.8 65.173 36.408 67.283 ;
     RECT  40.2 60.419 40.872 67.333 ;
     RECT  36.144 67.283 36.408 67.429 ;
     RECT  37.5 59.075 37.812 67.429 ;
     RECT  13.2 64.741 13.608 67.619 ;
     RECT  30.72 67.285 30.744 68.099 ;
     RECT  28.608 66.755 29.712 68.243 ;
     RECT  32.1 67.187 32.412 68.341 ;
     RECT  33.792 68.245 33.816 68.341 ;
     RECT  42.9 63.779 43.32 68.341 ;
     RECT  15.9 65.509 17.112 68.435 ;
     RECT  36.144 67.429 37.812 68.531 ;
     RECT  39.456 67.333 40.872 68.915 ;
     RECT  21.3 65.939 21.612 68.917 ;
     RECT  45.6 61.763 45.912 68.965 ;
     RECT  31.296 68.341 33.816 69.349 ;
     RECT  26.7 65.219 27.012 69.493 ;
     RECT  21.12 68.917 21.612 69.587 ;
     RECT  42 68.341 43.32 69.587 ;
     RECT  45.6 68.965 46.152 69.731 ;
     RECT  34.8 67.283 35.112 69.973 ;
     RECT  36.144 68.531 36.408 69.973 ;
     RECT  30.864 69.349 33.816 70.069 ;
     RECT  34.8 69.973 36.408 70.069 ;
     RECT  30.864 70.069 36.408 70.163 ;
     RECT  40.08 68.915 40.872 70.163 ;
     RECT  48.3 60.803 49.224 70.259 ;
     RECT  28.992 68.243 29.712 70.549 ;
     RECT  30.864 70.163 36.168 70.549 ;
     RECT  28.992 70.549 36.168 70.739 ;
     RECT  26.7 69.493 27.912 70.835 ;
     RECT  42 69.587 43.212 71.221 ;
     RECT  40.08 70.163 40.512 71.267 ;
     RECT  28.992 70.739 35.256 71.315 ;
     RECT  42 71.221 43.944 71.315 ;
     RECT  42.9 71.315 43.944 71.891 ;
     RECT  26.7 70.835 27.012 73.477 ;
     RECT  26.7 73.477 27.912 74.053 ;
     RECT  29.4 71.315 35.256 74.053 ;
     RECT  26.7 74.053 35.256 74.147 ;
     RECT  26.7 74.147 35.112 74.963 ;
     RECT  2.4 54.611 2.712 75.609 ;
     RECT  5.1 62.051 5.412 75.609 ;
     RECT  7.8 63.875 8.112 75.609 ;
     RECT  10.5 60.515 10.812 75.609 ;
     RECT  13.2 67.619 13.512 75.609 ;
     RECT  15.9 68.435 16.212 75.609 ;
     RECT  18.6 66.467 18.912 75.609 ;
     RECT  21.3 69.587 21.612 75.609 ;
     RECT  24 67.283 24.312 75.609 ;
     RECT  26.7 74.963 27.012 75.609 ;
     RECT  28.032 74.963 35.112 75.609 ;
     RECT  37.5 68.531 37.812 75.609 ;
     RECT  40.2 71.267 40.512 75.609 ;
     RECT  42.9 71.891 43.212 75.609 ;
     RECT  45.6 69.731 45.912 75.609 ;
     RECT  48.3 70.259 48.612 75.609 ;
     RECT  51 54.179 51.312 75.609 ;
     RECT  53.7 43.235 54.012 75.609 ;
     RECT  56.4 32.099 56.712 75.609 ;
     RECT  59.1 37.667 59.412 75.609 ;
     RECT  61.8 2.151 62.112 75.609 ;
     RECT  64.5 2.151 64.812 75.609 ;
     RECT  67.2 2.151 67.512 75.609 ;
     RECT  69.9 2.151 70.212 75.609 ;
     RECT  72.6 2.151 72.912 75.609 ;
     RECT  75.3 2.151 75.612 75.609 ;
     RECT  78 2.151 78.312 75.609 ;
     RECT  80.7 2.151 81.012 75.609 ;
     RECT  83.4 2.151 83.712 75.609 ;
     RECT  2.4 75.609 2.52 75.623 ;
     RECT  5.1 75.609 5.22 75.623 ;
     RECT  7.8 75.609 7.92 75.623 ;
     RECT  10.5 75.609 10.62 75.623 ;
     RECT  13.2 75.609 13.32 75.623 ;
     RECT  15.9 75.609 16.02 75.623 ;
     RECT  18.6 75.609 18.72 75.623 ;
     RECT  21.3 75.609 21.42 75.623 ;
     RECT  24 75.609 24.12 75.623 ;
     RECT  26.7 75.609 26.82 75.623 ;
     RECT  28.032 75.609 34.92 75.623 ;
     RECT  37.5 75.609 37.62 75.623 ;
     RECT  40.2 75.609 40.32 75.623 ;
     RECT  42.9 75.609 43.176 75.623 ;
     RECT  45.6 75.609 45.72 75.623 ;
     RECT  48.3 75.609 48.42 75.623 ;
     RECT  51 75.609 51.12 75.623 ;
     RECT  53.7 75.609 53.82 75.623 ;
     RECT  56.4 75.609 56.52 75.623 ;
     RECT  59.1 75.609 59.22 75.623 ;
     RECT  61.8 75.609 61.92 75.623 ;
     RECT  64.5 75.609 64.62 75.623 ;
     RECT  67.2 75.609 67.32 75.623 ;
     RECT  69.9 75.609 70.02 75.623 ;
     RECT  72.6 75.609 72.72 75.623 ;
     RECT  75.3 75.609 75.42 75.623 ;
     RECT  78 75.609 78.12 75.623 ;
     RECT  80.7 75.609 80.82 75.623 ;
     RECT  83.4 75.609 83.52 75.623 ;
     RECT  28.032 75.623 34.104 77.221 ;
     RECT  28.032 77.221 34.296 77.712 ;
     RECT  43.212 17.603 43.32 18.709 ;
     RECT  42.48 22.835 42.9 23.125 ;
     RECT  24.312 23.077 25.344 25.045 ;
     RECT  41.448 23.125 42.9 24.755 ;
     RECT  42.144 24.755 42.9 25.189 ;
     RECT  58.992 25.139 59.1 26.197 ;
     RECT  36.024 25.669 37.5 26.243 ;
     RECT  16.212 26.725 17.328 28.259 ;
     RECT  17.352 26.725 18.6 28.213 ;
     RECT  24.312 27.107 25.344 28.211 ;
     RECT  45.912 27.877 47.04 28.547 ;
     RECT  47.064 27.877 48.3 28.547 ;
     RECT  24.312 28.211 26.064 29.461 ;
     RECT  16.212 28.259 17.616 30.181 ;
     RECT  10.812 28.453 11.952 30.611 ;
     RECT  37.812 28.789 38.784 30.803 ;
     RECT  38.808 28.789 40.2 30.709 ;
     RECT  18.912 28.835 19.032 30.133 ;
     RECT  8.112 28.837 9.264 30.179 ;
     RECT  9.288 28.837 10.5 30.179 ;
     RECT  21.612 29.029 22.752 30.275 ;
     RECT  40.512 29.365 41.664 30.227 ;
     RECT  41.688 29.365 42.9 30.227 ;
     RECT  24.312 29.461 25.68 30.803 ;
     RECT  25.704 29.507 26.7 30.803 ;
     RECT  48.612 29.605 50.064 32.245 ;
     RECT  16.344 30.181 17.616 31.139 ;
     RECT  40.512 30.227 42.9 30.421 ;
     RECT  40.512 30.421 42.768 31.141 ;
     RECT  35.88 31.141 37.248 33.827 ;
     RECT  41.352 31.141 42.768 32.581 ;
     RECT  27.012 31.477 28.08 34.403 ;
     RECT  28.104 31.523 29.4 34.165 ;
     RECT  60.456 31.861 61.8 33.683 ;
     RECT  48.612 32.245 49.968 32.723 ;
     RECT  41.448 32.581 42.768 33.587 ;
     RECT  48.612 32.723 50.064 37.091 ;
     RECT  52.152 32.917 53.568 34.021 ;
     RECT  41.448 33.587 42.9 33.683 ;
     RECT  37.812 33.589 39.024 35.317 ;
     RECT  39.048 33.589 40.2 36.373 ;
     RECT  35.736 33.827 37.248 35.363 ;
     RECT  52.152 34.021 53.472 34.259 ;
     RECT  12.024 34.117 13.2 34.931 ;
     RECT  28.104 34.165 29.232 34.403 ;
     RECT  21.612 34.501 22.656 41.651 ;
     RECT  22.68 34.501 24 36.229 ;
     RECT  5.412 34.741 6.768 36.085 ;
     RECT  43.212 34.789 44.64 35.315 ;
     RECT  31.92 35.267 31.968 36.613 ;
     RECT  37.812 35.317 38.784 36.419 ;
     RECT  35.736 35.363 37.344 36.275 ;
     RECT  16.212 35.701 17.376 39.061 ;
     RECT  17.4 35.701 18.48 36.563 ;
     RECT  41.352 35.701 42.336 39.923 ;
     RECT  10.812 35.987 11.304 37.045 ;
     RECT  5.412 36.085 6.72 36.421 ;
     RECT  32.412 36.275 33.936 36.515 ;
     RECT  35.736 36.275 35.928 36.469 ;
     RECT  37.812 36.419 39.312 38.819 ;
     RECT  17.4 36.563 18.6 38.677 ;
     RECT  8.568 36.565 9.552 36.613 ;
     RECT  3.432 36.661 4.512 37.285 ;
     RECT  10.812 37.045 11.808 37.381 ;
     RECT  11.832 37.045 13.2 41.557 ;
     RECT  5.412 37.091 6.72 38.485 ;
     RECT  48.612 37.091 49.08 38.149 ;
     RECT  3.432 37.285 4.416 37.331 ;
     RECT  2.856 37.331 4.416 37.475 ;
     RECT  2.856 37.475 3.192 38.725 ;
     RECT  31.632 37.667 32.1 38.005 ;
     RECT  29.712 38.005 30.912 39.011 ;
     RECT  30.936 38.005 32.1 39.011 ;
     RECT  9.24 38.147 10.272 38.723 ;
     RECT  5.544 38.485 6.72 38.677 ;
     RECT  17.4 38.677 18.48 41.509 ;
     RECT  9.24 38.723 10.32 38.819 ;
     RECT  9.24 38.819 10.368 39.443 ;
     RECT  9.144 39.443 10.368 40.597 ;
     RECT  44.136 40.021 45.408 40.691 ;
     RECT  16.212 40.115 17.376 42.709 ;
     RECT  35.88 40.405 37.152 41.171 ;
     RECT  9.288 40.597 10.368 40.931 ;
     RECT  10.812 40.835 11.808 41.603 ;
     RECT  9.144 40.931 10.368 41.893 ;
     RECT  12.024 41.557 13.2 42.755 ;
     RECT  10.812 41.603 12 42.755 ;
     RECT  21.612 41.651 23.088 43.285 ;
     RECT  8.232 41.939 9.6 42.611 ;
     RECT  48.612 42.325 50.112 42.709 ;
     RECT  8.112 42.611 9.6 42.803 ;
     RECT  41.352 42.709 42.48 42.757 ;
     RECT  48.744 42.709 50.112 46.693 ;
     RECT  10.812 42.755 13.2 43.045 ;
     RECT  29.712 42.755 31.2 43.811 ;
     RECT  41.448 42.757 42.48 43.331 ;
     RECT  16.536 43.043 17.712 43.859 ;
     RECT  10.812 43.045 12.336 46.787 ;
     RECT  21.864 43.285 23.088 43.669 ;
     RECT  41.352 43.331 42.48 43.379 ;
     RECT  41.352 43.379 42.72 44.387 ;
     RECT  16.536 43.859 18.288 44.437 ;
     RECT  43.212 43.861 44.304 44.437 ;
     RECT  44.328 43.861 45.6 46.259 ;
     RECT  6.312 44.195 7.8 46.069 ;
     RECT  41.352 44.387 42.9 44.677 ;
     RECT  17.112 44.437 18.288 45.013 ;
     RECT  32.904 44.437 34.08 44.483 ;
     RECT  43.32 44.437 44.304 46.259 ;
     RECT  32.412 44.483 34.08 44.965 ;
     RECT  41.592 44.677 42.9 48.997 ;
     RECT  40.512 44.723 41.568 46.885 ;
     RECT  32.412 44.965 33.648 45.827 ;
     RECT  33.672 45.011 34.8 45.827 ;
     RECT  17.208 45.013 18.288 45.155 ;
     RECT  21.612 46.067 22.656 47.363 ;
     RECT  43.32 46.259 43.896 46.693 ;
     RECT  19.848 46.549 21.024 47.123 ;
     RECT  48.792 46.693 50.112 51.923 ;
     RECT  35.976 46.883 37.152 48.421 ;
     RECT  19.848 47.123 21.12 49.189 ;
     RECT  21.612 47.363 23.184 48.421 ;
     RECT  13.512 48.229 14.544 48.469 ;
     RECT  14.568 48.229 15.9 52.211 ;
     RECT  21.864 48.421 23.184 49.043 ;
     RECT  36.168 48.421 37.152 48.469 ;
     RECT  10.812 48.805 11.904 50.051 ;
     RECT  41.592 48.997 42.768 50.195 ;
     RECT  19.944 49.189 21.12 50.867 ;
     RECT  6.312 49.571 7.8 49.619 ;
     RECT  10.812 50.051 12.048 51.395 ;
     RECT  13.512 50.195 14.544 52.211 ;
     RECT  41.592 50.195 42.9 51.157 ;
     RECT  36.168 50.243 37.152 50.723 ;
     RECT  36.168 50.723 37.5 56.869 ;
     RECT  19.944 50.867 21.168 51.971 ;
     RECT  8.112 50.917 9.312 55.427 ;
     RECT  9.336 50.917 10.32 55.427 ;
     RECT  41.592 51.157 42.768 51.637 ;
     RECT  45.912 51.253 47.28 51.923 ;
     RECT  47.304 51.253 48.3 51.923 ;
     RECT  24.312 51.347 24.552 52.741 ;
     RECT  10.812 51.395 12.528 51.491 ;
     RECT  10.812 51.491 12.816 51.877 ;
     RECT  41.688 51.637 42.768 52.261 ;
     RECT  37.812 51.733 38.928 52.405 ;
     RECT  38.952 51.733 40.2 59.029 ;
     RECT  35.112 51.779 36.144 52.981 ;
     RECT  11.304 51.877 12.816 52.739 ;
     RECT  18.912 51.923 19.92 52.981 ;
     RECT  48.612 51.923 50.112 52.883 ;
     RECT  19.944 51.971 21.3 53.027 ;
     RECT  29.712 52.021 30.72 52.499 ;
     RECT  30.744 52.021 32.1 52.499 ;
     RECT  13.512 52.211 15.9 53.557 ;
     RECT  11.304 52.739 12.912 53.509 ;
     RECT  24.312 52.741 25.296 53.315 ;
     RECT  25.32 52.741 26.7 53.315 ;
     RECT  43.212 52.837 44.448 54.707 ;
     RECT  44.472 52.837 45.6 54.661 ;
     RECT  48.612 52.883 48.744 53.557 ;
     RECT  37.812 53.075 38.928 54.325 ;
     RECT  41.592 53.075 42.768 53.123 ;
     RECT  11.4 53.509 12.912 54.371 ;
     RECT  13.512 53.557 14.832 53.843 ;
     RECT  14.856 53.557 15.9 53.843 ;
     RECT  35.112 53.603 36.144 61.477 ;
     RECT  13.512 53.843 15.9 54.085 ;
     RECT  13.608 54.085 15.9 54.661 ;
     RECT  14.568 54.661 15.9 55.283 ;
     RECT  43.212 54.707 45.264 55.907 ;
     RECT  37.812 54.899 38.928 57.925 ;
     RECT  14.424 55.283 15.9 57.059 ;
     RECT  48.612 55.331 48.744 55.813 ;
     RECT  48.612 55.813 49.872 59.989 ;
     RECT  49.896 55.813 51 60.803 ;
     RECT  43.212 55.907 45.6 56.053 ;
     RECT  43.212 56.053 44.592 56.485 ;
     RECT  44.616 56.053 45.6 57.011 ;
     RECT  45.912 56.243 46.104 56.917 ;
     RECT  32.412 56.389 33.408 57.443 ;
     RECT  33.432 56.389 34.704 57.443 ;
     RECT  6.312 56.437 7.8 58.403 ;
     RECT  43.32 56.485 44.592 57.011 ;
     RECT  29.712 56.869 30.816 57.059 ;
     RECT  30.84 56.869 32.1 57.013 ;
     RECT  36.456 56.869 37.5 58.163 ;
     RECT  16.212 56.917 17.472 57.587 ;
     RECT  17.496 56.917 18.6 57.587 ;
     RECT  45.912 56.917 47.04 60.131 ;
     RECT  47.064 56.917 48.3 60.131 ;
     RECT  30.984 57.013 32.1 58.883 ;
     RECT  29.712 57.059 30.96 58.117 ;
     RECT  18.192 57.587 18.6 59.077 ;
     RECT  29.712 58.117 30.816 59.219 ;
     RECT  36.168 58.163 37.5 65.173 ;
     RECT  30.84 58.883 32.1 59.219 ;
     RECT  37.812 59.075 38.928 59.987 ;
     RECT  27.336 59.173 28.608 59.797 ;
     RECT  32.412 59.605 33.936 60.419 ;
     RECT  27.432 59.797 28.608 60.851 ;
     RECT  37.812 59.987 38.976 61.813 ;
     RECT  13.608 60.133 14.832 60.179 ;
     RECT  14.856 60.133 15.9 62.483 ;
     RECT  13.512 60.179 14.832 62.483 ;
     RECT  32.412 60.419 34.8 61.141 ;
     RECT  39 60.419 40.2 65.219 ;
     RECT  27.012 60.851 28.608 62.005 ;
     RECT  24.312 61.043 24.744 62.341 ;
     RECT  33 61.141 34.8 61.525 ;
     RECT  33 61.525 34.176 62.147 ;
     RECT  31.296 61.619 32.1 62.821 ;
     RECT  37.812 61.813 38.784 61.955 ;
     RECT  37.812 61.955 38.976 65.219 ;
     RECT  27.144 62.005 28.608 63.299 ;
     RECT  35.112 62.195 36.144 64.357 ;
     RECT  25.176 62.341 26.7 63.299 ;
     RECT  8.112 62.629 9.312 62.725 ;
     RECT  9.336 62.629 10.5 64.451 ;
     RECT  29.712 62.821 31.2 64.933 ;
     RECT  19.8 63.205 21.12 63.781 ;
     RECT  26.592 63.299 26.7 64.165 ;
     RECT  20.04 63.781 21.12 63.827 ;
     RECT  20.04 63.827 21.3 67.283 ;
     RECT  8.112 63.875 9.312 64.451 ;
     RECT  18.912 64.067 20.016 67.283 ;
     RECT  29.712 64.933 31.056 65.939 ;
     RECT  31.08 64.979 32.1 65.939 ;
     RECT  36.408 65.173 37.5 67.429 ;
     RECT  17.112 65.509 18.24 66.467 ;
     RECT  29.712 65.939 32.1 67.285 ;
     RECT  27.012 66.085 28.512 66.755 ;
     RECT  17.112 66.467 18.6 68.435 ;
     RECT  32.412 67.187 33 68.245 ;
     RECT  35.112 67.283 36.144 69.973 ;
     RECT  29.712 67.285 30.72 68.099 ;
     RECT  30.744 67.285 32.1 68.099 ;
     RECT  29.712 68.099 32.1 68.341 ;
     RECT  28.608 68.243 28.992 69.493 ;
     RECT  32.412 68.245 33.792 68.341 ;
     RECT  33.816 68.245 34.8 70.069 ;
     RECT  29.712 68.341 31.296 69.349 ;
     RECT  40.872 68.341 42 70.163 ;
     RECT  36.408 68.531 37.5 70.163 ;
     RECT  29.712 69.349 30.864 70.549 ;
     RECT  27.912 69.493 28.992 70.835 ;
     RECT  36.168 70.163 37.5 70.739 ;
     RECT  40.512 70.163 42 71.315 ;
     RECT  27.912 73.477 29.4 74.053 ;
     RECT  27.012 74.963 28.032 75.609 ;
     RECT  26.82 75.609 28.032 75.623 ;
  END
END dsfd_node_LLfu
END LIBRARY
